VERSION 5.8 ;
BUSBITCHARS "[]" ;
DIVIDERCHAR "/" ;
UNITS
    DATABASE MICRONS 1000 ;
END UNITS

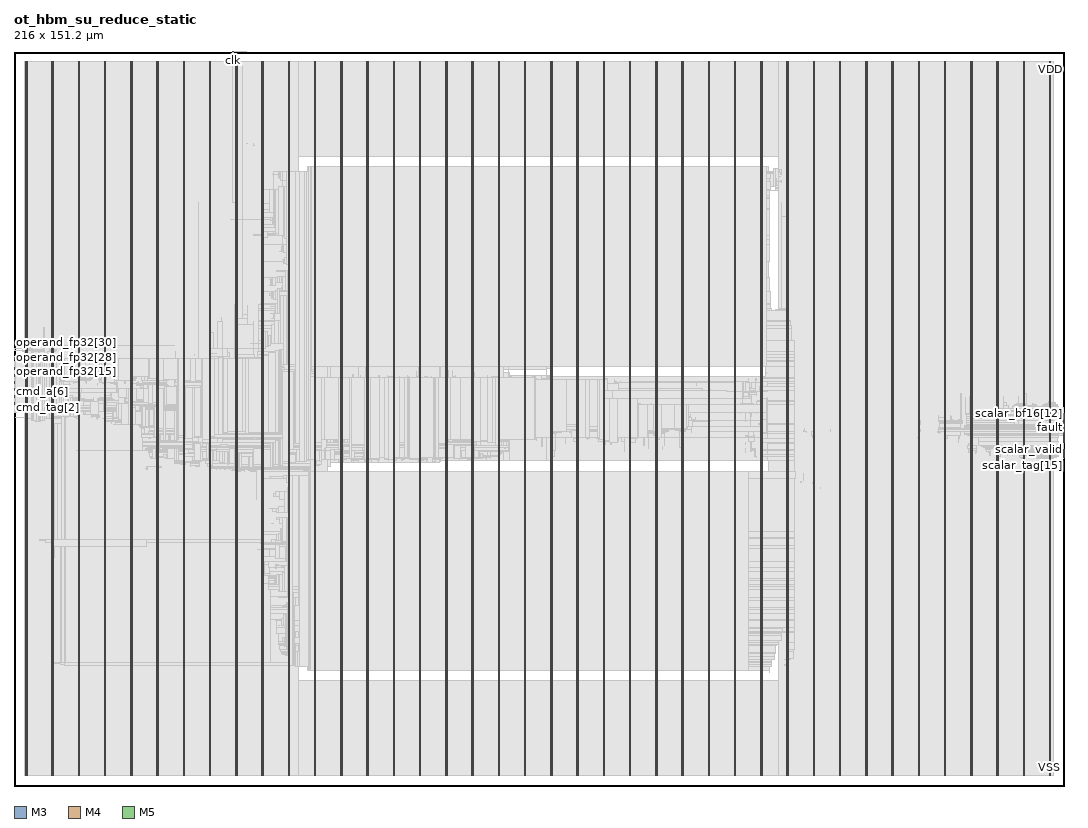
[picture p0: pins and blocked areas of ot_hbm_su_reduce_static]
MACRO ot_hbm_su_reduce_static
  FOREIGN ot_hbm_su_reduce_static 0 0 ;
  CLASS BLOCK ;
  SIZE 216 BY 151.2 ;
  PIN clk
    DIRECTION INPUT ;
    USE SIGNAL ;
    PORT
      LAYER M3 ;
        RECT  44.964 151.163 44.982 151.2 ;
    END
  END clk
  PIN cmd_a[0]
    DIRECTION INPUT ;
    USE SIGNAL ;
    PORT
      LAYER M4 ;
        RECT  0 80.592 0.084 80.616 ;
    END
  END cmd_a[0]
  PIN cmd_a[1]
    DIRECTION INPUT ;
    USE SIGNAL ;
    PORT
      LAYER M4 ;
        RECT  0 80.688 0.084 80.712 ;
    END
  END cmd_a[1]
  PIN cmd_a[2]
    DIRECTION INPUT ;
    USE SIGNAL ;
    PORT
      LAYER M4 ;
        RECT  0 80.784 0.084 80.808 ;
    END
  END cmd_a[2]
  PIN cmd_a[3]
    DIRECTION INPUT ;
    USE SIGNAL ;
    PORT
      LAYER M4 ;
        RECT  0 80.88 0.084 80.904 ;
    END
  END cmd_a[3]
  PIN cmd_a[4]
    DIRECTION INPUT ;
    USE SIGNAL ;
    PORT
      LAYER M4 ;
        RECT  0 80.976 0.084 81 ;
    END
  END cmd_a[4]
  PIN cmd_a[5]
    DIRECTION INPUT ;
    USE SIGNAL ;
    PORT
      LAYER M4 ;
        RECT  0 81.072 0.084 81.096 ;
    END
  END cmd_a[5]
  PIN cmd_a[6]
    DIRECTION INPUT ;
    USE SIGNAL ;
    PORT
      LAYER M4 ;
        RECT  0 81.168 0.084 81.192 ;
    END
  END cmd_a[6]
  PIN cmd_a[7]
    DIRECTION INPUT ;
    USE SIGNAL ;
    PORT
      LAYER M4 ;
        RECT  0 81.264 0.084 81.288 ;
    END
  END cmd_a[7]
  PIN cmd_a[8]
    DIRECTION INPUT ;
    USE SIGNAL ;
    PORT
      LAYER M4 ;
        RECT  0 81.36 0.084 81.384 ;
    END
  END cmd_a[8]
  PIN cmd_a[9]
    DIRECTION INPUT ;
    USE SIGNAL ;
    PORT
      LAYER M4 ;
        RECT  0 81.456 0.084 81.48 ;
    END
  END cmd_a[9]
  PIN cmd_b[0]
    DIRECTION INPUT ;
    USE SIGNAL ;
    PORT
      LAYER M4 ;
        RECT  0 81.552 0.084 81.576 ;
    END
  END cmd_b[0]
  PIN cmd_b[1]
    DIRECTION INPUT ;
    USE SIGNAL ;
    PORT
      LAYER M4 ;
        RECT  0 81.648 0.084 81.672 ;
    END
  END cmd_b[1]
  PIN cmd_b[2]
    DIRECTION INPUT ;
    USE SIGNAL ;
    PORT
      LAYER M4 ;
        RECT  0 81.744 0.084 81.768 ;
    END
  END cmd_b[2]
  PIN cmd_b[3]
    DIRECTION INPUT ;
    USE SIGNAL ;
    PORT
      LAYER M4 ;
        RECT  0 81.84 0.084 81.864 ;
    END
  END cmd_b[3]
  PIN cmd_b[4]
    DIRECTION INPUT ;
    USE SIGNAL ;
    PORT
      LAYER M4 ;
        RECT  0 81.936 0.084 81.96 ;
    END
  END cmd_b[4]
  PIN cmd_b[5]
    DIRECTION INPUT ;
    USE SIGNAL ;
    PORT
      LAYER M4 ;
        RECT  0 82.032 0.084 82.056 ;
    END
  END cmd_b[5]
  PIN cmd_b[6]
    DIRECTION INPUT ;
    USE SIGNAL ;
    PORT
      LAYER M4 ;
        RECT  0 82.128 0.084 82.152 ;
    END
  END cmd_b[6]
  PIN cmd_b[7]
    DIRECTION INPUT ;
    USE SIGNAL ;
    PORT
      LAYER M4 ;
        RECT  0 82.224 0.084 82.248 ;
    END
  END cmd_b[7]
  PIN cmd_b[8]
    DIRECTION INPUT ;
    USE SIGNAL ;
    PORT
      LAYER M4 ;
        RECT  0 82.32 0.084 82.344 ;
    END
  END cmd_b[8]
  PIN cmd_b[9]
    DIRECTION INPUT ;
    USE SIGNAL ;
    PORT
      LAYER M4 ;
        RECT  0 82.416 0.084 82.44 ;
    END
  END cmd_b[9]
  PIN cmd_dst[0]
    DIRECTION INPUT ;
    USE SIGNAL ;
    PORT
      LAYER M4 ;
        RECT  0 82.512 0.084 82.536 ;
    END
  END cmd_dst[0]
  PIN cmd_dst[1]
    DIRECTION INPUT ;
    USE SIGNAL ;
    PORT
      LAYER M4 ;
        RECT  0 82.608 0.084 82.632 ;
    END
  END cmd_dst[1]
  PIN cmd_dst[2]
    DIRECTION INPUT ;
    USE SIGNAL ;
    PORT
      LAYER M4 ;
        RECT  0 82.704 0.084 82.728 ;
    END
  END cmd_dst[2]
  PIN cmd_dst[3]
    DIRECTION INPUT ;
    USE SIGNAL ;
    PORT
      LAYER M4 ;
        RECT  0 82.8 0.084 82.824 ;
    END
  END cmd_dst[3]
  PIN cmd_dst[4]
    DIRECTION INPUT ;
    USE SIGNAL ;
    PORT
      LAYER M4 ;
        RECT  0 82.896 0.084 82.92 ;
    END
  END cmd_dst[4]
  PIN cmd_dst[5]
    DIRECTION INPUT ;
    USE SIGNAL ;
    PORT
      LAYER M4 ;
        RECT  0 82.992 0.084 83.016 ;
    END
  END cmd_dst[5]
  PIN cmd_dst[6]
    DIRECTION INPUT ;
    USE SIGNAL ;
    PORT
      LAYER M4 ;
        RECT  0 83.088 0.084 83.112 ;
    END
  END cmd_dst[6]
  PIN cmd_dst[7]
    DIRECTION INPUT ;
    USE SIGNAL ;
    PORT
      LAYER M4 ;
        RECT  0 83.184 0.084 83.208 ;
    END
  END cmd_dst[7]
  PIN cmd_dst[8]
    DIRECTION INPUT ;
    USE SIGNAL ;
    PORT
      LAYER M4 ;
        RECT  0 83.28 0.084 83.304 ;
    END
  END cmd_dst[8]
  PIN cmd_dst[9]
    DIRECTION INPUT ;
    USE SIGNAL ;
    PORT
      LAYER M4 ;
        RECT  0 83.376 0.084 83.4 ;
    END
  END cmd_dst[9]
  PIN cmd_op[0]
    DIRECTION INPUT ;
    USE SIGNAL ;
    PORT
      LAYER M4 ;
        RECT  0 83.472 0.084 83.496 ;
    END
  END cmd_op[0]
  PIN cmd_op[1]
    DIRECTION INPUT ;
    USE SIGNAL ;
    PORT
      LAYER M4 ;
        RECT  0 83.568 0.084 83.592 ;
    END
  END cmd_op[1]
  PIN cmd_op[2]
    DIRECTION INPUT ;
    USE SIGNAL ;
    PORT
      LAYER M4 ;
        RECT  0 77.52 0.084 77.544 ;
    END
  END cmd_op[2]
  PIN cmd_tag[0]
    DIRECTION INPUT ;
    USE SIGNAL ;
    PORT
      LAYER M4 ;
        RECT  0 77.616 0.084 77.64 ;
    END
  END cmd_tag[0]
  PIN cmd_tag[10]
    DIRECTION INPUT ;
    USE SIGNAL ;
    PORT
      LAYER M4 ;
        RECT  0 78.576 0.084 78.6 ;
    END
  END cmd_tag[10]
  PIN cmd_tag[11]
    DIRECTION INPUT ;
    USE SIGNAL ;
    PORT
      LAYER M4 ;
        RECT  0 78.672 0.084 78.696 ;
    END
  END cmd_tag[11]
  PIN cmd_tag[12]
    DIRECTION INPUT ;
    USE SIGNAL ;
    PORT
      LAYER M4 ;
        RECT  0 78.768 0.084 78.792 ;
    END
  END cmd_tag[12]
  PIN cmd_tag[13]
    DIRECTION INPUT ;
    USE SIGNAL ;
    PORT
      LAYER M4 ;
        RECT  0 78.864 0.084 78.888 ;
    END
  END cmd_tag[13]
  PIN cmd_tag[14]
    DIRECTION INPUT ;
    USE SIGNAL ;
    PORT
      LAYER M4 ;
        RECT  0 78.96 0.084 78.984 ;
    END
  END cmd_tag[14]
  PIN cmd_tag[15]
    DIRECTION INPUT ;
    USE SIGNAL ;
    PORT
      LAYER M4 ;
        RECT  0 79.056 0.084 79.08 ;
    END
  END cmd_tag[15]
  PIN cmd_tag[16]
    DIRECTION INPUT ;
    USE SIGNAL ;
    PORT
      LAYER M4 ;
        RECT  0 79.152 0.084 79.176 ;
    END
  END cmd_tag[16]
  PIN cmd_tag[17]
    DIRECTION INPUT ;
    USE SIGNAL ;
    PORT
      LAYER M4 ;
        RECT  0 79.248 0.084 79.272 ;
    END
  END cmd_tag[17]
  PIN cmd_tag[18]
    DIRECTION INPUT ;
    USE SIGNAL ;
    PORT
      LAYER M4 ;
        RECT  0 79.344 0.084 79.368 ;
    END
  END cmd_tag[18]
  PIN cmd_tag[19]
    DIRECTION INPUT ;
    USE SIGNAL ;
    PORT
      LAYER M4 ;
        RECT  0 79.44 0.084 79.464 ;
    END
  END cmd_tag[19]
  PIN cmd_tag[1]
    DIRECTION INPUT ;
    USE SIGNAL ;
    PORT
      LAYER M4 ;
        RECT  0 77.712 0.084 77.736 ;
    END
  END cmd_tag[1]
  PIN cmd_tag[20]
    DIRECTION INPUT ;
    USE SIGNAL ;
    PORT
      LAYER M4 ;
        RECT  0 79.536 0.084 79.56 ;
    END
  END cmd_tag[20]
  PIN cmd_tag[21]
    DIRECTION INPUT ;
    USE SIGNAL ;
    PORT
      LAYER M4 ;
        RECT  0 79.632 0.084 79.656 ;
    END
  END cmd_tag[21]
  PIN cmd_tag[22]
    DIRECTION INPUT ;
    USE SIGNAL ;
    PORT
      LAYER M4 ;
        RECT  0 79.728 0.084 79.752 ;
    END
  END cmd_tag[22]
  PIN cmd_tag[23]
    DIRECTION INPUT ;
    USE SIGNAL ;
    PORT
      LAYER M4 ;
        RECT  0 79.824 0.084 79.848 ;
    END
  END cmd_tag[23]
  PIN cmd_tag[24]
    DIRECTION INPUT ;
    USE SIGNAL ;
    PORT
      LAYER M4 ;
        RECT  0 79.92 0.084 79.944 ;
    END
  END cmd_tag[24]
  PIN cmd_tag[25]
    DIRECTION INPUT ;
    USE SIGNAL ;
    PORT
      LAYER M4 ;
        RECT  0 80.016 0.084 80.04 ;
    END
  END cmd_tag[25]
  PIN cmd_tag[26]
    DIRECTION INPUT ;
    USE SIGNAL ;
    PORT
      LAYER M4 ;
        RECT  0 80.112 0.084 80.136 ;
    END
  END cmd_tag[26]
  PIN cmd_tag[27]
    DIRECTION INPUT ;
    USE SIGNAL ;
    PORT
      LAYER M4 ;
        RECT  0 80.208 0.084 80.232 ;
    END
  END cmd_tag[27]
  PIN cmd_tag[28]
    DIRECTION INPUT ;
    USE SIGNAL ;
    PORT
      LAYER M4 ;
        RECT  0 80.304 0.084 80.328 ;
    END
  END cmd_tag[28]
  PIN cmd_tag[29]
    DIRECTION INPUT ;
    USE SIGNAL ;
    PORT
      LAYER M4 ;
        RECT  0 80.4 0.084 80.424 ;
    END
  END cmd_tag[29]
  PIN cmd_tag[2]
    DIRECTION INPUT ;
    USE SIGNAL ;
    PORT
      LAYER M4 ;
        RECT  0 77.808 0.084 77.832 ;
    END
  END cmd_tag[2]
  PIN cmd_tag[30]
    DIRECTION INPUT ;
    USE SIGNAL ;
    PORT
      LAYER M4 ;
        RECT  0 80.496 0.084 80.52 ;
    END
  END cmd_tag[30]
  PIN cmd_tag[31]
    DIRECTION INPUT ;
    USE SIGNAL ;
    PORT
      LAYER M4 ;
        RECT  0 83.664 0.084 83.688 ;
    END
  END cmd_tag[31]
  PIN cmd_tag[3]
    DIRECTION INPUT ;
    USE SIGNAL ;
    PORT
      LAYER M4 ;
        RECT  0 77.904 0.084 77.928 ;
    END
  END cmd_tag[3]
  PIN cmd_tag[4]
    DIRECTION INPUT ;
    USE SIGNAL ;
    PORT
      LAYER M4 ;
        RECT  0 78 0.084 78.024 ;
    END
  END cmd_tag[4]
  PIN cmd_tag[5]
    DIRECTION INPUT ;
    USE SIGNAL ;
    PORT
      LAYER M4 ;
        RECT  0 78.096 0.084 78.12 ;
    END
  END cmd_tag[5]
  PIN cmd_tag[6]
    DIRECTION INPUT ;
    USE SIGNAL ;
    PORT
      LAYER M4 ;
        RECT  0 78.192 0.084 78.216 ;
    END
  END cmd_tag[6]
  PIN cmd_tag[7]
    DIRECTION INPUT ;
    USE SIGNAL ;
    PORT
      LAYER M4 ;
        RECT  0 78.288 0.084 78.312 ;
    END
  END cmd_tag[7]
  PIN cmd_tag[8]
    DIRECTION INPUT ;
    USE SIGNAL ;
    PORT
      LAYER M4 ;
        RECT  0 78.384 0.084 78.408 ;
    END
  END cmd_tag[8]
  PIN cmd_tag[9]
    DIRECTION INPUT ;
    USE SIGNAL ;
    PORT
      LAYER M4 ;
        RECT  0 78.48 0.084 78.504 ;
    END
  END cmd_tag[9]
  PIN cmd_valid
    DIRECTION INPUT ;
    USE SIGNAL ;
    PORT
      LAYER M4 ;
        RECT  0 83.76 0.084 83.784 ;
    END
  END cmd_valid
  PIN fault
    DIRECTION OUTPUT ;
    USE SIGNAL ;
    PORT
      LAYER M4 ;
        RECT  215.916 73.68 216 73.704 ;
    END
  END fault
  PIN operand_fp32[0]
    DIRECTION INPUT ;
    USE SIGNAL ;
    PORT
      LAYER M4 ;
        RECT  0 83.856 0.084 83.88 ;
    END
  END operand_fp32[0]
  PIN operand_fp32[10]
    DIRECTION INPUT ;
    USE SIGNAL ;
    PORT
      LAYER M4 ;
        RECT  0 84.816 0.084 84.84 ;
    END
  END operand_fp32[10]
  PIN operand_fp32[11]
    DIRECTION INPUT ;
    USE SIGNAL ;
    PORT
      LAYER M4 ;
        RECT  0 84.912 0.084 84.936 ;
    END
  END operand_fp32[11]
  PIN operand_fp32[12]
    DIRECTION INPUT ;
    USE SIGNAL ;
    PORT
      LAYER M4 ;
        RECT  0 85.008 0.084 85.032 ;
    END
  END operand_fp32[12]
  PIN operand_fp32[13]
    DIRECTION INPUT ;
    USE SIGNAL ;
    PORT
      LAYER M4 ;
        RECT  0 85.104 0.084 85.128 ;
    END
  END operand_fp32[13]
  PIN operand_fp32[14]
    DIRECTION INPUT ;
    USE SIGNAL ;
    PORT
      LAYER M4 ;
        RECT  0 85.2 0.084 85.224 ;
    END
  END operand_fp32[14]
  PIN operand_fp32[15]
    DIRECTION INPUT ;
    USE SIGNAL ;
    PORT
      LAYER M4 ;
        RECT  0 85.296 0.084 85.32 ;
    END
  END operand_fp32[15]
  PIN operand_fp32[16]
    DIRECTION INPUT ;
    USE SIGNAL ;
    PORT
      LAYER M4 ;
        RECT  0 85.392 0.084 85.416 ;
    END
  END operand_fp32[16]
  PIN operand_fp32[17]
    DIRECTION INPUT ;
    USE SIGNAL ;
    PORT
      LAYER M4 ;
        RECT  0 85.488 0.084 85.512 ;
    END
  END operand_fp32[17]
  PIN operand_fp32[18]
    DIRECTION INPUT ;
    USE SIGNAL ;
    PORT
      LAYER M4 ;
        RECT  0 85.584 0.084 85.608 ;
    END
  END operand_fp32[18]
  PIN operand_fp32[19]
    DIRECTION INPUT ;
    USE SIGNAL ;
    PORT
      LAYER M4 ;
        RECT  0 85.68 0.084 85.704 ;
    END
  END operand_fp32[19]
  PIN operand_fp32[1]
    DIRECTION INPUT ;
    USE SIGNAL ;
    PORT
      LAYER M4 ;
        RECT  0 83.952 0.084 83.976 ;
    END
  END operand_fp32[1]
  PIN operand_fp32[20]
    DIRECTION INPUT ;
    USE SIGNAL ;
    PORT
      LAYER M4 ;
        RECT  0 85.776 0.084 85.8 ;
    END
  END operand_fp32[20]
  PIN operand_fp32[21]
    DIRECTION INPUT ;
    USE SIGNAL ;
    PORT
      LAYER M4 ;
        RECT  0 85.872 0.084 85.896 ;
    END
  END operand_fp32[21]
  PIN operand_fp32[22]
    DIRECTION INPUT ;
    USE SIGNAL ;
    PORT
      LAYER M4 ;
        RECT  0 85.968 0.084 85.992 ;
    END
  END operand_fp32[22]
  PIN operand_fp32[23]
    DIRECTION INPUT ;
    USE SIGNAL ;
    PORT
      LAYER M4 ;
        RECT  0 86.064 0.084 86.088 ;
    END
  END operand_fp32[23]
  PIN operand_fp32[24]
    DIRECTION INPUT ;
    USE SIGNAL ;
    PORT
      LAYER M4 ;
        RECT  0 86.16 0.084 86.184 ;
    END
  END operand_fp32[24]
  PIN operand_fp32[25]
    DIRECTION INPUT ;
    USE SIGNAL ;
    PORT
      LAYER M4 ;
        RECT  0 86.256 0.084 86.28 ;
    END
  END operand_fp32[25]
  PIN operand_fp32[26]
    DIRECTION INPUT ;
    USE SIGNAL ;
    PORT
      LAYER M4 ;
        RECT  0 86.352 0.084 86.376 ;
    END
  END operand_fp32[26]
  PIN operand_fp32[27]
    DIRECTION INPUT ;
    USE SIGNAL ;
    PORT
      LAYER M4 ;
        RECT  0 86.448 0.084 86.472 ;
    END
  END operand_fp32[27]
  PIN operand_fp32[28]
    DIRECTION INPUT ;
    USE SIGNAL ;
    PORT
      LAYER M4 ;
        RECT  0 86.544 0.084 86.568 ;
    END
  END operand_fp32[28]
  PIN operand_fp32[29]
    DIRECTION INPUT ;
    USE SIGNAL ;
    PORT
      LAYER M4 ;
        RECT  0 86.64 0.084 86.664 ;
    END
  END operand_fp32[29]
  PIN operand_fp32[2]
    DIRECTION INPUT ;
    USE SIGNAL ;
    PORT
      LAYER M4 ;
        RECT  0 84.048 0.084 84.072 ;
    END
  END operand_fp32[2]
  PIN operand_fp32[30]
    DIRECTION INPUT ;
    USE SIGNAL ;
    PORT
      LAYER M4 ;
        RECT  0 89.616 0.084 89.64 ;
    END
  END operand_fp32[30]
  PIN operand_fp32[31]
    DIRECTION INPUT ;
    USE SIGNAL ;
    PORT
      LAYER M4 ;
        RECT  0 89.712 0.084 89.736 ;
    END
  END operand_fp32[31]
  PIN operand_fp32[3]
    DIRECTION INPUT ;
    USE SIGNAL ;
    PORT
      LAYER M4 ;
        RECT  0 84.144 0.084 84.168 ;
    END
  END operand_fp32[3]
  PIN operand_fp32[4]
    DIRECTION INPUT ;
    USE SIGNAL ;
    PORT
      LAYER M4 ;
        RECT  0 84.24 0.084 84.264 ;
    END
  END operand_fp32[4]
  PIN operand_fp32[5]
    DIRECTION INPUT ;
    USE SIGNAL ;
    PORT
      LAYER M4 ;
        RECT  0 84.336 0.084 84.36 ;
    END
  END operand_fp32[5]
  PIN operand_fp32[6]
    DIRECTION INPUT ;
    USE SIGNAL ;
    PORT
      LAYER M4 ;
        RECT  0 84.432 0.084 84.456 ;
    END
  END operand_fp32[6]
  PIN operand_fp32[7]
    DIRECTION INPUT ;
    USE SIGNAL ;
    PORT
      LAYER M4 ;
        RECT  0 84.528 0.084 84.552 ;
    END
  END operand_fp32[7]
  PIN operand_fp32[8]
    DIRECTION INPUT ;
    USE SIGNAL ;
    PORT
      LAYER M4 ;
        RECT  0 84.624 0.084 84.648 ;
    END
  END operand_fp32[8]
  PIN operand_fp32[9]
    DIRECTION INPUT ;
    USE SIGNAL ;
    PORT
      LAYER M4 ;
        RECT  0 84.72 0.084 84.744 ;
    END
  END operand_fp32[9]
  PIN rst_n
    DIRECTION INPUT ;
    USE SIGNAL ;
    PORT
      LAYER M3 ;
        RECT  45.036 151.163 45.054 151.2 ;
    END
  END rst_n
  PIN scalar_bf16[0]
    DIRECTION OUTPUT ;
    USE SIGNAL ;
    PORT
      LAYER M4 ;
        RECT  215.916 73.776 216 73.8 ;
    END
  END scalar_bf16[0]
  PIN scalar_bf16[10]
    DIRECTION OUTPUT ;
    USE SIGNAL ;
    PORT
      LAYER M4 ;
        RECT  215.916 74.736 216 74.76 ;
    END
  END scalar_bf16[10]
  PIN scalar_bf16[11]
    DIRECTION OUTPUT ;
    USE SIGNAL ;
    PORT
      LAYER M4 ;
        RECT  215.916 74.832 216 74.856 ;
    END
  END scalar_bf16[11]
  PIN scalar_bf16[12]
    DIRECTION OUTPUT ;
    USE SIGNAL ;
    PORT
      LAYER M4 ;
        RECT  215.916 74.928 216 74.952 ;
    END
  END scalar_bf16[12]
  PIN scalar_bf16[13]
    DIRECTION OUTPUT ;
    USE SIGNAL ;
    PORT
      LAYER M4 ;
        RECT  215.916 75.024 216 75.048 ;
    END
  END scalar_bf16[13]
  PIN scalar_bf16[14]
    DIRECTION OUTPUT ;
    USE SIGNAL ;
    PORT
      LAYER M4 ;
        RECT  215.916 75.12 216 75.144 ;
    END
  END scalar_bf16[14]
  PIN scalar_bf16[15]
    DIRECTION OUTPUT ;
    USE SIGNAL ;
    PORT
      LAYER M4 ;
        RECT  215.916 75.216 216 75.24 ;
    END
  END scalar_bf16[15]
  PIN scalar_bf16[1]
    DIRECTION OUTPUT ;
    USE SIGNAL ;
    PORT
      LAYER M4 ;
        RECT  215.916 73.872 216 73.896 ;
    END
  END scalar_bf16[1]
  PIN scalar_bf16[2]
    DIRECTION OUTPUT ;
    USE SIGNAL ;
    PORT
      LAYER M4 ;
        RECT  215.916 73.968 216 73.992 ;
    END
  END scalar_bf16[2]
  PIN scalar_bf16[3]
    DIRECTION OUTPUT ;
    USE SIGNAL ;
    PORT
      LAYER M4 ;
        RECT  215.916 74.064 216 74.088 ;
    END
  END scalar_bf16[3]
  PIN scalar_bf16[4]
    DIRECTION OUTPUT ;
    USE SIGNAL ;
    PORT
      LAYER M4 ;
        RECT  215.916 74.16 216 74.184 ;
    END
  END scalar_bf16[4]
  PIN scalar_bf16[5]
    DIRECTION OUTPUT ;
    USE SIGNAL ;
    PORT
      LAYER M4 ;
        RECT  215.916 74.256 216 74.28 ;
    END
  END scalar_bf16[5]
  PIN scalar_bf16[6]
    DIRECTION OUTPUT ;
    USE SIGNAL ;
    PORT
      LAYER M4 ;
        RECT  215.916 74.352 216 74.376 ;
    END
  END scalar_bf16[6]
  PIN scalar_bf16[7]
    DIRECTION OUTPUT ;
    USE SIGNAL ;
    PORT
      LAYER M4 ;
        RECT  215.916 74.448 216 74.472 ;
    END
  END scalar_bf16[7]
  PIN scalar_bf16[8]
    DIRECTION OUTPUT ;
    USE SIGNAL ;
    PORT
      LAYER M4 ;
        RECT  215.916 74.544 216 74.568 ;
    END
  END scalar_bf16[8]
  PIN scalar_bf16[9]
    DIRECTION OUTPUT ;
    USE SIGNAL ;
    PORT
      LAYER M4 ;
        RECT  215.916 74.64 216 74.664 ;
    END
  END scalar_bf16[9]
  PIN scalar_fp32[0]
    DIRECTION OUTPUT ;
    USE SIGNAL ;
    PORT
      LAYER M4 ;
        RECT  215.916 75.312 216 75.336 ;
    END
  END scalar_fp32[0]
  PIN scalar_fp32[10]
    DIRECTION OUTPUT ;
    USE SIGNAL ;
    PORT
      LAYER M4 ;
        RECT  215.916 76.272 216 76.296 ;
    END
  END scalar_fp32[10]
  PIN scalar_fp32[11]
    DIRECTION OUTPUT ;
    USE SIGNAL ;
    PORT
      LAYER M4 ;
        RECT  215.916 76.368 216 76.392 ;
    END
  END scalar_fp32[11]
  PIN scalar_fp32[12]
    DIRECTION OUTPUT ;
    USE SIGNAL ;
    PORT
      LAYER M4 ;
        RECT  215.916 76.464 216 76.488 ;
    END
  END scalar_fp32[12]
  PIN scalar_fp32[13]
    DIRECTION OUTPUT ;
    USE SIGNAL ;
    PORT
      LAYER M4 ;
        RECT  215.916 76.56 216 76.584 ;
    END
  END scalar_fp32[13]
  PIN scalar_fp32[14]
    DIRECTION OUTPUT ;
    USE SIGNAL ;
    PORT
      LAYER M4 ;
        RECT  215.916 76.656 216 76.68 ;
    END
  END scalar_fp32[14]
  PIN scalar_fp32[15]
    DIRECTION OUTPUT ;
    USE SIGNAL ;
    PORT
      LAYER M4 ;
        RECT  215.916 70.608 216 70.632 ;
    END
  END scalar_fp32[15]
  PIN scalar_fp32[16]
    DIRECTION OUTPUT ;
    USE SIGNAL ;
    PORT
      LAYER M4 ;
        RECT  215.916 70.704 216 70.728 ;
    END
  END scalar_fp32[16]
  PIN scalar_fp32[17]
    DIRECTION OUTPUT ;
    USE SIGNAL ;
    PORT
      LAYER M4 ;
        RECT  215.916 70.8 216 70.824 ;
    END
  END scalar_fp32[17]
  PIN scalar_fp32[18]
    DIRECTION OUTPUT ;
    USE SIGNAL ;
    PORT
      LAYER M4 ;
        RECT  215.916 70.896 216 70.92 ;
    END
  END scalar_fp32[18]
  PIN scalar_fp32[19]
    DIRECTION OUTPUT ;
    USE SIGNAL ;
    PORT
      LAYER M4 ;
        RECT  215.916 70.992 216 71.016 ;
    END
  END scalar_fp32[19]
  PIN scalar_fp32[1]
    DIRECTION OUTPUT ;
    USE SIGNAL ;
    PORT
      LAYER M4 ;
        RECT  215.916 75.408 216 75.432 ;
    END
  END scalar_fp32[1]
  PIN scalar_fp32[20]
    DIRECTION OUTPUT ;
    USE SIGNAL ;
    PORT
      LAYER M4 ;
        RECT  215.916 71.088 216 71.112 ;
    END
  END scalar_fp32[20]
  PIN scalar_fp32[21]
    DIRECTION OUTPUT ;
    USE SIGNAL ;
    PORT
      LAYER M4 ;
        RECT  215.916 71.184 216 71.208 ;
    END
  END scalar_fp32[21]
  PIN scalar_fp32[22]
    DIRECTION OUTPUT ;
    USE SIGNAL ;
    PORT
      LAYER M4 ;
        RECT  215.916 71.28 216 71.304 ;
    END
  END scalar_fp32[22]
  PIN scalar_fp32[23]
    DIRECTION OUTPUT ;
    USE SIGNAL ;
    PORT
      LAYER M4 ;
        RECT  215.916 71.376 216 71.4 ;
    END
  END scalar_fp32[23]
  PIN scalar_fp32[24]
    DIRECTION OUTPUT ;
    USE SIGNAL ;
    PORT
      LAYER M4 ;
        RECT  215.916 71.472 216 71.496 ;
    END
  END scalar_fp32[24]
  PIN scalar_fp32[25]
    DIRECTION OUTPUT ;
    USE SIGNAL ;
    PORT
      LAYER M4 ;
        RECT  215.916 71.568 216 71.592 ;
    END
  END scalar_fp32[25]
  PIN scalar_fp32[26]
    DIRECTION OUTPUT ;
    USE SIGNAL ;
    PORT
      LAYER M4 ;
        RECT  215.916 71.664 216 71.688 ;
    END
  END scalar_fp32[26]
  PIN scalar_fp32[27]
    DIRECTION OUTPUT ;
    USE SIGNAL ;
    PORT
      LAYER M4 ;
        RECT  215.916 71.76 216 71.784 ;
    END
  END scalar_fp32[27]
  PIN scalar_fp32[28]
    DIRECTION OUTPUT ;
    USE SIGNAL ;
    PORT
      LAYER M4 ;
        RECT  215.916 71.856 216 71.88 ;
    END
  END scalar_fp32[28]
  PIN scalar_fp32[29]
    DIRECTION OUTPUT ;
    USE SIGNAL ;
    PORT
      LAYER M4 ;
        RECT  215.916 71.952 216 71.976 ;
    END
  END scalar_fp32[29]
  PIN scalar_fp32[2]
    DIRECTION OUTPUT ;
    USE SIGNAL ;
    PORT
      LAYER M4 ;
        RECT  215.916 75.504 216 75.528 ;
    END
  END scalar_fp32[2]
  PIN scalar_fp32[30]
    DIRECTION OUTPUT ;
    USE SIGNAL ;
    PORT
      LAYER M4 ;
        RECT  215.916 72.048 216 72.072 ;
    END
  END scalar_fp32[30]
  PIN scalar_fp32[31]
    DIRECTION OUTPUT ;
    USE SIGNAL ;
    PORT
      LAYER M4 ;
        RECT  215.916 72.144 216 72.168 ;
    END
  END scalar_fp32[31]
  PIN scalar_fp32[3]
    DIRECTION OUTPUT ;
    USE SIGNAL ;
    PORT
      LAYER M4 ;
        RECT  215.916 75.6 216 75.624 ;
    END
  END scalar_fp32[3]
  PIN scalar_fp32[4]
    DIRECTION OUTPUT ;
    USE SIGNAL ;
    PORT
      LAYER M4 ;
        RECT  215.916 75.696 216 75.72 ;
    END
  END scalar_fp32[4]
  PIN scalar_fp32[5]
    DIRECTION OUTPUT ;
    USE SIGNAL ;
    PORT
      LAYER M4 ;
        RECT  215.916 75.792 216 75.816 ;
    END
  END scalar_fp32[5]
  PIN scalar_fp32[6]
    DIRECTION OUTPUT ;
    USE SIGNAL ;
    PORT
      LAYER M4 ;
        RECT  215.916 75.888 216 75.912 ;
    END
  END scalar_fp32[6]
  PIN scalar_fp32[7]
    DIRECTION OUTPUT ;
    USE SIGNAL ;
    PORT
      LAYER M4 ;
        RECT  215.916 75.984 216 76.008 ;
    END
  END scalar_fp32[7]
  PIN scalar_fp32[8]
    DIRECTION OUTPUT ;
    USE SIGNAL ;
    PORT
      LAYER M4 ;
        RECT  215.916 76.08 216 76.104 ;
    END
  END scalar_fp32[8]
  PIN scalar_fp32[9]
    DIRECTION OUTPUT ;
    USE SIGNAL ;
    PORT
      LAYER M4 ;
        RECT  215.916 76.176 216 76.2 ;
    END
  END scalar_fp32[9]
  PIN scalar_tag[0]
    DIRECTION OUTPUT ;
    USE SIGNAL ;
    PORT
      LAYER M4 ;
        RECT  215.916 72.24 216 72.264 ;
    END
  END scalar_tag[0]
  PIN scalar_tag[10]
    DIRECTION OUTPUT ;
    USE SIGNAL ;
    PORT
      LAYER M4 ;
        RECT  215.916 73.2 216 73.224 ;
    END
  END scalar_tag[10]
  PIN scalar_tag[11]
    DIRECTION OUTPUT ;
    USE SIGNAL ;
    PORT
      LAYER M4 ;
        RECT  215.916 73.296 216 73.32 ;
    END
  END scalar_tag[11]
  PIN scalar_tag[12]
    DIRECTION OUTPUT ;
    USE SIGNAL ;
    PORT
      LAYER M4 ;
        RECT  215.916 73.392 216 73.416 ;
    END
  END scalar_tag[12]
  PIN scalar_tag[13]
    DIRECTION OUTPUT ;
    USE SIGNAL ;
    PORT
      LAYER M4 ;
        RECT  215.916 73.488 216 73.512 ;
    END
  END scalar_tag[13]
  PIN scalar_tag[14]
    DIRECTION OUTPUT ;
    USE SIGNAL ;
    PORT
      LAYER M4 ;
        RECT  215.916 73.584 216 73.608 ;
    END
  END scalar_tag[14]
  PIN scalar_tag[15]
    DIRECTION OUTPUT ;
    USE SIGNAL ;
    PORT
      LAYER M4 ;
        RECT  215.916 67.536 216 67.56 ;
    END
  END scalar_tag[15]
  PIN scalar_tag[16]
    DIRECTION OUTPUT ;
    USE SIGNAL ;
    PORT
      LAYER M4 ;
        RECT  215.916 67.632 216 67.656 ;
    END
  END scalar_tag[16]
  PIN scalar_tag[17]
    DIRECTION OUTPUT ;
    USE SIGNAL ;
    PORT
      LAYER M4 ;
        RECT  215.916 67.728 216 67.752 ;
    END
  END scalar_tag[17]
  PIN scalar_tag[18]
    DIRECTION OUTPUT ;
    USE SIGNAL ;
    PORT
      LAYER M4 ;
        RECT  215.916 67.824 216 67.848 ;
    END
  END scalar_tag[18]
  PIN scalar_tag[19]
    DIRECTION OUTPUT ;
    USE SIGNAL ;
    PORT
      LAYER M4 ;
        RECT  215.916 67.92 216 67.944 ;
    END
  END scalar_tag[19]
  PIN scalar_tag[1]
    DIRECTION OUTPUT ;
    USE SIGNAL ;
    PORT
      LAYER M4 ;
        RECT  215.916 72.336 216 72.36 ;
    END
  END scalar_tag[1]
  PIN scalar_tag[20]
    DIRECTION OUTPUT ;
    USE SIGNAL ;
    PORT
      LAYER M4 ;
        RECT  215.916 68.016 216 68.04 ;
    END
  END scalar_tag[20]
  PIN scalar_tag[21]
    DIRECTION OUTPUT ;
    USE SIGNAL ;
    PORT
      LAYER M4 ;
        RECT  215.916 68.112 216 68.136 ;
    END
  END scalar_tag[21]
  PIN scalar_tag[22]
    DIRECTION OUTPUT ;
    USE SIGNAL ;
    PORT
      LAYER M4 ;
        RECT  215.916 68.208 216 68.232 ;
    END
  END scalar_tag[22]
  PIN scalar_tag[23]
    DIRECTION OUTPUT ;
    USE SIGNAL ;
    PORT
      LAYER M4 ;
        RECT  215.916 68.304 216 68.328 ;
    END
  END scalar_tag[23]
  PIN scalar_tag[24]
    DIRECTION OUTPUT ;
    USE SIGNAL ;
    PORT
      LAYER M4 ;
        RECT  215.916 68.4 216 68.424 ;
    END
  END scalar_tag[24]
  PIN scalar_tag[25]
    DIRECTION OUTPUT ;
    USE SIGNAL ;
    PORT
      LAYER M4 ;
        RECT  215.916 68.496 216 68.52 ;
    END
  END scalar_tag[25]
  PIN scalar_tag[26]
    DIRECTION OUTPUT ;
    USE SIGNAL ;
    PORT
      LAYER M4 ;
        RECT  215.916 68.592 216 68.616 ;
    END
  END scalar_tag[26]
  PIN scalar_tag[27]
    DIRECTION OUTPUT ;
    USE SIGNAL ;
    PORT
      LAYER M4 ;
        RECT  215.916 68.688 216 68.712 ;
    END
  END scalar_tag[27]
  PIN scalar_tag[28]
    DIRECTION OUTPUT ;
    USE SIGNAL ;
    PORT
      LAYER M4 ;
        RECT  215.916 68.784 216 68.808 ;
    END
  END scalar_tag[28]
  PIN scalar_tag[29]
    DIRECTION OUTPUT ;
    USE SIGNAL ;
    PORT
      LAYER M4 ;
        RECT  215.916 68.88 216 68.904 ;
    END
  END scalar_tag[29]
  PIN scalar_tag[2]
    DIRECTION OUTPUT ;
    USE SIGNAL ;
    PORT
      LAYER M4 ;
        RECT  215.916 72.432 216 72.456 ;
    END
  END scalar_tag[2]
  PIN scalar_tag[30]
    DIRECTION OUTPUT ;
    USE SIGNAL ;
    PORT
      LAYER M4 ;
        RECT  215.916 68.976 216 69 ;
    END
  END scalar_tag[30]
  PIN scalar_tag[31]
    DIRECTION OUTPUT ;
    USE SIGNAL ;
    PORT
      LAYER M4 ;
        RECT  215.916 69.072 216 69.096 ;
    END
  END scalar_tag[31]
  PIN scalar_tag[3]
    DIRECTION OUTPUT ;
    USE SIGNAL ;
    PORT
      LAYER M4 ;
        RECT  215.916 72.528 216 72.552 ;
    END
  END scalar_tag[3]
  PIN scalar_tag[4]
    DIRECTION OUTPUT ;
    USE SIGNAL ;
    PORT
      LAYER M4 ;
        RECT  215.916 72.624 216 72.648 ;
    END
  END scalar_tag[4]
  PIN scalar_tag[5]
    DIRECTION OUTPUT ;
    USE SIGNAL ;
    PORT
      LAYER M4 ;
        RECT  215.916 72.72 216 72.744 ;
    END
  END scalar_tag[5]
  PIN scalar_tag[6]
    DIRECTION OUTPUT ;
    USE SIGNAL ;
    PORT
      LAYER M4 ;
        RECT  215.916 72.816 216 72.84 ;
    END
  END scalar_tag[6]
  PIN scalar_tag[7]
    DIRECTION OUTPUT ;
    USE SIGNAL ;
    PORT
      LAYER M4 ;
        RECT  215.916 72.912 216 72.936 ;
    END
  END scalar_tag[7]
  PIN scalar_tag[8]
    DIRECTION OUTPUT ;
    USE SIGNAL ;
    PORT
      LAYER M4 ;
        RECT  215.916 73.008 216 73.032 ;
    END
  END scalar_tag[8]
  PIN scalar_tag[9]
    DIRECTION OUTPUT ;
    USE SIGNAL ;
    PORT
      LAYER M4 ;
        RECT  215.916 73.104 216 73.128 ;
    END
  END scalar_tag[9]
  PIN scalar_valid
    DIRECTION OUTPUT ;
    USE SIGNAL ;
    PORT
      LAYER M4 ;
        RECT  215.916 69.168 216 69.192 ;
    END
  END scalar_valid
  PIN VDD
    DIRECTION INOUT ;
    USE POWER ;
    PORT
      LAYER M5 ;
        RECT  213.192 2.151 213.312 149.049 ;
        RECT  207.792 2.151 207.912 149.049 ;
        RECT  202.392 2.151 202.512 149.049 ;
        RECT  196.992 2.151 197.112 149.049 ;
        RECT  191.592 2.151 191.712 149.049 ;
        RECT  186.192 2.151 186.312 149.049 ;
        RECT  180.792 2.151 180.912 149.049 ;
        RECT  175.392 2.151 175.512 149.049 ;
        RECT  169.992 2.151 170.112 149.049 ;
        RECT  164.592 2.151 164.712 149.049 ;
        RECT  159.192 2.151 159.312 149.049 ;
        RECT  153.792 2.151 153.912 149.049 ;
        RECT  148.392 2.151 148.512 149.049 ;
        RECT  142.992 2.151 143.112 149.049 ;
        RECT  137.592 2.151 137.712 149.049 ;
        RECT  132.192 2.151 132.312 149.049 ;
        RECT  126.792 2.151 126.912 149.049 ;
        RECT  121.392 2.151 121.512 149.049 ;
        RECT  115.992 2.151 116.112 149.049 ;
        RECT  110.592 2.151 110.712 149.049 ;
        RECT  105.192 2.151 105.312 149.049 ;
        RECT  99.792 2.151 99.912 149.049 ;
        RECT  94.392 2.151 94.512 149.049 ;
        RECT  88.992 2.151 89.112 149.049 ;
        RECT  83.592 2.151 83.712 149.049 ;
        RECT  78.192 2.151 78.312 149.049 ;
        RECT  72.792 2.151 72.912 149.049 ;
        RECT  67.392 2.151 67.512 149.049 ;
        RECT  61.992 2.151 62.112 149.049 ;
        RECT  56.592 2.151 56.712 149.049 ;
        RECT  51.192 2.151 51.312 149.049 ;
        RECT  45.792 2.151 45.912 149.049 ;
        RECT  40.392 2.151 40.512 149.049 ;
        RECT  34.992 2.151 35.112 149.049 ;
        RECT  29.592 2.151 29.712 149.049 ;
        RECT  24.192 2.151 24.312 149.049 ;
        RECT  18.792 2.151 18.912 149.049 ;
        RECT  13.392 2.151 13.512 149.049 ;
        RECT  7.992 2.151 8.112 149.049 ;
        RECT  2.592 2.151 2.712 149.049 ;
    END
  END VDD
  PIN VSS
    DIRECTION INOUT ;
    USE GROUND ;
    PORT
      LAYER M5 ;
        RECT  213 2.137 213.12 149.063 ;
        RECT  207.6 2.137 207.72 149.063 ;
        RECT  202.2 2.137 202.32 149.063 ;
        RECT  196.8 2.137 196.92 149.063 ;
        RECT  191.4 2.137 191.52 149.063 ;
        RECT  186 2.137 186.12 149.063 ;
        RECT  180.6 2.137 180.72 149.063 ;
        RECT  175.2 2.137 175.32 149.063 ;
        RECT  169.8 2.137 169.92 149.063 ;
        RECT  164.4 2.137 164.52 149.063 ;
        RECT  159 2.137 159.12 149.063 ;
        RECT  153.6 2.137 153.72 149.063 ;
        RECT  148.2 2.137 148.32 149.063 ;
        RECT  142.8 2.137 142.92 149.063 ;
        RECT  137.4 2.137 137.52 149.063 ;
        RECT  132 2.137 132.12 149.063 ;
        RECT  126.6 2.137 126.72 149.063 ;
        RECT  121.2 2.137 121.32 149.063 ;
        RECT  115.8 2.137 115.92 149.063 ;
        RECT  110.4 2.137 110.52 149.063 ;
        RECT  105 2.137 105.12 149.063 ;
        RECT  99.6 2.137 99.72 149.063 ;
        RECT  94.2 2.137 94.32 149.063 ;
        RECT  88.8 2.137 88.92 149.063 ;
        RECT  83.4 2.137 83.52 149.063 ;
        RECT  78 2.137 78.12 149.063 ;
        RECT  72.6 2.137 72.72 149.063 ;
        RECT  67.2 2.137 67.32 149.063 ;
        RECT  61.8 2.137 61.92 149.063 ;
        RECT  56.4 2.137 56.52 149.063 ;
        RECT  51 2.137 51.12 149.063 ;
        RECT  45.6 2.137 45.72 149.063 ;
        RECT  40.2 2.137 40.32 149.063 ;
        RECT  34.8 2.137 34.92 149.063 ;
        RECT  29.4 2.137 29.52 149.063 ;
        RECT  24 2.137 24.12 149.063 ;
        RECT  18.6 2.137 18.72 149.063 ;
        RECT  13.2 2.137 13.32 149.063 ;
        RECT  7.8 2.137 7.92 149.063 ;
        RECT  2.4 2.137 2.52 149.063 ;
    END
  END VSS
  # OT_OBS_CLOSED layer=M5 d_um=1.536 added=227
  OBS
    LAYER RVTN ;
     RECT  2.16 2.16 213.84 2.295 ;
     RECT  2.16 2.565 213.84 2.835 ;
     RECT  2.16 3.105 213.84 3.375 ;
     RECT  2.16 3.645 213.84 3.915 ;
     RECT  2.16 4.185 213.84 4.455 ;
     RECT  2.16 4.725 213.84 4.995 ;
     RECT  2.16 5.265 213.84 5.535 ;
     RECT  2.16 5.805 213.84 6.075 ;
     RECT  2.16 6.345 213.84 6.615 ;
     RECT  2.16 6.885 213.84 7.155 ;
     RECT  2.16 7.425 213.84 7.695 ;
     RECT  2.16 7.965 213.84 8.235 ;
     RECT  2.16 8.505 213.84 8.775 ;
     RECT  2.16 9.045 213.84 9.315 ;
     RECT  2.16 9.585 213.84 9.855 ;
     RECT  2.16 10.125 213.84 10.395 ;
     RECT  2.16 10.665 213.84 10.935 ;
     RECT  2.16 11.205 213.84 11.475 ;
     RECT  2.16 11.745 213.84 12.015 ;
     RECT  2.16 12.285 213.84 12.555 ;
     RECT  2.16 12.825 213.84 13.095 ;
     RECT  2.16 13.365 213.84 13.635 ;
     RECT  2.16 13.905 213.84 14.175 ;
     RECT  2.16 14.445 213.84 14.715 ;
     RECT  2.16 14.985 213.84 15.255 ;
     RECT  2.16 15.525 213.84 15.795 ;
     RECT  2.16 16.065 213.84 16.335 ;
     RECT  2.16 16.605 213.84 16.875 ;
     RECT  2.16 17.145 213.84 17.415 ;
     RECT  2.16 17.685 213.84 17.955 ;
     RECT  2.16 18.225 213.84 18.495 ;
     RECT  2.16 18.765 213.84 19.035 ;
     RECT  2.16 19.305 213.84 19.575 ;
     RECT  2.16 19.845 213.84 20.115 ;
     RECT  2.16 20.385 213.84 20.655 ;
     RECT  2.16 20.925 213.84 21.195 ;
     RECT  2.16 21.465 213.84 21.6 ;
     RECT  2.16 21.6 58.428 21.735 ;
     RECT  157.356 21.6 213.84 21.735 ;
     RECT  2.16 22.005 58.428 22.275 ;
     RECT  157.356 22.005 213.84 22.275 ;
     RECT  2.16 22.545 58.428 22.815 ;
     RECT  157.356 22.545 213.84 22.815 ;
     RECT  2.16 23.085 58.428 23.355 ;
     RECT  157.356 23.085 213.84 23.355 ;
     RECT  2.16 23.625 58.428 23.895 ;
     RECT  157.356 23.625 213.84 23.895 ;
     RECT  2.16 24.165 58.428 24.435 ;
     RECT  157.356 24.165 213.84 24.435 ;
     RECT  2.16 24.705 58.428 24.975 ;
     RECT  157.356 24.705 213.84 24.975 ;
     RECT  2.16 25.245 58.428 25.515 ;
     RECT  157.356 25.245 213.84 25.515 ;
     RECT  2.16 25.785 58.428 26.055 ;
     RECT  157.356 25.785 213.84 26.055 ;
     RECT  2.16 26.325 58.428 26.595 ;
     RECT  157.356 26.325 213.84 26.595 ;
     RECT  2.16 26.865 58.428 27.135 ;
     RECT  157.356 26.865 213.84 27.135 ;
     RECT  2.16 27.405 58.428 27.675 ;
     RECT  157.356 27.405 213.84 27.675 ;
     RECT  2.16 27.945 58.428 28.215 ;
     RECT  157.356 27.945 213.84 28.215 ;
     RECT  2.16 28.485 58.428 28.755 ;
     RECT  157.356 28.485 213.84 28.755 ;
     RECT  2.16 29.025 58.428 29.295 ;
     RECT  157.356 29.025 213.84 29.295 ;
     RECT  2.16 29.565 58.428 29.835 ;
     RECT  157.356 29.565 213.84 29.835 ;
     RECT  2.16 30.105 58.428 30.375 ;
     RECT  157.356 30.105 213.84 30.375 ;
     RECT  2.16 30.645 58.428 30.915 ;
     RECT  157.356 30.645 213.84 30.915 ;
     RECT  2.16 31.185 58.428 31.455 ;
     RECT  157.356 31.185 213.84 31.455 ;
     RECT  2.16 31.725 58.428 31.995 ;
     RECT  157.356 31.725 213.84 31.995 ;
     RECT  2.16 32.265 58.428 32.535 ;
     RECT  157.356 32.265 213.84 32.535 ;
     RECT  2.16 32.805 58.428 33.075 ;
     RECT  157.356 32.805 213.84 33.075 ;
     RECT  2.16 33.345 58.428 33.615 ;
     RECT  157.356 33.345 213.84 33.615 ;
     RECT  2.16 33.885 58.428 34.155 ;
     RECT  157.356 33.885 213.84 34.155 ;
     RECT  2.16 34.425 58.428 34.695 ;
     RECT  157.356 34.425 213.84 34.695 ;
     RECT  2.16 34.965 58.428 35.235 ;
     RECT  157.356 34.965 213.84 35.235 ;
     RECT  2.16 35.505 58.428 35.775 ;
     RECT  157.356 35.505 213.84 35.775 ;
     RECT  2.16 36.045 58.428 36.315 ;
     RECT  157.356 36.045 213.84 36.315 ;
     RECT  2.16 36.585 58.428 36.855 ;
     RECT  157.356 36.585 213.84 36.855 ;
     RECT  2.16 37.125 58.428 37.395 ;
     RECT  157.356 37.125 213.84 37.395 ;
     RECT  2.16 37.665 58.428 37.935 ;
     RECT  157.356 37.665 213.84 37.935 ;
     RECT  2.16 38.205 58.428 38.475 ;
     RECT  157.356 38.205 213.84 38.475 ;
     RECT  2.16 38.745 58.428 39.015 ;
     RECT  157.356 38.745 213.84 39.015 ;
     RECT  2.16 39.285 58.428 39.555 ;
     RECT  157.356 39.285 213.84 39.555 ;
     RECT  2.16 39.825 58.428 40.095 ;
     RECT  157.356 39.825 213.84 40.095 ;
     RECT  2.16 40.365 58.428 40.635 ;
     RECT  157.356 40.365 213.84 40.635 ;
     RECT  2.16 40.905 58.428 41.175 ;
     RECT  157.356 40.905 213.84 41.175 ;
     RECT  2.16 41.445 58.428 41.715 ;
     RECT  157.356 41.445 213.84 41.715 ;
     RECT  2.16 41.985 58.428 42.255 ;
     RECT  157.356 41.985 213.84 42.255 ;
     RECT  2.16 42.525 58.428 42.795 ;
     RECT  157.356 42.525 213.84 42.795 ;
     RECT  2.16 43.065 58.428 43.335 ;
     RECT  157.356 43.065 213.84 43.335 ;
     RECT  2.16 43.605 58.428 43.875 ;
     RECT  157.356 43.605 213.84 43.875 ;
     RECT  2.16 44.145 58.428 44.415 ;
     RECT  157.356 44.145 213.84 44.415 ;
     RECT  2.16 44.685 58.428 44.955 ;
     RECT  157.356 44.685 213.84 44.955 ;
     RECT  2.16 45.225 58.428 45.495 ;
     RECT  157.356 45.225 213.84 45.495 ;
     RECT  2.16 45.765 58.428 46.035 ;
     RECT  157.356 45.765 213.84 46.035 ;
     RECT  2.16 46.305 58.428 46.575 ;
     RECT  157.356 46.305 213.84 46.575 ;
     RECT  2.16 46.845 58.428 47.115 ;
     RECT  157.356 46.845 213.84 47.115 ;
     RECT  2.16 47.385 58.428 47.655 ;
     RECT  157.356 47.385 213.84 47.655 ;
     RECT  2.16 47.925 58.428 48.195 ;
     RECT  157.356 47.925 213.84 48.195 ;
     RECT  2.16 48.465 58.428 48.735 ;
     RECT  157.356 48.465 213.84 48.735 ;
     RECT  2.16 49.005 58.428 49.275 ;
     RECT  157.356 49.005 213.84 49.275 ;
     RECT  2.16 49.545 58.428 49.815 ;
     RECT  157.356 49.545 213.84 49.815 ;
     RECT  2.16 50.085 58.428 50.355 ;
     RECT  157.356 50.085 213.84 50.355 ;
     RECT  2.16 50.625 58.428 50.895 ;
     RECT  157.356 50.625 213.84 50.895 ;
     RECT  2.16 51.165 58.428 51.435 ;
     RECT  157.356 51.165 213.84 51.435 ;
     RECT  2.16 51.705 58.428 51.975 ;
     RECT  157.356 51.705 213.84 51.975 ;
     RECT  2.16 52.245 58.428 52.515 ;
     RECT  157.356 52.245 213.84 52.515 ;
     RECT  2.16 52.785 58.428 53.055 ;
     RECT  157.356 52.785 213.84 53.055 ;
     RECT  2.16 53.325 58.428 53.595 ;
     RECT  157.356 53.325 213.84 53.595 ;
     RECT  2.16 53.865 58.428 54.135 ;
     RECT  157.356 53.865 213.84 54.135 ;
     RECT  2.16 54.405 58.428 54.675 ;
     RECT  157.356 54.405 213.84 54.675 ;
     RECT  2.16 54.945 58.428 55.215 ;
     RECT  157.356 54.945 213.84 55.215 ;
     RECT  2.16 55.485 58.428 55.755 ;
     RECT  157.356 55.485 213.84 55.755 ;
     RECT  2.16 56.025 58.428 56.295 ;
     RECT  157.356 56.025 213.84 56.295 ;
     RECT  2.16 56.565 58.428 56.835 ;
     RECT  157.356 56.565 213.84 56.835 ;
     RECT  2.16 57.105 58.428 57.375 ;
     RECT  157.356 57.105 213.84 57.375 ;
     RECT  2.16 57.645 58.428 57.915 ;
     RECT  157.356 57.645 213.84 57.915 ;
     RECT  2.16 58.185 58.428 58.455 ;
     RECT  157.356 58.185 213.84 58.455 ;
     RECT  2.16 58.725 58.428 58.995 ;
     RECT  157.356 58.725 213.84 58.995 ;
     RECT  2.16 59.265 58.428 59.535 ;
     RECT  157.356 59.265 213.84 59.535 ;
     RECT  2.16 59.805 58.428 60.075 ;
     RECT  157.356 59.805 213.84 60.075 ;
     RECT  2.16 60.345 58.428 60.615 ;
     RECT  157.356 60.345 213.84 60.615 ;
     RECT  2.16 60.885 58.428 61.155 ;
     RECT  157.356 60.885 213.84 61.155 ;
     RECT  2.16 61.425 58.428 61.695 ;
     RECT  157.356 61.425 213.84 61.695 ;
     RECT  2.16 61.965 58.428 62.235 ;
     RECT  157.356 61.965 213.84 62.235 ;
     RECT  2.16 62.505 58.428 62.775 ;
     RECT  157.356 62.505 213.84 62.775 ;
     RECT  2.16 63.045 58.428 63.315 ;
     RECT  157.356 63.045 213.84 63.315 ;
     RECT  2.16 63.585 58.428 63.855 ;
     RECT  157.356 63.585 213.84 63.855 ;
     RECT  2.16 64.125 58.428 64.395 ;
     RECT  157.356 64.125 213.84 64.395 ;
     RECT  2.16 64.665 58.428 64.935 ;
     RECT  157.356 64.665 213.84 64.935 ;
     RECT  2.16 65.205 58.428 65.475 ;
     RECT  157.356 65.205 213.84 65.475 ;
     RECT  2.16 65.745 58.428 66.015 ;
     RECT  157.356 65.745 213.84 66.015 ;
     RECT  2.16 66.285 58.428 66.555 ;
     RECT  157.356 66.285 213.84 66.555 ;
     RECT  2.16 66.825 58.428 66.96 ;
     RECT  157.356 66.825 213.84 66.96 ;
     RECT  2.16 66.96 213.84 67.095 ;
     RECT  2.16 67.365 213.84 67.635 ;
     RECT  2.16 67.905 213.84 68.175 ;
     RECT  2.16 68.445 213.84 68.715 ;
     RECT  2.16 68.985 213.84 69.255 ;
     RECT  2.16 69.525 213.84 69.795 ;
     RECT  2.16 70.065 213.84 70.335 ;
     RECT  2.16 70.605 213.84 70.875 ;
     RECT  2.16 71.145 213.84 71.415 ;
     RECT  2.16 71.685 213.84 71.955 ;
     RECT  2.16 72.225 213.84 72.495 ;
     RECT  2.16 72.765 213.84 73.035 ;
     RECT  2.16 73.305 213.84 73.575 ;
     RECT  2.16 73.845 213.84 74.115 ;
     RECT  2.16 74.385 213.84 74.655 ;
     RECT  2.16 74.925 213.84 75.195 ;
     RECT  2.16 75.465 213.84 75.735 ;
     RECT  2.16 76.005 213.84 76.275 ;
     RECT  2.16 76.545 213.84 76.815 ;
     RECT  2.16 77.085 213.84 77.355 ;
     RECT  2.16 77.625 213.84 77.895 ;
     RECT  2.16 78.165 213.84 78.435 ;
     RECT  2.16 78.705 213.84 78.975 ;
     RECT  2.16 79.245 213.84 79.515 ;
     RECT  2.16 79.785 213.84 80.055 ;
     RECT  2.16 80.325 213.84 80.595 ;
     RECT  2.16 80.865 213.84 81.135 ;
     RECT  2.16 81.405 213.84 81.675 ;
     RECT  2.16 81.945 213.84 82.215 ;
     RECT  2.16 82.485 213.84 82.755 ;
     RECT  2.16 83.025 213.84 83.295 ;
     RECT  2.16 83.565 213.84 83.835 ;
     RECT  2.16 84.105 213.84 84.24 ;
     RECT  2.16 84.24 58.428 84.375 ;
     RECT  157.356 84.24 213.84 84.375 ;
     RECT  2.16 84.645 58.428 84.915 ;
     RECT  157.356 84.645 213.84 84.915 ;
     RECT  2.16 85.185 58.428 85.455 ;
     RECT  157.356 85.185 213.84 85.455 ;
     RECT  2.16 85.725 58.428 85.995 ;
     RECT  157.356 85.725 213.84 85.995 ;
     RECT  2.16 86.265 58.428 86.535 ;
     RECT  157.356 86.265 213.84 86.535 ;
     RECT  2.16 86.805 58.428 87.075 ;
     RECT  157.356 86.805 213.84 87.075 ;
     RECT  2.16 87.345 58.428 87.615 ;
     RECT  157.356 87.345 213.84 87.615 ;
     RECT  2.16 87.885 58.428 88.155 ;
     RECT  157.356 87.885 213.84 88.155 ;
     RECT  2.16 88.425 58.428 88.695 ;
     RECT  157.356 88.425 213.84 88.695 ;
     RECT  2.16 88.965 58.428 89.235 ;
     RECT  157.356 88.965 213.84 89.235 ;
     RECT  2.16 89.505 58.428 89.775 ;
     RECT  157.356 89.505 213.84 89.775 ;
     RECT  2.16 90.045 58.428 90.315 ;
     RECT  157.356 90.045 213.84 90.315 ;
     RECT  2.16 90.585 58.428 90.855 ;
     RECT  157.356 90.585 213.84 90.855 ;
     RECT  2.16 91.125 58.428 91.395 ;
     RECT  157.356 91.125 213.84 91.395 ;
     RECT  2.16 91.665 58.428 91.935 ;
     RECT  157.356 91.665 213.84 91.935 ;
     RECT  2.16 92.205 58.428 92.475 ;
     RECT  157.356 92.205 213.84 92.475 ;
     RECT  2.16 92.745 58.428 93.015 ;
     RECT  157.356 92.745 213.84 93.015 ;
     RECT  2.16 93.285 58.428 93.555 ;
     RECT  157.356 93.285 213.84 93.555 ;
     RECT  2.16 93.825 58.428 94.095 ;
     RECT  157.356 93.825 213.84 94.095 ;
     RECT  2.16 94.365 58.428 94.635 ;
     RECT  157.356 94.365 213.84 94.635 ;
     RECT  2.16 94.905 58.428 95.175 ;
     RECT  157.356 94.905 213.84 95.175 ;
     RECT  2.16 95.445 58.428 95.715 ;
     RECT  157.356 95.445 213.84 95.715 ;
     RECT  2.16 95.985 58.428 96.255 ;
     RECT  157.356 95.985 213.84 96.255 ;
     RECT  2.16 96.525 58.428 96.795 ;
     RECT  157.356 96.525 213.84 96.795 ;
     RECT  2.16 97.065 58.428 97.335 ;
     RECT  157.356 97.065 213.84 97.335 ;
     RECT  2.16 97.605 58.428 97.875 ;
     RECT  157.356 97.605 213.84 97.875 ;
     RECT  2.16 98.145 58.428 98.415 ;
     RECT  157.356 98.145 213.84 98.415 ;
     RECT  2.16 98.685 58.428 98.955 ;
     RECT  157.356 98.685 213.84 98.955 ;
     RECT  2.16 99.225 58.428 99.495 ;
     RECT  157.356 99.225 213.84 99.495 ;
     RECT  2.16 99.765 58.428 100.035 ;
     RECT  157.356 99.765 213.84 100.035 ;
     RECT  2.16 100.305 58.428 100.575 ;
     RECT  157.356 100.305 213.84 100.575 ;
     RECT  2.16 100.845 58.428 101.115 ;
     RECT  157.356 100.845 213.84 101.115 ;
     RECT  2.16 101.385 58.428 101.655 ;
     RECT  157.356 101.385 213.84 101.655 ;
     RECT  2.16 101.925 58.428 102.195 ;
     RECT  157.356 101.925 213.84 102.195 ;
     RECT  2.16 102.465 58.428 102.735 ;
     RECT  157.356 102.465 213.84 102.735 ;
     RECT  2.16 103.005 58.428 103.275 ;
     RECT  157.356 103.005 213.84 103.275 ;
     RECT  2.16 103.545 58.428 103.815 ;
     RECT  157.356 103.545 213.84 103.815 ;
     RECT  2.16 104.085 58.428 104.355 ;
     RECT  157.356 104.085 213.84 104.355 ;
     RECT  2.16 104.625 58.428 104.895 ;
     RECT  157.356 104.625 213.84 104.895 ;
     RECT  2.16 105.165 58.428 105.435 ;
     RECT  157.356 105.165 213.84 105.435 ;
     RECT  2.16 105.705 58.428 105.975 ;
     RECT  157.356 105.705 213.84 105.975 ;
     RECT  2.16 106.245 58.428 106.515 ;
     RECT  157.356 106.245 213.84 106.515 ;
     RECT  2.16 106.785 58.428 107.055 ;
     RECT  157.356 106.785 213.84 107.055 ;
     RECT  2.16 107.325 58.428 107.595 ;
     RECT  157.356 107.325 213.84 107.595 ;
     RECT  2.16 107.865 58.428 108.135 ;
     RECT  157.356 107.865 213.84 108.135 ;
     RECT  2.16 108.405 58.428 108.675 ;
     RECT  157.356 108.405 213.84 108.675 ;
     RECT  2.16 108.945 58.428 109.215 ;
     RECT  157.356 108.945 213.84 109.215 ;
     RECT  2.16 109.485 58.428 109.755 ;
     RECT  157.356 109.485 213.84 109.755 ;
     RECT  2.16 110.025 58.428 110.295 ;
     RECT  157.356 110.025 213.84 110.295 ;
     RECT  2.16 110.565 58.428 110.835 ;
     RECT  157.356 110.565 213.84 110.835 ;
     RECT  2.16 111.105 58.428 111.375 ;
     RECT  157.356 111.105 213.84 111.375 ;
     RECT  2.16 111.645 58.428 111.915 ;
     RECT  157.356 111.645 213.84 111.915 ;
     RECT  2.16 112.185 58.428 112.455 ;
     RECT  157.356 112.185 213.84 112.455 ;
     RECT  2.16 112.725 58.428 112.995 ;
     RECT  157.356 112.725 213.84 112.995 ;
     RECT  2.16 113.265 58.428 113.535 ;
     RECT  157.356 113.265 213.84 113.535 ;
     RECT  2.16 113.805 58.428 114.075 ;
     RECT  157.356 113.805 213.84 114.075 ;
     RECT  2.16 114.345 58.428 114.615 ;
     RECT  157.356 114.345 213.84 114.615 ;
     RECT  2.16 114.885 58.428 115.155 ;
     RECT  157.356 114.885 213.84 115.155 ;
     RECT  2.16 115.425 58.428 115.695 ;
     RECT  157.356 115.425 213.84 115.695 ;
     RECT  2.16 115.965 58.428 116.235 ;
     RECT  157.356 115.965 213.84 116.235 ;
     RECT  2.16 116.505 58.428 116.775 ;
     RECT  157.356 116.505 213.84 116.775 ;
     RECT  2.16 117.045 58.428 117.315 ;
     RECT  157.356 117.045 213.84 117.315 ;
     RECT  2.16 117.585 58.428 117.855 ;
     RECT  157.356 117.585 213.84 117.855 ;
     RECT  2.16 118.125 58.428 118.395 ;
     RECT  157.356 118.125 213.84 118.395 ;
     RECT  2.16 118.665 58.428 118.935 ;
     RECT  157.356 118.665 213.84 118.935 ;
     RECT  2.16 119.205 58.428 119.475 ;
     RECT  157.356 119.205 213.84 119.475 ;
     RECT  2.16 119.745 58.428 120.015 ;
     RECT  157.356 119.745 213.84 120.015 ;
     RECT  2.16 120.285 58.428 120.555 ;
     RECT  157.356 120.285 213.84 120.555 ;
     RECT  2.16 120.825 58.428 121.095 ;
     RECT  157.356 120.825 213.84 121.095 ;
     RECT  2.16 121.365 58.428 121.635 ;
     RECT  157.356 121.365 213.84 121.635 ;
     RECT  2.16 121.905 58.428 122.175 ;
     RECT  157.356 121.905 213.84 122.175 ;
     RECT  2.16 122.445 58.428 122.715 ;
     RECT  157.356 122.445 213.84 122.715 ;
     RECT  2.16 122.985 58.428 123.255 ;
     RECT  157.356 122.985 213.84 123.255 ;
     RECT  2.16 123.525 58.428 123.795 ;
     RECT  157.356 123.525 213.84 123.795 ;
     RECT  2.16 124.065 58.428 124.335 ;
     RECT  157.356 124.065 213.84 124.335 ;
     RECT  2.16 124.605 58.428 124.875 ;
     RECT  157.356 124.605 213.84 124.875 ;
     RECT  2.16 125.145 58.428 125.415 ;
     RECT  157.356 125.145 213.84 125.415 ;
     RECT  2.16 125.685 58.428 125.955 ;
     RECT  157.356 125.685 213.84 125.955 ;
     RECT  2.16 126.225 58.428 126.495 ;
     RECT  157.356 126.225 213.84 126.495 ;
     RECT  2.16 126.765 58.428 127.035 ;
     RECT  157.356 126.765 213.84 127.035 ;
     RECT  2.16 127.305 58.428 127.575 ;
     RECT  157.356 127.305 213.84 127.575 ;
     RECT  2.16 127.845 58.428 128.115 ;
     RECT  157.356 127.845 213.84 128.115 ;
     RECT  2.16 128.385 58.428 128.655 ;
     RECT  157.356 128.385 213.84 128.655 ;
     RECT  2.16 128.925 58.428 129.195 ;
     RECT  157.356 128.925 213.84 129.195 ;
     RECT  2.16 129.465 58.428 129.6 ;
     RECT  157.356 129.465 213.84 129.6 ;
     RECT  2.16 129.6 213.84 129.735 ;
     RECT  2.16 130.005 213.84 130.275 ;
     RECT  2.16 130.545 213.84 130.815 ;
     RECT  2.16 131.085 213.84 131.355 ;
     RECT  2.16 131.625 213.84 131.895 ;
     RECT  2.16 132.165 213.84 132.435 ;
     RECT  2.16 132.705 213.84 132.975 ;
     RECT  2.16 133.245 213.84 133.515 ;
     RECT  2.16 133.785 213.84 134.055 ;
     RECT  2.16 134.325 213.84 134.595 ;
     RECT  2.16 134.865 213.84 135.135 ;
     RECT  2.16 135.405 213.84 135.675 ;
     RECT  2.16 135.945 213.84 136.215 ;
     RECT  2.16 136.485 213.84 136.755 ;
     RECT  2.16 137.025 213.84 137.295 ;
     RECT  2.16 137.565 213.84 137.835 ;
     RECT  2.16 138.105 213.84 138.375 ;
     RECT  2.16 138.645 213.84 138.915 ;
     RECT  2.16 139.185 213.84 139.455 ;
     RECT  2.16 139.725 213.84 139.995 ;
     RECT  2.16 140.265 213.84 140.535 ;
     RECT  2.16 140.805 213.84 141.075 ;
     RECT  2.16 141.345 213.84 141.615 ;
     RECT  2.16 141.885 213.84 142.155 ;
     RECT  2.16 142.425 213.84 142.695 ;
     RECT  2.16 142.965 213.84 143.235 ;
     RECT  2.16 143.505 213.84 143.775 ;
     RECT  2.16 144.045 213.84 144.315 ;
     RECT  2.16 144.585 213.84 144.855 ;
     RECT  2.16 145.125 213.84 145.395 ;
     RECT  2.16 145.665 213.84 145.935 ;
     RECT  2.16 146.205 213.84 146.475 ;
     RECT  2.16 146.745 213.84 147.015 ;
     RECT  2.16 147.285 213.84 147.555 ;
     RECT  2.16 147.825 213.84 148.095 ;
     RECT  2.16 148.365 213.84 148.635 ;
     RECT  2.16 148.905 213.84 149.04 ;
    LAYER RVTP ;
     RECT  2.16 2.295 213.84 2.565 ;
     RECT  2.16 2.835 213.84 3.105 ;
     RECT  2.16 3.375 213.84 3.645 ;
     RECT  2.16 3.915 213.84 4.185 ;
     RECT  2.16 4.455 213.84 4.725 ;
     RECT  2.16 4.995 213.84 5.265 ;
     RECT  2.16 5.535 213.84 5.805 ;
     RECT  2.16 6.075 213.84 6.345 ;
     RECT  2.16 6.615 213.84 6.885 ;
     RECT  2.16 7.155 213.84 7.425 ;
     RECT  2.16 7.695 213.84 7.965 ;
     RECT  2.16 8.235 213.84 8.505 ;
     RECT  2.16 8.775 213.84 9.045 ;
     RECT  2.16 9.315 213.84 9.585 ;
     RECT  2.16 9.855 213.84 10.125 ;
     RECT  2.16 10.395 213.84 10.665 ;
     RECT  2.16 10.935 213.84 11.205 ;
     RECT  2.16 11.475 213.84 11.745 ;
     RECT  2.16 12.015 213.84 12.285 ;
     RECT  2.16 12.555 213.84 12.825 ;
     RECT  2.16 13.095 213.84 13.365 ;
     RECT  2.16 13.635 213.84 13.905 ;
     RECT  2.16 14.175 213.84 14.445 ;
     RECT  2.16 14.715 213.84 14.985 ;
     RECT  2.16 15.255 213.84 15.525 ;
     RECT  2.16 15.795 213.84 16.065 ;
     RECT  2.16 16.335 213.84 16.605 ;
     RECT  2.16 16.875 213.84 17.145 ;
     RECT  2.16 17.415 213.84 17.685 ;
     RECT  2.16 17.955 213.84 18.225 ;
     RECT  2.16 18.495 213.84 18.765 ;
     RECT  2.16 19.035 213.84 19.305 ;
     RECT  2.16 19.575 213.84 19.845 ;
     RECT  2.16 20.115 213.84 20.385 ;
     RECT  2.16 20.655 213.84 20.925 ;
     RECT  2.16 21.195 213.84 21.465 ;
     RECT  2.16 21.735 58.428 22.005 ;
     RECT  157.356 21.735 213.84 22.005 ;
     RECT  2.16 22.275 58.428 22.545 ;
     RECT  157.356 22.275 213.84 22.545 ;
     RECT  2.16 22.815 58.428 23.085 ;
     RECT  157.356 22.815 213.84 23.085 ;
     RECT  2.16 23.355 58.428 23.625 ;
     RECT  157.356 23.355 213.84 23.625 ;
     RECT  2.16 23.895 58.428 24.165 ;
     RECT  157.356 23.895 213.84 24.165 ;
     RECT  2.16 24.435 58.428 24.705 ;
     RECT  157.356 24.435 213.84 24.705 ;
     RECT  2.16 24.975 58.428 25.245 ;
     RECT  157.356 24.975 213.84 25.245 ;
     RECT  2.16 25.515 58.428 25.785 ;
     RECT  157.356 25.515 213.84 25.785 ;
     RECT  2.16 26.055 58.428 26.325 ;
     RECT  157.356 26.055 213.84 26.325 ;
     RECT  2.16 26.595 58.428 26.865 ;
     RECT  157.356 26.595 213.84 26.865 ;
     RECT  2.16 27.135 58.428 27.405 ;
     RECT  157.356 27.135 213.84 27.405 ;
     RECT  2.16 27.675 58.428 27.945 ;
     RECT  157.356 27.675 213.84 27.945 ;
     RECT  2.16 28.215 58.428 28.485 ;
     RECT  157.356 28.215 213.84 28.485 ;
     RECT  2.16 28.755 58.428 29.025 ;
     RECT  157.356 28.755 213.84 29.025 ;
     RECT  2.16 29.295 58.428 29.565 ;
     RECT  157.356 29.295 213.84 29.565 ;
     RECT  2.16 29.835 58.428 30.105 ;
     RECT  157.356 29.835 213.84 30.105 ;
     RECT  2.16 30.375 58.428 30.645 ;
     RECT  157.356 30.375 213.84 30.645 ;
     RECT  2.16 30.915 58.428 31.185 ;
     RECT  157.356 30.915 213.84 31.185 ;
     RECT  2.16 31.455 58.428 31.725 ;
     RECT  157.356 31.455 213.84 31.725 ;
     RECT  2.16 31.995 58.428 32.265 ;
     RECT  157.356 31.995 213.84 32.265 ;
     RECT  2.16 32.535 58.428 32.805 ;
     RECT  157.356 32.535 213.84 32.805 ;
     RECT  2.16 33.075 58.428 33.345 ;
     RECT  157.356 33.075 213.84 33.345 ;
     RECT  2.16 33.615 58.428 33.885 ;
     RECT  157.356 33.615 213.84 33.885 ;
     RECT  2.16 34.155 58.428 34.425 ;
     RECT  157.356 34.155 213.84 34.425 ;
     RECT  2.16 34.695 58.428 34.965 ;
     RECT  157.356 34.695 213.84 34.965 ;
     RECT  2.16 35.235 58.428 35.505 ;
     RECT  157.356 35.235 213.84 35.505 ;
     RECT  2.16 35.775 58.428 36.045 ;
     RECT  157.356 35.775 213.84 36.045 ;
     RECT  2.16 36.315 58.428 36.585 ;
     RECT  157.356 36.315 213.84 36.585 ;
     RECT  2.16 36.855 58.428 37.125 ;
     RECT  157.356 36.855 213.84 37.125 ;
     RECT  2.16 37.395 58.428 37.665 ;
     RECT  157.356 37.395 213.84 37.665 ;
     RECT  2.16 37.935 58.428 38.205 ;
     RECT  157.356 37.935 213.84 38.205 ;
     RECT  2.16 38.475 58.428 38.745 ;
     RECT  157.356 38.475 213.84 38.745 ;
     RECT  2.16 39.015 58.428 39.285 ;
     RECT  157.356 39.015 213.84 39.285 ;
     RECT  2.16 39.555 58.428 39.825 ;
     RECT  157.356 39.555 213.84 39.825 ;
     RECT  2.16 40.095 58.428 40.365 ;
     RECT  157.356 40.095 213.84 40.365 ;
     RECT  2.16 40.635 58.428 40.905 ;
     RECT  157.356 40.635 213.84 40.905 ;
     RECT  2.16 41.175 58.428 41.445 ;
     RECT  157.356 41.175 213.84 41.445 ;
     RECT  2.16 41.715 58.428 41.985 ;
     RECT  157.356 41.715 213.84 41.985 ;
     RECT  2.16 42.255 58.428 42.525 ;
     RECT  157.356 42.255 213.84 42.525 ;
     RECT  2.16 42.795 58.428 43.065 ;
     RECT  157.356 42.795 213.84 43.065 ;
     RECT  2.16 43.335 58.428 43.605 ;
     RECT  157.356 43.335 213.84 43.605 ;
     RECT  2.16 43.875 58.428 44.145 ;
     RECT  157.356 43.875 213.84 44.145 ;
     RECT  2.16 44.415 58.428 44.685 ;
     RECT  157.356 44.415 213.84 44.685 ;
     RECT  2.16 44.955 58.428 45.225 ;
     RECT  157.356 44.955 213.84 45.225 ;
     RECT  2.16 45.495 58.428 45.765 ;
     RECT  157.356 45.495 213.84 45.765 ;
     RECT  2.16 46.035 58.428 46.305 ;
     RECT  157.356 46.035 213.84 46.305 ;
     RECT  2.16 46.575 58.428 46.845 ;
     RECT  157.356 46.575 213.84 46.845 ;
     RECT  2.16 47.115 58.428 47.385 ;
     RECT  157.356 47.115 213.84 47.385 ;
     RECT  2.16 47.655 58.428 47.925 ;
     RECT  157.356 47.655 213.84 47.925 ;
     RECT  2.16 48.195 58.428 48.465 ;
     RECT  157.356 48.195 213.84 48.465 ;
     RECT  2.16 48.735 58.428 49.005 ;
     RECT  157.356 48.735 213.84 49.005 ;
     RECT  2.16 49.275 58.428 49.545 ;
     RECT  157.356 49.275 213.84 49.545 ;
     RECT  2.16 49.815 58.428 50.085 ;
     RECT  157.356 49.815 213.84 50.085 ;
     RECT  2.16 50.355 58.428 50.625 ;
     RECT  157.356 50.355 213.84 50.625 ;
     RECT  2.16 50.895 58.428 51.165 ;
     RECT  157.356 50.895 213.84 51.165 ;
     RECT  2.16 51.435 58.428 51.705 ;
     RECT  157.356 51.435 213.84 51.705 ;
     RECT  2.16 51.975 58.428 52.245 ;
     RECT  157.356 51.975 213.84 52.245 ;
     RECT  2.16 52.515 58.428 52.785 ;
     RECT  157.356 52.515 213.84 52.785 ;
     RECT  2.16 53.055 58.428 53.325 ;
     RECT  157.356 53.055 213.84 53.325 ;
     RECT  2.16 53.595 58.428 53.865 ;
     RECT  157.356 53.595 213.84 53.865 ;
     RECT  2.16 54.135 58.428 54.405 ;
     RECT  157.356 54.135 213.84 54.405 ;
     RECT  2.16 54.675 58.428 54.945 ;
     RECT  157.356 54.675 213.84 54.945 ;
     RECT  2.16 55.215 58.428 55.485 ;
     RECT  157.356 55.215 213.84 55.485 ;
     RECT  2.16 55.755 58.428 56.025 ;
     RECT  157.356 55.755 213.84 56.025 ;
     RECT  2.16 56.295 58.428 56.565 ;
     RECT  157.356 56.295 213.84 56.565 ;
     RECT  2.16 56.835 58.428 57.105 ;
     RECT  157.356 56.835 213.84 57.105 ;
     RECT  2.16 57.375 58.428 57.645 ;
     RECT  157.356 57.375 213.84 57.645 ;
     RECT  2.16 57.915 58.428 58.185 ;
     RECT  157.356 57.915 213.84 58.185 ;
     RECT  2.16 58.455 58.428 58.725 ;
     RECT  157.356 58.455 213.84 58.725 ;
     RECT  2.16 58.995 58.428 59.265 ;
     RECT  157.356 58.995 213.84 59.265 ;
     RECT  2.16 59.535 58.428 59.805 ;
     RECT  157.356 59.535 213.84 59.805 ;
     RECT  2.16 60.075 58.428 60.345 ;
     RECT  157.356 60.075 213.84 60.345 ;
     RECT  2.16 60.615 58.428 60.885 ;
     RECT  157.356 60.615 213.84 60.885 ;
     RECT  2.16 61.155 58.428 61.425 ;
     RECT  157.356 61.155 213.84 61.425 ;
     RECT  2.16 61.695 58.428 61.965 ;
     RECT  157.356 61.695 213.84 61.965 ;
     RECT  2.16 62.235 58.428 62.505 ;
     RECT  157.356 62.235 213.84 62.505 ;
     RECT  2.16 62.775 58.428 63.045 ;
     RECT  157.356 62.775 213.84 63.045 ;
     RECT  2.16 63.315 58.428 63.585 ;
     RECT  157.356 63.315 213.84 63.585 ;
     RECT  2.16 63.855 58.428 64.125 ;
     RECT  157.356 63.855 213.84 64.125 ;
     RECT  2.16 64.395 58.428 64.665 ;
     RECT  157.356 64.395 213.84 64.665 ;
     RECT  2.16 64.935 58.428 65.205 ;
     RECT  157.356 64.935 213.84 65.205 ;
     RECT  2.16 65.475 58.428 65.745 ;
     RECT  157.356 65.475 213.84 65.745 ;
     RECT  2.16 66.015 58.428 66.285 ;
     RECT  157.356 66.015 213.84 66.285 ;
     RECT  2.16 66.555 58.428 66.825 ;
     RECT  157.356 66.555 213.84 66.825 ;
     RECT  2.16 67.095 213.84 67.365 ;
     RECT  2.16 67.635 213.84 67.905 ;
     RECT  2.16 68.175 213.84 68.445 ;
     RECT  2.16 68.715 213.84 68.985 ;
     RECT  2.16 69.255 213.84 69.525 ;
     RECT  2.16 69.795 213.84 70.065 ;
     RECT  2.16 70.335 213.84 70.605 ;
     RECT  2.16 70.875 213.84 71.145 ;
     RECT  2.16 71.415 213.84 71.685 ;
     RECT  2.16 71.955 213.84 72.225 ;
     RECT  2.16 72.495 213.84 72.765 ;
     RECT  2.16 73.035 213.84 73.305 ;
     RECT  2.16 73.575 213.84 73.845 ;
     RECT  2.16 74.115 213.84 74.385 ;
     RECT  2.16 74.655 213.84 74.925 ;
     RECT  2.16 75.195 213.84 75.465 ;
     RECT  2.16 75.735 213.84 76.005 ;
     RECT  2.16 76.275 213.84 76.545 ;
     RECT  2.16 76.815 213.84 77.085 ;
     RECT  2.16 77.355 213.84 77.625 ;
     RECT  2.16 77.895 213.84 78.165 ;
     RECT  2.16 78.435 213.84 78.705 ;
     RECT  2.16 78.975 213.84 79.245 ;
     RECT  2.16 79.515 213.84 79.785 ;
     RECT  2.16 80.055 213.84 80.325 ;
     RECT  2.16 80.595 213.84 80.865 ;
     RECT  2.16 81.135 213.84 81.405 ;
     RECT  2.16 81.675 213.84 81.945 ;
     RECT  2.16 82.215 213.84 82.485 ;
     RECT  2.16 82.755 213.84 83.025 ;
     RECT  2.16 83.295 213.84 83.565 ;
     RECT  2.16 83.835 213.84 84.105 ;
     RECT  2.16 84.375 58.428 84.645 ;
     RECT  157.356 84.375 213.84 84.645 ;
     RECT  2.16 84.915 58.428 85.185 ;
     RECT  157.356 84.915 213.84 85.185 ;
     RECT  2.16 85.455 58.428 85.725 ;
     RECT  157.356 85.455 213.84 85.725 ;
     RECT  2.16 85.995 58.428 86.265 ;
     RECT  157.356 85.995 213.84 86.265 ;
     RECT  2.16 86.535 58.428 86.805 ;
     RECT  157.356 86.535 213.84 86.805 ;
     RECT  2.16 87.075 58.428 87.345 ;
     RECT  157.356 87.075 213.84 87.345 ;
     RECT  2.16 87.615 58.428 87.885 ;
     RECT  157.356 87.615 213.84 87.885 ;
     RECT  2.16 88.155 58.428 88.425 ;
     RECT  157.356 88.155 213.84 88.425 ;
     RECT  2.16 88.695 58.428 88.965 ;
     RECT  157.356 88.695 213.84 88.965 ;
     RECT  2.16 89.235 58.428 89.505 ;
     RECT  157.356 89.235 213.84 89.505 ;
     RECT  2.16 89.775 58.428 90.045 ;
     RECT  157.356 89.775 213.84 90.045 ;
     RECT  2.16 90.315 58.428 90.585 ;
     RECT  157.356 90.315 213.84 90.585 ;
     RECT  2.16 90.855 58.428 91.125 ;
     RECT  157.356 90.855 213.84 91.125 ;
     RECT  2.16 91.395 58.428 91.665 ;
     RECT  157.356 91.395 213.84 91.665 ;
     RECT  2.16 91.935 58.428 92.205 ;
     RECT  157.356 91.935 213.84 92.205 ;
     RECT  2.16 92.475 58.428 92.745 ;
     RECT  157.356 92.475 213.84 92.745 ;
     RECT  2.16 93.015 58.428 93.285 ;
     RECT  157.356 93.015 213.84 93.285 ;
     RECT  2.16 93.555 58.428 93.825 ;
     RECT  157.356 93.555 213.84 93.825 ;
     RECT  2.16 94.095 58.428 94.365 ;
     RECT  157.356 94.095 213.84 94.365 ;
     RECT  2.16 94.635 58.428 94.905 ;
     RECT  157.356 94.635 213.84 94.905 ;
     RECT  2.16 95.175 58.428 95.445 ;
     RECT  157.356 95.175 213.84 95.445 ;
     RECT  2.16 95.715 58.428 95.985 ;
     RECT  157.356 95.715 213.84 95.985 ;
     RECT  2.16 96.255 58.428 96.525 ;
     RECT  157.356 96.255 213.84 96.525 ;
     RECT  2.16 96.795 58.428 97.065 ;
     RECT  157.356 96.795 213.84 97.065 ;
     RECT  2.16 97.335 58.428 97.605 ;
     RECT  157.356 97.335 213.84 97.605 ;
     RECT  2.16 97.875 58.428 98.145 ;
     RECT  157.356 97.875 213.84 98.145 ;
     RECT  2.16 98.415 58.428 98.685 ;
     RECT  157.356 98.415 213.84 98.685 ;
     RECT  2.16 98.955 58.428 99.225 ;
     RECT  157.356 98.955 213.84 99.225 ;
     RECT  2.16 99.495 58.428 99.765 ;
     RECT  157.356 99.495 213.84 99.765 ;
     RECT  2.16 100.035 58.428 100.305 ;
     RECT  157.356 100.035 213.84 100.305 ;
     RECT  2.16 100.575 58.428 100.845 ;
     RECT  157.356 100.575 213.84 100.845 ;
     RECT  2.16 101.115 58.428 101.385 ;
     RECT  157.356 101.115 213.84 101.385 ;
     RECT  2.16 101.655 58.428 101.925 ;
     RECT  157.356 101.655 213.84 101.925 ;
     RECT  2.16 102.195 58.428 102.465 ;
     RECT  157.356 102.195 213.84 102.465 ;
     RECT  2.16 102.735 58.428 103.005 ;
     RECT  157.356 102.735 213.84 103.005 ;
     RECT  2.16 103.275 58.428 103.545 ;
     RECT  157.356 103.275 213.84 103.545 ;
     RECT  2.16 103.815 58.428 104.085 ;
     RECT  157.356 103.815 213.84 104.085 ;
     RECT  2.16 104.355 58.428 104.625 ;
     RECT  157.356 104.355 213.84 104.625 ;
     RECT  2.16 104.895 58.428 105.165 ;
     RECT  157.356 104.895 213.84 105.165 ;
     RECT  2.16 105.435 58.428 105.705 ;
     RECT  157.356 105.435 213.84 105.705 ;
     RECT  2.16 105.975 58.428 106.245 ;
     RECT  157.356 105.975 213.84 106.245 ;
     RECT  2.16 106.515 58.428 106.785 ;
     RECT  157.356 106.515 213.84 106.785 ;
     RECT  2.16 107.055 58.428 107.325 ;
     RECT  157.356 107.055 213.84 107.325 ;
     RECT  2.16 107.595 58.428 107.865 ;
     RECT  157.356 107.595 213.84 107.865 ;
     RECT  2.16 108.135 58.428 108.405 ;
     RECT  157.356 108.135 213.84 108.405 ;
     RECT  2.16 108.675 58.428 108.945 ;
     RECT  157.356 108.675 213.84 108.945 ;
     RECT  2.16 109.215 58.428 109.485 ;
     RECT  157.356 109.215 213.84 109.485 ;
     RECT  2.16 109.755 58.428 110.025 ;
     RECT  157.356 109.755 213.84 110.025 ;
     RECT  2.16 110.295 58.428 110.565 ;
     RECT  157.356 110.295 213.84 110.565 ;
     RECT  2.16 110.835 58.428 111.105 ;
     RECT  157.356 110.835 213.84 111.105 ;
     RECT  2.16 111.375 58.428 111.645 ;
     RECT  157.356 111.375 213.84 111.645 ;
     RECT  2.16 111.915 58.428 112.185 ;
     RECT  157.356 111.915 213.84 112.185 ;
     RECT  2.16 112.455 58.428 112.725 ;
     RECT  157.356 112.455 213.84 112.725 ;
     RECT  2.16 112.995 58.428 113.265 ;
     RECT  157.356 112.995 213.84 113.265 ;
     RECT  2.16 113.535 58.428 113.805 ;
     RECT  157.356 113.535 213.84 113.805 ;
     RECT  2.16 114.075 58.428 114.345 ;
     RECT  157.356 114.075 213.84 114.345 ;
     RECT  2.16 114.615 58.428 114.885 ;
     RECT  157.356 114.615 213.84 114.885 ;
     RECT  2.16 115.155 58.428 115.425 ;
     RECT  157.356 115.155 213.84 115.425 ;
     RECT  2.16 115.695 58.428 115.965 ;
     RECT  157.356 115.695 213.84 115.965 ;
     RECT  2.16 116.235 58.428 116.505 ;
     RECT  157.356 116.235 213.84 116.505 ;
     RECT  2.16 116.775 58.428 117.045 ;
     RECT  157.356 116.775 213.84 117.045 ;
     RECT  2.16 117.315 58.428 117.585 ;
     RECT  157.356 117.315 213.84 117.585 ;
     RECT  2.16 117.855 58.428 118.125 ;
     RECT  157.356 117.855 213.84 118.125 ;
     RECT  2.16 118.395 58.428 118.665 ;
     RECT  157.356 118.395 213.84 118.665 ;
     RECT  2.16 118.935 58.428 119.205 ;
     RECT  157.356 118.935 213.84 119.205 ;
     RECT  2.16 119.475 58.428 119.745 ;
     RECT  157.356 119.475 213.84 119.745 ;
     RECT  2.16 120.015 58.428 120.285 ;
     RECT  157.356 120.015 213.84 120.285 ;
     RECT  2.16 120.555 58.428 120.825 ;
     RECT  157.356 120.555 213.84 120.825 ;
     RECT  2.16 121.095 58.428 121.365 ;
     RECT  157.356 121.095 213.84 121.365 ;
     RECT  2.16 121.635 58.428 121.905 ;
     RECT  157.356 121.635 213.84 121.905 ;
     RECT  2.16 122.175 58.428 122.445 ;
     RECT  157.356 122.175 213.84 122.445 ;
     RECT  2.16 122.715 58.428 122.985 ;
     RECT  157.356 122.715 213.84 122.985 ;
     RECT  2.16 123.255 58.428 123.525 ;
     RECT  157.356 123.255 213.84 123.525 ;
     RECT  2.16 123.795 58.428 124.065 ;
     RECT  157.356 123.795 213.84 124.065 ;
     RECT  2.16 124.335 58.428 124.605 ;
     RECT  157.356 124.335 213.84 124.605 ;
     RECT  2.16 124.875 58.428 125.145 ;
     RECT  157.356 124.875 213.84 125.145 ;
     RECT  2.16 125.415 58.428 125.685 ;
     RECT  157.356 125.415 213.84 125.685 ;
     RECT  2.16 125.955 58.428 126.225 ;
     RECT  157.356 125.955 213.84 126.225 ;
     RECT  2.16 126.495 58.428 126.765 ;
     RECT  157.356 126.495 213.84 126.765 ;
     RECT  2.16 127.035 58.428 127.305 ;
     RECT  157.356 127.035 213.84 127.305 ;
     RECT  2.16 127.575 58.428 127.845 ;
     RECT  157.356 127.575 213.84 127.845 ;
     RECT  2.16 128.115 58.428 128.385 ;
     RECT  157.356 128.115 213.84 128.385 ;
     RECT  2.16 128.655 58.428 128.925 ;
     RECT  157.356 128.655 213.84 128.925 ;
     RECT  2.16 129.195 58.428 129.465 ;
     RECT  157.356 129.195 213.84 129.465 ;
     RECT  2.16 129.735 213.84 130.005 ;
     RECT  2.16 130.275 213.84 130.545 ;
     RECT  2.16 130.815 213.84 131.085 ;
     RECT  2.16 131.355 213.84 131.625 ;
     RECT  2.16 131.895 213.84 132.165 ;
     RECT  2.16 132.435 213.84 132.705 ;
     RECT  2.16 132.975 213.84 133.245 ;
     RECT  2.16 133.515 213.84 133.785 ;
     RECT  2.16 134.055 213.84 134.325 ;
     RECT  2.16 134.595 213.84 134.865 ;
     RECT  2.16 135.135 213.84 135.405 ;
     RECT  2.16 135.675 213.84 135.945 ;
     RECT  2.16 136.215 213.84 136.485 ;
     RECT  2.16 136.755 213.84 137.025 ;
     RECT  2.16 137.295 213.84 137.565 ;
     RECT  2.16 137.835 213.84 138.105 ;
     RECT  2.16 138.375 213.84 138.645 ;
     RECT  2.16 138.915 213.84 139.185 ;
     RECT  2.16 139.455 213.84 139.725 ;
     RECT  2.16 139.995 213.84 140.265 ;
     RECT  2.16 140.535 213.84 140.805 ;
     RECT  2.16 141.075 213.84 141.345 ;
     RECT  2.16 141.615 213.84 141.885 ;
     RECT  2.16 142.155 213.84 142.425 ;
     RECT  2.16 142.695 213.84 142.965 ;
     RECT  2.16 143.235 213.84 143.505 ;
     RECT  2.16 143.775 213.84 144.045 ;
     RECT  2.16 144.315 213.84 144.585 ;
     RECT  2.16 144.855 213.84 145.125 ;
     RECT  2.16 145.395 213.84 145.665 ;
     RECT  2.16 145.935 213.84 146.205 ;
     RECT  2.16 146.475 213.84 146.745 ;
     RECT  2.16 147.015 213.84 147.285 ;
     RECT  2.16 147.555 213.84 147.825 ;
     RECT  2.16 148.095 213.84 148.365 ;
     RECT  2.16 148.635 213.84 148.905 ;
    LAYER M1 ;
     RECT  2.16 2.151 213.84 21.609 ;
     RECT  60.48 23.76 155.304 64.8 ;
     RECT  2.16 21.609 58.428 66.951 ;
     RECT  157.356 21.609 213.84 66.951 ;
     RECT  2.16 66.951 213.84 84.249 ;
     RECT  60.48 86.4 155.304 127.44 ;
     RECT  2.16 84.249 58.428 129.591 ;
     RECT  157.356 84.249 213.84 129.591 ;
     RECT  2.16 129.591 213.84 149.049 ;
    LAYER M2 ;
     RECT  0.103 77.67 0.139 77.688 ;
     RECT  0.103 78.48 0.211 80.046 ;
     RECT  0.211 78.48 0.535 80.352 ;
     RECT  0.103 81.18 0.535 81.198 ;
     RECT  0.103 82.422 0.535 83.088 ;
     RECT  0.103 84.078 0.535 86.76 ;
     RECT  0.535 78.48 1.147 86.76 ;
     RECT  1.147 78.48 1.291 87.3 ;
     RECT  1.291 78.48 1.363 87.372 ;
     RECT  0.103 89.982 1.723 90 ;
     RECT  0.139 77.058 2.16 77.688 ;
     RECT  1.363 78.48 2.16 87.678 ;
     RECT  1.723 89.478 2.16 90 ;
     RECT  2.16 2.151 58.428 149.049 ;
     RECT  58.428 64.836 58.631 87.408 ;
     RECT  58.428 62.856 58.667 62.874 ;
     RECT  58.428 26.028 58.703 49.806 ;
     RECT  58.428 88.938 58.703 91.152 ;
     RECT  58.703 26.028 58.739 49.464 ;
     RECT  58.428 115.938 59.099 116.496 ;
     RECT  58.428 54.612 59.135 54.63 ;
     RECT  59.099 115.938 59.171 115.956 ;
     RECT  58.739 26.028 59.315 47.61 ;
     RECT  58.428 98.46 59.315 99.18 ;
     RECT  58.428 100.278 59.315 105.354 ;
     RECT  58.428 106.146 59.315 109.71 ;
     RECT  59.315 26.028 59.351 43.398 ;
     RECT  59.315 104.634 59.351 105.354 ;
     RECT  59.315 106.218 59.351 109.71 ;
     RECT  58.428 91.98 59.359 96.21 ;
     RECT  58.428 97.236 59.359 97.326 ;
     RECT  59.315 44.154 59.387 47.484 ;
     RECT  59.323 112.806 59.423 112.824 ;
     RECT  58.428 61.011 59.431 61.029 ;
     RECT  59.359 91.98 59.431 97.326 ;
     RECT  58.703 88.974 59.503 91.08 ;
     RECT  59.315 98.46 59.531 98.478 ;
     RECT  58.739 48.708 59.603 49.464 ;
     RECT  59.431 91.98 59.603 97.524 ;
     RECT  59.351 104.796 59.603 105.354 ;
     RECT  59.503 88.668 59.639 91.08 ;
     RECT  59.431 61.011 59.647 61.11 ;
     RECT  59.575 63.936 59.863 63.954 ;
     RECT  58.631 64.836 59.863 86.526 ;
     RECT  58.631 87.39 59.863 87.408 ;
     RECT  59.647 61.011 60.043 61.146 ;
     RECT  59.639 88.74 60.115 91.08 ;
     RECT  60.151 58.356 60.223 58.374 ;
     RECT  60.115 113.04 60.223 113.058 ;
     RECT  60.223 112.968 60.259 113.058 ;
     RECT  60.259 112.968 60.295 113.76 ;
     RECT  60.223 120.834 60.295 120.852 ;
     RECT  59.863 52.956 60.331 52.974 ;
     RECT  60.043 25.101 60.48 25.119 ;
     RECT  59.351 26.028 60.48 42.624 ;
     RECT  59.351 43.38 60.48 43.398 ;
     RECT  59.387 44.154 60.48 47.304 ;
     RECT  59.603 48.708 60.48 48.726 ;
     RECT  59.863 51.066 60.48 51.084 ;
     RECT  60.331 52.956 60.48 53.046 ;
     RECT  59.863 54.036 60.48 54.054 ;
     RECT  60.187 55.458 60.48 55.476 ;
     RECT  60.331 56.421 60.48 56.439 ;
     RECT  60.223 58.356 60.48 58.752 ;
     RECT  60.043 61.011 60.48 61.65 ;
     RECT  60.223 62.712 60.48 62.73 ;
     RECT  59.863 63.666 60.48 63.954 ;
     RECT  59.863 64.836 60.48 87.408 ;
     RECT  60.115 88.74 60.48 91.152 ;
     RECT  59.603 91.98 60.48 97.434 ;
     RECT  59.315 100.701 60.48 103.734 ;
     RECT  59.603 105.102 60.48 105.354 ;
     RECT  59.351 106.452 60.48 109.71 ;
     RECT  60.295 112.896 60.48 113.76 ;
     RECT  60.259 114.624 60.48 114.642 ;
     RECT  60.295 120.834 60.48 120.924 ;
     RECT  59.863 124.686 60.48 124.974 ;
     RECT  60.48 23.76 64.535 127.44 ;
     RECT  64.535 65.826 65.075 127.44 ;
     RECT  65.075 66.456 70.835 127.44 ;
     RECT  70.835 66.564 72.355 127.44 ;
     RECT  72.355 66.492 83.255 127.44 ;
     RECT  83.255 66.528 87.611 127.44 ;
     RECT  87.611 66.681 87.827 127.44 ;
     RECT  87.827 66.951 100.751 127.44 ;
     RECT  100.751 66.951 101.831 84.978 ;
     RECT  100.751 85.77 109.571 127.44 ;
     RECT  101.831 66.951 109.643 84.402 ;
     RECT  109.571 85.806 110.363 127.44 ;
     RECT  110.363 86.4 154.579 127.44 ;
     RECT  154.579 86.076 155.155 127.44 ;
     RECT  155.155 85.806 155.191 127.44 ;
     RECT  155.191 85.734 155.227 127.44 ;
     RECT  64.535 23.76 155.304 64.8 ;
     RECT  155.227 85.662 155.304 127.44 ;
     RECT  155.304 64.746 155.335 64.8 ;
     RECT  155.304 87.624 155.435 88.92 ;
     RECT  155.335 64.746 155.443 64.854 ;
     RECT  155.304 85.662 155.443 86.094 ;
     RECT  155.304 58.77 155.471 58.869 ;
     RECT  155.304 90.441 155.471 90.54 ;
     RECT  155.304 94.176 155.471 94.626 ;
     RECT  109.643 66.951 155.479 84.249 ;
     RECT  155.443 85.581 155.479 86.094 ;
     RECT  155.471 90.522 155.507 90.54 ;
     RECT  155.443 64.746 155.515 64.89 ;
     RECT  155.304 30.186 155.579 30.204 ;
     RECT  155.304 50.751 155.615 50.769 ;
     RECT  155.304 54.486 155.615 54.594 ;
     RECT  155.471 58.851 155.615 58.869 ;
     RECT  155.304 61.281 155.615 61.299 ;
     RECT  155.435 87.93 155.795 88.92 ;
     RECT  155.795 88.506 155.903 88.92 ;
     RECT  155.903 88.668 156.011 88.92 ;
     RECT  155.515 64.746 156.047 64.962 ;
     RECT  156.011 88.668 156.047 88.839 ;
     RECT  156.047 88.821 156.083 88.839 ;
     RECT  155.471 94.176 156.119 94.194 ;
     RECT  155.304 123.3 156.199 126.414 ;
     RECT  155.479 85.5 156.227 86.094 ;
     RECT  156.227 85.581 156.371 86.094 ;
     RECT  155.304 122.526 156.739 122.544 ;
     RECT  156.199 123.3 156.739 126.954 ;
     RECT  157.171 58.734 157.279 58.752 ;
     RECT  155.304 59.742 157.279 59.76 ;
     RECT  58.428 2.151 157.356 21.609 ;
     RECT  155.615 54.486 157.356 54.504 ;
     RECT  155.304 55.656 157.356 55.674 ;
     RECT  157.279 58.734 157.356 59.76 ;
     RECT  157.171 60.786 157.356 60.804 ;
     RECT  156.739 62.712 157.356 62.73 ;
     RECT  156.047 64.746 157.356 64.926 ;
     RECT  155.479 66.222 157.356 84.249 ;
     RECT  156.371 85.581 157.356 85.752 ;
     RECT  157.135 86.616 157.356 86.634 ;
     RECT  156.739 122.526 157.356 126.954 ;
     RECT  58.428 129.591 157.356 149.049 ;
     RECT  157.356 2.151 213.84 149.049 ;
     RECT  213.84 69.156 214.295 78.894 ;
     RECT  214.295 69.156 214.331 71.406 ;
     RECT  214.295 72.198 214.331 78.894 ;
     RECT  213.84 67.608 214.367 68.274 ;
     RECT  214.331 69.156 214.403 71.136 ;
     RECT  214.331 75.276 214.763 78.534 ;
     RECT  214.403 69.156 214.799 70.794 ;
     RECT  214.763 75.906 214.799 78.084 ;
     RECT  214.799 69.156 214.871 70.02 ;
     RECT  214.331 72.198 214.871 74.376 ;
     RECT  214.799 75.906 214.871 77.886 ;
     RECT  214.367 67.806 214.907 68.274 ;
     RECT  214.799 70.776 214.907 70.794 ;
     RECT  214.871 72.198 214.907 72.864 ;
     RECT  214.907 68.256 214.943 68.274 ;
     RECT  214.871 75.906 215.735 76.734 ;
     RECT  215.735 75.906 215.807 75.924 ;
     RECT  214.871 69.498 215.843 70.02 ;
     RECT  214.871 77.526 215.843 77.886 ;
     RECT  214.871 73.62 215.851 73.872 ;
     RECT  215.843 69.498 215.879 69.516 ;
     RECT  215.779 75.051 215.879 75.069 ;
     RECT  215.735 76.716 215.879 76.734 ;
     RECT  214.907 72.198 215.915 72.558 ;
     RECT  215.851 73.62 215.915 73.908 ;
     RECT  215.843 77.526 215.915 77.814 ;
     RECT  215.915 73.89 215.987 73.908 ;
     RECT  215.915 77.796 215.987 77.814 ;
    LAYER M3 ;
     RECT  2.415 2.143 2.505 2.413 ;
     RECT  7.815 2.143 7.905 2.413 ;
     RECT  13.215 2.143 13.305 2.413 ;
     RECT  18.615 2.143 18.705 2.413 ;
     RECT  24.015 2.143 24.105 2.413 ;
     RECT  29.415 2.143 29.505 2.413 ;
     RECT  34.815 2.143 34.905 2.413 ;
     RECT  40.215 2.143 40.305 2.413 ;
     RECT  45.615 2.143 45.705 2.413 ;
     RECT  51.015 2.143 51.105 2.413 ;
     RECT  56.415 2.143 56.505 2.413 ;
     RECT  61.815 2.143 61.905 2.413 ;
     RECT  67.215 2.143 67.305 2.413 ;
     RECT  72.615 2.143 72.705 2.413 ;
     RECT  78.015 2.143 78.105 2.413 ;
     RECT  83.415 2.143 83.505 2.413 ;
     RECT  88.815 2.143 88.905 2.413 ;
     RECT  94.215 2.143 94.305 2.413 ;
     RECT  99.615 2.143 99.705 2.413 ;
     RECT  105.015 2.143 105.105 2.413 ;
     RECT  110.415 2.143 110.505 2.413 ;
     RECT  115.815 2.143 115.905 2.413 ;
     RECT  121.215 2.143 121.305 2.413 ;
     RECT  126.615 2.143 126.705 2.413 ;
     RECT  132.015 2.143 132.105 2.413 ;
     RECT  137.415 2.143 137.505 2.413 ;
     RECT  142.815 2.143 142.905 2.413 ;
     RECT  148.215 2.143 148.305 2.413 ;
     RECT  153.615 2.143 153.705 2.413 ;
     RECT  159.015 2.143 159.105 2.413 ;
     RECT  164.415 2.143 164.505 2.413 ;
     RECT  169.815 2.143 169.905 2.413 ;
     RECT  175.215 2.143 175.305 2.413 ;
     RECT  180.615 2.143 180.705 2.413 ;
     RECT  186.015 2.143 186.105 2.413 ;
     RECT  191.415 2.143 191.505 2.413 ;
     RECT  196.815 2.143 196.905 2.413 ;
     RECT  202.215 2.143 202.305 2.413 ;
     RECT  207.615 2.143 207.705 2.413 ;
     RECT  213.015 2.143 213.105 2.413 ;
     RECT  61.815 2.413 62.097 21.347 ;
     RECT  67.215 2.413 67.497 21.347 ;
     RECT  72.615 2.413 72.897 21.347 ;
     RECT  78.015 2.413 78.297 21.347 ;
     RECT  83.415 2.413 83.697 21.347 ;
     RECT  88.815 2.413 89.097 21.347 ;
     RECT  94.215 2.413 94.497 21.347 ;
     RECT  99.615 2.413 99.897 21.347 ;
     RECT  105.015 2.413 105.297 21.347 ;
     RECT  110.415 2.413 110.697 21.347 ;
     RECT  115.815 2.413 116.097 21.347 ;
     RECT  121.215 2.413 121.497 21.347 ;
     RECT  126.615 2.413 126.897 21.347 ;
     RECT  132.015 2.413 132.297 21.347 ;
     RECT  137.415 2.413 137.697 21.347 ;
     RECT  142.815 2.413 143.097 21.347 ;
     RECT  148.215 2.413 148.497 21.347 ;
     RECT  153.615 2.413 153.897 21.347 ;
     RECT  61.815 21.347 61.905 21.617 ;
     RECT  67.215 21.347 67.305 21.617 ;
     RECT  72.615 21.347 72.705 21.617 ;
     RECT  78.015 21.347 78.105 21.617 ;
     RECT  83.415 21.347 83.505 21.617 ;
     RECT  88.815 21.347 88.905 21.617 ;
     RECT  94.215 21.347 94.305 21.617 ;
     RECT  99.615 21.347 99.705 21.617 ;
     RECT  105.015 21.347 105.105 21.617 ;
     RECT  110.415 21.347 110.505 21.617 ;
     RECT  115.815 21.347 115.905 21.617 ;
     RECT  121.215 21.347 121.305 21.617 ;
     RECT  126.615 21.347 126.705 21.617 ;
     RECT  132.015 21.347 132.105 21.617 ;
     RECT  137.415 21.347 137.505 21.617 ;
     RECT  142.815 21.347 142.905 21.617 ;
     RECT  148.215 21.347 148.305 21.617 ;
     RECT  153.615 21.347 153.705 21.617 ;
     RECT  155.376 23.323 155.394 23.76 ;
     RECT  60.48 23.76 155.394 24.619 ;
     RECT  159.015 2.413 159.297 24.811 ;
     RECT  158.472 24.811 159.297 24.941 ;
     RECT  158.94 24.941 159.297 25.003 ;
     RECT  60.48 24.619 155.898 25.096 ;
     RECT  9.504 25.003 9.522 25.147 ;
     RECT  60.048 25.096 155.898 25.483 ;
     RECT  56.415 2.413 56.697 25.579 ;
     RECT  59.832 25.483 155.898 25.675 ;
     RECT  56.415 25.579 57.006 25.867 ;
     RECT  57.924 24.619 57.942 25.867 ;
     RECT  59.724 25.675 155.898 25.963 ;
     RECT  158.94 25.003 159.39 25.963 ;
     RECT  59.328 25.963 155.898 26.059 ;
     RECT  158.472 25.963 159.39 26.059 ;
     RECT  158.472 26.059 159.714 26.093 ;
     RECT  158.94 26.093 159.714 26.251 ;
     RECT  56.415 25.867 57.942 26.365 ;
     RECT  56.376 26.365 57.942 26.539 ;
     RECT  59.328 26.059 156.402 26.627 ;
     RECT  59.328 26.627 59.346 26.731 ;
     RECT  56.376 26.539 58.05 26.761 ;
     RECT  56.016 26.761 58.05 26.905 ;
     RECT  55.764 26.905 58.05 26.923 ;
     RECT  59.292 26.731 59.346 26.923 ;
     RECT  55.764 26.923 59.346 27.031 ;
     RECT  55.152 27.031 59.346 27.211 ;
     RECT  60.12 26.627 156.402 27.211 ;
     RECT  54.972 27.211 59.346 27.533 ;
     RECT  58.716 27.533 59.346 27.547 ;
     RECT  60.12 27.211 156.69 27.547 ;
     RECT  158.94 26.251 160.326 27.595 ;
     RECT  54.972 27.533 57.942 27.751 ;
     RECT  158.94 27.595 160.362 27.979 ;
     RECT  54.828 27.751 57.942 28.147 ;
     RECT  54.576 28.147 57.942 28.831 ;
     RECT  58.716 27.547 156.69 28.831 ;
     RECT  54.576 28.831 156.69 28.843 ;
     RECT  54.576 28.843 156.942 28.949 ;
     RECT  54.576 28.949 57.978 29.101 ;
     RECT  58.716 28.949 156.942 29.131 ;
     RECT  54.36 29.101 57.978 29.219 ;
     RECT  58.716 29.131 157.266 29.453 ;
     RECT  158.94 27.979 160.542 29.611 ;
     RECT  54.432 29.219 57.978 29.633 ;
     RECT  59.256 29.453 157.266 29.899 ;
     RECT  59.256 29.899 157.806 30.955 ;
     RECT  59.256 30.955 157.842 31.051 ;
     RECT  59.256 31.051 157.878 31.339 ;
     RECT  54.432 29.633 57.942 31.351 ;
     RECT  58.68 31.339 157.878 31.627 ;
     RECT  158.94 29.611 160.578 31.627 ;
     RECT  58.68 31.627 160.578 31.757 ;
     RECT  58.68 31.757 158.058 32.491 ;
     RECT  54.072 31.351 57.942 32.575 ;
     RECT  58.68 32.491 158.13 32.575 ;
     RECT  54.072 32.575 158.13 32.683 ;
     RECT  158.94 31.757 160.578 32.683 ;
     RECT  54.072 32.683 160.578 33.961 ;
     RECT  52.848 24.907 52.866 34.321 ;
     RECT  53.892 33.961 160.578 34.321 ;
     RECT  52.848 34.321 160.578 35.501 ;
     RECT  52.848 35.501 58.23 36.319 ;
     RECT  58.968 35.501 160.578 36.319 ;
     RECT  52.848 36.319 160.578 36.749 ;
     RECT  52.848 36.749 58.122 37.049 ;
     RECT  58.968 36.749 160.578 38.059 ;
     RECT  58.68 38.059 160.578 38.849 ;
     RECT  52.848 37.049 57.942 38.923 ;
     RECT  58.68 38.849 59.382 38.923 ;
     RECT  52.848 38.923 59.382 40.441 ;
     RECT  52.38 40.441 59.382 40.459 ;
     RECT  60.12 38.849 160.578 40.459 ;
     RECT  52.38 40.459 160.578 41.069 ;
     RECT  52.38 41.069 58.734 41.099 ;
     RECT  59.724 41.069 160.578 41.369 ;
     RECT  59.76 41.369 160.578 41.477 ;
     RECT  52.38 41.099 57.942 41.485 ;
     RECT  52.344 41.485 57.942 41.549 ;
     RECT  51.015 2.413 51.297 41.605 ;
     RECT  52.38 41.549 57.942 41.639 ;
     RECT  51.015 41.605 51.534 41.645 ;
     RECT  58.716 41.099 58.734 42.151 ;
     RECT  52.452 41.639 57.942 42.187 ;
     RECT  58.68 42.151 58.734 42.187 ;
     RECT  52.452 42.187 58.734 42.295 ;
     RECT  59.796 41.477 160.578 42.295 ;
     RECT  52.452 42.295 160.578 42.629 ;
     RECT  52.452 42.629 59.382 42.961 ;
     RECT  52.416 42.961 59.382 42.989 ;
     RECT  52.416 42.989 59.346 43.141 ;
     RECT  51.015 41.645 51.297 43.303 ;
     RECT  52.308 43.141 59.346 43.303 ;
     RECT  51.015 43.303 59.346 43.331 ;
     RECT  52.56 43.331 59.346 44.149 ;
     RECT  60.12 42.629 160.578 44.149 ;
     RECT  52.56 44.149 160.578 44.995 ;
     RECT  51.015 43.331 51.606 46.111 ;
     RECT  52.416 44.995 160.578 46.111 ;
     RECT  7.815 2.413 8.097 47.047 ;
     RECT  51.015 46.111 160.578 48.845 ;
     RECT  51.015 48.845 58.194 48.941 ;
     RECT  7.815 47.047 8.262 49.207 ;
     RECT  7.815 49.207 8.586 49.351 ;
     RECT  59.292 48.845 160.578 49.469 ;
     RECT  59.292 49.469 59.31 49.517 ;
     RECT  51.015 48.941 58.158 49.675 ;
     RECT  51.015 49.675 58.698 49.805 ;
     RECT  58.68 49.805 58.698 49.811 ;
     RECT  51.015 49.805 57.942 49.891 ;
     RECT  50.616 49.891 57.942 50.008 ;
     RECT  50.508 50.008 57.942 50.045 ;
     RECT  7.815 49.351 8.73 50.279 ;
     RECT  9.504 25.147 9.738 50.431 ;
     RECT  50.004 50.155 50.166 50.549 ;
     RECT  50.148 50.549 50.166 50.621 ;
     RECT  60.12 49.469 160.578 50.827 ;
     RECT  59.652 50.827 160.578 51.211 ;
     RECT  51.015 50.045 57.942 51.643 ;
     RECT  51.015 51.643 57.978 51.691 ;
     RECT  59.472 51.211 160.578 52.267 ;
     RECT  51.015 51.691 58.05 52.363 ;
     RECT  59.4 52.267 160.578 52.363 ;
     RECT  164.415 2.413 164.697 61.195 ;
     RECT  165.96 61.195 165.978 61.421 ;
     RECT  161.856 61.723 161.874 61.763 ;
     RECT  163.044 61.96 163.062 61.997 ;
     RECT  168.012 62.155 168.03 62.195 ;
     RECT  164.376 61.195 164.697 62.299 ;
     RECT  166.14 62.251 166.158 62.303 ;
     RECT  164.232 62.299 164.697 62.465 ;
     RECT  161.892 62.443 161.91 62.699 ;
     RECT  51.015 52.363 160.578 63.307 ;
     RECT  162.468 62.827 162.486 64.319 ;
     RECT  51.015 63.307 160.794 64.625 ;
     RECT  49.86 58.963 49.878 64.633 ;
     RECT  45.615 2.413 45.897 64.705 ;
     RECT  45.615 64.705 46.206 64.741 ;
     RECT  48.6 64.633 48.618 64.741 ;
     RECT  49.392 64.633 49.878 64.741 ;
     RECT  51.015 64.625 160.578 64.8 ;
     RECT  45.615 64.741 46.602 64.831 ;
     RECT  48.6 64.741 49.878 64.867 ;
     RECT  45.144 64.831 46.602 64.939 ;
     RECT  47.412 64.669 47.43 64.939 ;
     RECT  27.396 65.083 27.414 65.129 ;
     RECT  48.204 64.867 49.878 65.137 ;
     RECT  51.015 64.8 61.074 65.137 ;
     RECT  43.416 65.137 43.434 65.173 ;
     RECT  45.144 64.939 47.43 65.173 ;
     RECT  45 65.173 47.43 65.209 ;
     RECT  48.204 65.137 61.074 65.209 ;
     RECT  42.408 65.137 42.426 65.245 ;
     RECT  41.616 65.173 41.634 65.281 ;
     RECT  42.408 65.245 42.534 65.281 ;
     RECT  43.344 65.173 43.434 65.281 ;
     RECT  44.244 65.173 44.262 65.281 ;
     RECT  45 65.209 61.074 65.281 ;
     RECT  27.072 65.281 27.234 65.357 ;
     RECT  41.292 65.281 41.634 65.365 ;
     RECT  42.408 65.281 61.074 65.365 ;
     RECT  40.215 2.413 40.497 65.407 ;
     RECT  41.292 65.365 61.074 65.407 ;
     RECT  40.215 65.407 61.074 65.443 ;
     RECT  29.415 2.413 29.697 65.551 ;
     RECT  29.415 65.551 30.33 65.669 ;
     RECT  29.415 65.669 29.697 65.677 ;
     RECT  29.34 65.677 29.697 65.741 ;
     RECT  27.216 65.357 27.234 65.777 ;
     RECT  40.176 65.443 61.074 65.785 ;
     RECT  37.26 65.749 37.278 65.821 ;
     RECT  39.96 65.785 61.074 65.821 ;
     RECT  64.512 64.8 64.53 65.821 ;
     RECT  36.36 65.821 36.378 65.911 ;
     RECT  37.26 65.821 38.106 65.911 ;
     RECT  62.856 65.866 62.874 65.911 ;
     RECT  62.82 65.911 62.874 65.947 ;
     RECT  62.712 65.947 62.874 65.983 ;
     RECT  62.136 65.983 62.874 66.091 ;
     RECT  34.815 2.413 35.097 66.181 ;
     RECT  62.136 66.091 63.054 66.217 ;
     RECT  213.015 2.413 213.297 66.253 ;
     RECT  34.164 66.181 35.298 66.289 ;
     RECT  36.36 65.911 38.106 66.289 ;
     RECT  39.888 65.821 61.074 66.289 ;
     RECT  36.36 66.289 38.25 66.325 ;
     RECT  33.084 66.325 33.102 66.361 ;
     RECT  34.164 66.289 35.37 66.361 ;
     RECT  39.744 66.289 61.074 66.361 ;
     RECT  70.812 66.451 70.83 66.595 ;
     RECT  33.084 66.361 35.37 66.631 ;
     RECT  36.216 66.325 38.25 66.631 ;
     RECT  69.768 66.559 69.786 66.631 ;
     RECT  86.652 66.559 86.67 66.631 ;
     RECT  212.832 66.253 213.297 66.631 ;
     RECT  87.588 66.523 87.606 66.676 ;
     RECT  212.832 66.631 213.606 66.721 ;
     RECT  72.36 66.487 72.378 66.757 ;
     RECT  33.084 66.631 38.25 66.829 ;
     RECT  66.78 66.721 66.798 66.829 ;
     RECT  67.716 66.721 67.734 66.829 ;
     RECT  86.652 66.631 86.742 66.829 ;
     RECT  84.924 66.595 84.942 66.865 ;
     RECT  33.084 66.829 38.502 66.901 ;
     RECT  39.348 66.361 61.074 66.901 ;
     RECT  69.516 66.631 69.786 66.901 ;
     RECT  70.812 66.595 70.938 66.901 ;
     RECT  75.06 66.829 75.078 66.901 ;
     RECT  212.76 66.721 213.606 66.901 ;
     RECT  62.136 66.217 63.27 66.943 ;
     RECT  72.036 66.757 72.378 66.943 ;
     RECT  83.232 66.487 83.25 66.943 ;
     RECT  84.168 66.901 84.186 66.943 ;
     RECT  78.015 66.943 78.105 66.991 ;
     RECT  88.815 66.943 88.905 66.991 ;
     RECT  211.716 66.901 211.95 66.991 ;
     RECT  212.76 66.901 213.714 66.991 ;
     RECT  155.196 64.8 160.578 67.027 ;
     RECT  76.968 66.865 77.058 67.063 ;
     RECT  69.516 66.901 70.938 67.099 ;
     RECT  33.084 66.901 61.074 67.135 ;
     RECT  61.815 66.943 63.27 67.135 ;
     RECT  64.512 65.821 65.07 67.135 ;
     RECT  65.844 66.991 65.862 67.135 ;
     RECT  66.78 66.829 67.734 67.135 ;
     RECT  74.844 66.901 75.078 67.135 ;
     RECT  76.248 67.063 77.058 67.135 ;
     RECT  94.215 66.943 94.305 67.135 ;
     RECT  33.084 67.135 63.27 67.171 ;
     RECT  64.512 67.135 65.862 67.171 ;
     RECT  66.78 67.135 67.95 67.171 ;
     RECT  79.812 67.027 79.83 67.171 ;
     RECT  82.008 67.135 82.026 67.171 ;
     RECT  211.716 66.991 213.714 67.171 ;
     RECT  76.248 67.135 77.13 67.195 ;
     RECT  72.036 66.943 72.705 67.213 ;
     RECT  73.548 66.523 73.566 67.213 ;
     RECT  93.348 67.135 94.305 67.213 ;
     RECT  99.615 66.943 99.705 67.213 ;
     RECT  105.015 66.943 105.105 67.213 ;
     RECT  110.415 66.943 110.505 67.213 ;
     RECT  115.815 66.943 115.905 67.213 ;
     RECT  121.215 66.943 121.305 67.213 ;
     RECT  126.615 66.943 126.705 67.213 ;
     RECT  132.015 66.943 132.105 67.213 ;
     RECT  137.415 66.943 137.505 67.213 ;
     RECT  142.815 66.943 142.905 67.213 ;
     RECT  148.215 66.943 148.305 67.213 ;
     RECT  153.615 66.943 153.705 67.213 ;
     RECT  69.156 67.099 71.082 67.243 ;
     RECT  72.036 67.213 73.566 67.243 ;
     RECT  33.084 67.171 63.738 67.261 ;
     RECT  69.156 67.243 73.566 67.261 ;
     RECT  74.772 67.135 75.078 67.261 ;
     RECT  82.008 67.171 82.17 67.261 ;
     RECT  83.232 66.943 84.186 67.261 ;
     RECT  84.924 66.865 85.014 67.261 ;
     RECT  86.112 66.829 86.742 67.261 ;
     RECT  87.588 66.676 87.822 67.261 ;
     RECT  91.728 67.261 91.746 67.291 ;
     RECT  33.012 67.261 63.738 67.297 ;
     RECT  64.512 67.171 68.382 67.297 ;
     RECT  69.156 67.261 75.186 67.297 ;
     RECT  81.324 67.261 85.014 67.297 ;
     RECT  88.815 66.991 89.154 67.297 ;
     RECT  93.348 67.213 94.497 67.297 ;
     RECT  211.716 67.171 213.75 67.297 ;
     RECT  90.684 67.288 90.702 67.333 ;
     RECT  91.728 67.291 91.998 67.333 ;
     RECT  97.164 67.171 97.182 67.333 ;
     RECT  31.464 67.291 31.482 67.369 ;
     RECT  92.916 67.297 94.497 67.369 ;
     RECT  76.248 67.195 77.166 67.387 ;
     RECT  78.015 66.991 78.714 67.387 ;
     RECT  31.32 67.369 31.482 67.405 ;
     RECT  78.012 67.387 78.714 67.405 ;
     RECT  79.812 67.171 80.406 67.405 ;
     RECT  90.36 67.333 91.998 67.405 ;
     RECT  92.916 67.369 95.202 67.405 ;
     RECT  211.176 67.297 213.75 67.405 ;
     RECT  81.288 67.297 85.014 67.435 ;
     RECT  28.44 67.291 28.458 67.441 ;
     RECT  29.415 65.741 29.697 67.441 ;
     RECT  77.94 67.405 80.406 67.441 ;
     RECT  81.216 67.435 85.014 67.441 ;
     RECT  86.112 67.261 87.822 67.441 ;
     RECT  90.324 67.405 91.998 67.441 ;
     RECT  92.916 67.405 95.454 67.441 ;
     RECT  96.3 67.333 96.318 67.441 ;
     RECT  207.615 2.413 207.897 67.441 ;
     RECT  210.348 67.369 210.366 67.441 ;
     RECT  211.104 67.405 213.75 67.441 ;
     RECT  86.112 67.441 88.074 67.531 ;
     RECT  88.815 67.297 89.37 67.531 ;
     RECT  215.892 67.387 215.91 67.565 ;
     RECT  31.104 67.405 31.482 67.567 ;
     RECT  33.012 67.297 75.186 67.567 ;
     RECT  76.176 67.387 77.166 67.567 ;
     RECT  77.94 67.441 85.014 67.567 ;
     RECT  86.112 67.531 89.514 67.567 ;
     RECT  90.324 67.441 96.318 67.567 ;
     RECT  97.092 67.333 97.182 67.567 ;
     RECT  28.08 67.441 29.697 67.603 ;
     RECT  31.104 67.567 31.914 67.603 ;
     RECT  90.324 67.567 97.182 67.603 ;
     RECT  207.288 67.441 207.897 67.603 ;
     RECT  210.348 67.441 213.75 67.603 ;
     RECT  33.012 67.567 75.258 67.639 ;
     RECT  32.652 67.639 75.258 67.669 ;
     RECT  209.304 67.603 209.322 67.669 ;
     RECT  30.996 67.603 31.914 67.675 ;
     RECT  76.176 67.567 89.514 67.675 ;
     RECT  90.288 67.603 97.182 67.675 ;
     RECT  98.1 67.441 98.118 67.675 ;
     RECT  210.348 67.603 214.362 67.675 ;
     RECT  28.08 67.603 29.754 67.711 ;
     RECT  32.652 67.669 75.33 67.711 ;
     RECT  76.176 67.675 98.118 67.711 ;
     RECT  153.615 67.213 153.897 67.711 ;
     RECT  155.052 67.027 160.578 67.711 ;
     RECT  27.864 67.711 29.754 67.723 ;
     RECT  30.492 67.675 31.914 67.723 ;
     RECT  32.652 67.711 98.73 67.739 ;
     RECT  32.76 67.739 98.73 67.801 ;
     RECT  99.615 67.213 99.897 67.801 ;
     RECT  152.676 67.639 152.694 67.801 ;
     RECT  202.215 2.413 202.497 67.801 ;
     RECT  209.304 67.669 209.358 67.801 ;
     RECT  210.132 67.675 214.362 67.801 ;
     RECT  32.76 67.801 99.897 67.829 ;
     RECT  152.424 67.801 152.694 67.829 ;
     RECT  110.415 67.213 110.697 67.837 ;
     RECT  209.268 67.801 214.902 67.873 ;
     RECT  209.232 67.873 214.902 67.909 ;
     RECT  152.424 67.829 152.55 67.937 ;
     RECT  80.64 67.829 99.897 67.949 ;
     RECT  206.928 67.603 207.897 67.981 ;
     RECT  208.836 67.909 214.902 67.981 ;
     RECT  202.215 67.801 202.95 68.107 ;
     RECT  153.615 67.711 160.578 68.171 ;
     RECT  98.424 67.949 99.897 68.251 ;
     RECT  204.372 68.071 204.462 68.251 ;
     RECT  205.38 67.909 205.398 68.251 ;
     RECT  206.928 67.981 214.902 68.251 ;
     RECT  98.424 68.251 99.99 68.377 ;
     RECT  32.76 67.829 79.83 68.405 ;
     RECT  206.928 68.251 214.938 68.449 ;
     RECT  27.864 67.723 31.914 68.521 ;
     RECT  197.82 68.377 197.838 68.521 ;
     RECT  200.772 68.071 200.79 68.521 ;
     RECT  202.176 68.107 202.95 68.521 ;
     RECT  204.372 68.251 205.398 68.521 ;
     RECT  206.316 68.449 214.938 68.525 ;
     RECT  98.424 68.377 100.314 68.611 ;
     RECT  197.82 68.521 197.91 68.611 ;
     RECT  150.876 68.521 150.894 68.639 ;
     RECT  196.815 2.413 197.097 68.647 ;
     RECT  35.928 68.405 79.83 68.675 ;
     RECT  200.628 68.521 200.79 68.683 ;
     RECT  206.316 68.525 214.866 68.717 ;
     RECT  64.08 68.675 79.83 68.783 ;
     RECT  27.684 68.521 31.914 68.791 ;
     RECT  32.76 68.405 35.154 68.791 ;
     RECT  98.424 68.611 100.638 68.791 ;
     RECT  80.64 67.949 97.47 68.875 ;
     RECT  98.424 68.791 101.322 68.875 ;
     RECT  80.64 68.875 101.322 68.881 ;
     RECT  200.484 68.683 200.79 68.881 ;
     RECT  202.176 68.521 205.434 68.881 ;
     RECT  214.344 68.717 214.866 68.909 ;
     RECT  27.684 68.791 35.154 68.917 ;
     RECT  72.432 68.783 79.83 68.917 ;
     RECT  80.64 68.881 101.646 68.917 ;
     RECT  202.176 68.881 205.47 68.917 ;
     RECT  27.18 68.917 35.154 68.957 ;
     RECT  215.82 68.779 215.838 68.957 ;
     RECT  110.415 67.837 111.258 68.989 ;
     RECT  151.596 68.755 151.614 68.989 ;
     RECT  152.424 67.937 152.442 68.989 ;
     RECT  206.316 68.717 213.498 68.989 ;
     RECT  153.615 68.171 153.897 69.061 ;
     RECT  155.052 68.171 160.578 69.061 ;
     RECT  196.38 68.647 197.097 69.061 ;
     RECT  197.82 68.611 197.982 69.061 ;
     RECT  202.032 68.917 205.47 69.061 ;
     RECT  200.124 68.881 200.79 69.151 ;
     RECT  201.816 69.061 205.47 69.151 ;
     RECT  206.28 68.989 213.498 69.151 ;
     RECT  214.416 68.909 214.866 69.179 ;
     RECT  151.596 68.989 152.442 69.223 ;
     RECT  153.615 69.061 160.578 69.251 ;
     RECT  27.396 68.957 35.154 69.295 ;
     RECT  35.928 68.675 63.306 69.295 ;
     RECT  150.552 68.683 150.57 69.331 ;
     RECT  199.872 69.151 200.79 69.331 ;
     RECT  199.872 69.331 201.042 69.421 ;
     RECT  201.816 69.151 213.498 69.421 ;
     RECT  151.596 69.223 152.478 69.449 ;
     RECT  153.615 69.251 154.026 69.449 ;
     RECT  196.38 69.061 197.982 69.493 ;
     RECT  150.48 69.331 150.57 69.521 ;
     RECT  64.08 68.783 71.694 69.533 ;
     RECT  64.368 69.533 71.694 69.565 ;
     RECT  72.432 68.917 101.646 69.565 ;
     RECT  137.415 67.213 137.697 69.601 ;
     RECT  199.872 69.421 213.498 69.691 ;
     RECT  27.396 69.295 63.306 69.719 ;
     RECT  214.416 69.179 214.83 69.719 ;
     RECT  199.404 69.691 213.498 69.763 ;
     RECT  214.416 69.719 214.794 69.763 ;
     RECT  26.496 69.025 26.514 69.799 ;
     RECT  27.396 69.719 63.162 69.799 ;
     RECT  199.404 69.763 214.794 69.799 ;
     RECT  133.38 69.223 133.398 69.827 ;
     RECT  199.188 69.799 214.794 69.835 ;
     RECT  196.092 69.493 197.982 69.989 ;
     RECT  215.856 69.493 215.874 69.997 ;
     RECT  64.368 69.565 101.646 70.061 ;
     RECT  64.368 70.061 100.314 70.097 ;
     RECT  26.496 69.799 63.162 70.141 ;
     RECT  199.008 69.835 214.794 70.141 ;
     RECT  64.368 70.097 95.238 70.295 ;
     RECT  121.215 67.213 121.497 70.303 ;
     RECT  153.615 69.449 153.897 70.375 ;
     RECT  155.052 69.251 160.578 70.501 ;
     RECT  153.504 70.375 153.897 70.529 ;
     RECT  196.308 69.989 197.097 70.529 ;
     RECT  196.704 70.529 197.097 70.565 ;
     RECT  126.615 67.213 126.897 70.573 ;
     RECT  64.368 70.295 95.166 70.601 ;
     RECT  126.615 70.573 127.314 70.609 ;
     RECT  26.424 70.141 63.162 70.637 ;
     RECT  64.368 70.601 64.782 70.637 ;
     RECT  26.424 70.637 42.03 70.673 ;
     RECT  150.48 70.267 150.498 70.673 ;
     RECT  153.576 70.529 153.897 70.681 ;
     RECT  154.98 70.501 160.578 70.681 ;
     RECT  122.796 70.267 122.814 70.699 ;
     RECT  123.876 70.681 123.894 70.699 ;
     RECT  121.215 70.303 121.734 70.771 ;
     RECT  125.604 68.791 125.622 70.771 ;
     RECT  198.36 70.141 214.794 70.771 ;
     RECT  122.508 70.699 122.814 70.795 ;
     RECT  122.508 70.795 122.958 70.798 ;
     RECT  26.496 70.673 37.998 70.799 ;
     RECT  71.316 70.601 95.166 70.799 ;
     RECT  101.376 70.061 101.646 70.807 ;
     RECT  95.976 70.097 100.314 70.843 ;
     RECT  115.815 67.213 116.097 70.843 ;
     RECT  151.596 69.449 151.614 70.843 ;
     RECT  151.596 70.843 151.722 70.879 ;
     RECT  95.904 70.843 100.314 70.915 ;
     RECT  101.124 70.807 101.79 70.915 ;
     RECT  120.636 70.771 121.734 70.915 ;
     RECT  122.472 70.798 122.958 70.915 ;
     RECT  198.36 70.771 214.902 70.925 ;
     RECT  65.628 70.601 67.95 70.943 ;
     RECT  120.636 70.915 122.958 70.951 ;
     RECT  123.876 70.699 124.146 70.951 ;
     RECT  151.596 70.879 152.298 70.951 ;
     RECT  65.808 70.943 67.95 71.069 ;
     RECT  71.316 70.799 89.442 71.069 ;
     RECT  90.252 70.799 95.166 71.113 ;
     RECT  95.904 70.915 101.79 71.113 ;
     RECT  64.368 70.637 64.386 71.177 ;
     RECT  132.015 67.213 132.297 71.185 ;
     RECT  71.316 71.069 89.154 71.213 ;
     RECT  90.252 71.113 101.79 71.221 ;
     RECT  196.815 70.565 197.097 71.221 ;
     RECT  42.804 70.637 63.162 71.275 ;
     RECT  215.82 69.997 215.874 71.309 ;
     RECT  88.776 71.213 89.154 71.339 ;
     RECT  90.252 71.221 101.862 71.339 ;
     RECT  107.424 71.149 107.442 71.371 ;
     RECT  215.82 71.309 215.838 71.405 ;
     RECT  153.576 70.681 160.578 71.411 ;
     RECT  68.688 70.601 70.326 71.419 ;
     RECT  105.015 67.213 105.297 71.419 ;
     RECT  126.615 70.609 127.926 71.419 ;
     RECT  65.88 71.069 67.95 71.455 ;
     RECT  68.688 71.419 70.398 71.455 ;
     RECT  117.936 71.347 117.954 71.455 ;
     RECT  38.736 70.673 41.85 71.491 ;
     RECT  42.804 71.275 63.522 71.491 ;
     RECT  91.26 71.339 101.862 71.491 ;
     RECT  107.352 71.371 107.442 71.491 ;
     RECT  117.936 71.455 118.386 71.491 ;
     RECT  120.276 70.951 124.29 71.491 ;
     RECT  194.364 70.681 194.382 71.491 ;
     RECT  115.164 70.843 116.097 71.519 ;
     RECT  65.88 71.455 70.398 71.581 ;
     RECT  71.316 71.213 87.93 71.581 ;
     RECT  191.415 2.413 191.697 71.581 ;
     RECT  65.88 71.581 87.93 71.609 ;
     RECT  107.136 71.491 107.442 71.609 ;
     RECT  117.828 71.491 118.386 71.609 ;
     RECT  198.36 70.925 214.65 71.611 ;
     RECT  26.496 70.799 37.926 71.617 ;
     RECT  105.015 71.419 105.606 71.617 ;
     RECT  113.4 70.411 113.418 71.645 ;
     RECT  104.04 71.491 104.058 71.653 ;
     RECT  104.796 71.617 105.606 71.653 ;
     RECT  65.88 71.609 87.462 71.654 ;
     RECT  198.108 71.611 214.65 71.659 ;
     RECT  65.88 71.654 87.426 71.681 ;
     RECT  196.815 71.221 197.226 71.689 ;
     RECT  198.108 71.659 214.866 71.689 ;
     RECT  107.136 71.609 107.37 71.707 ;
     RECT  119.772 71.491 124.29 71.707 ;
     RECT  125.064 70.771 125.622 71.707 ;
     RECT  90.252 71.339 90.486 71.725 ;
     RECT  117.828 71.609 117.99 71.725 ;
     RECT  133.884 70.069 133.902 71.725 ;
     RECT  65.88 71.681 87.246 71.741 ;
     RECT  132.015 71.185 132.75 71.752 ;
     RECT  142.815 67.213 143.097 71.752 ;
     RECT  153.576 71.411 153.897 71.752 ;
     RECT  164.415 62.465 164.697 71.752 ;
     RECT  175.215 2.413 175.497 71.752 ;
     RECT  186.015 2.413 186.297 71.752 ;
     RECT  26.424 71.617 37.926 71.761 ;
     RECT  38.736 71.491 63.522 71.761 ;
     RECT  126.615 71.419 128.178 71.761 ;
     RECT  142.704 71.752 143.097 71.789 ;
     RECT  153.504 71.752 153.897 71.789 ;
     RECT  175.104 71.752 175.497 71.789 ;
     RECT  185.904 71.752 186.297 71.789 ;
     RECT  126.504 71.761 128.178 71.803 ;
     RECT  104.04 71.653 105.606 71.851 ;
     RECT  119.772 71.707 125.622 71.851 ;
     RECT  126.504 71.803 128.682 71.851 ;
     RECT  129.6 70.033 129.618 71.851 ;
     RECT  119.772 71.851 128.682 71.887 ;
     RECT  129.456 71.851 129.69 71.887 ;
     RECT  151.056 70.951 152.298 71.887 ;
     RECT  64.512 71.761 64.89 71.915 ;
     RECT  150.444 71.887 152.298 71.915 ;
     RECT  118.836 71.761 118.962 71.923 ;
     RECT  119.772 71.887 129.69 71.923 ;
     RECT  131.904 71.752 132.75 71.923 ;
     RECT  64.512 71.915 64.602 71.959 ;
     RECT  103.428 71.851 105.93 71.959 ;
     RECT  106.704 71.707 107.37 71.959 ;
     RECT  108.612 69.799 108.63 71.959 ;
     RECT  91.26 71.491 102.654 71.995 ;
     RECT  103.428 71.959 107.37 71.995 ;
     RECT  117.432 71.725 117.99 72.031 ;
     RECT  131.868 71.923 132.75 72.031 ;
     RECT  196.815 71.689 214.866 72.031 ;
     RECT  150.444 71.915 151.074 72.059 ;
     RECT  194.364 71.491 194.454 72.091 ;
     RECT  118.836 71.923 129.69 72.121 ;
     RECT  130.428 69.493 130.446 72.121 ;
     RECT  191.415 71.581 192.114 72.121 ;
     RECT  193.248 72.031 193.266 72.121 ;
     RECT  194.256 72.091 194.454 72.121 ;
     RECT  164.304 71.752 164.697 72.139 ;
     RECT  65.88 71.741 87.138 72.149 ;
     RECT  88.776 71.339 89.097 72.157 ;
     RECT  90.144 71.725 90.486 72.157 ;
     RECT  65.88 72.149 66.222 72.185 ;
     RECT  152.172 71.915 152.298 72.185 ;
     RECT  153.576 71.789 153.897 72.185 ;
     RECT  115.815 71.519 116.097 72.193 ;
     RECT  191.415 72.121 194.454 72.193 ;
     RECT  65.88 72.185 66.186 72.257 ;
     RECT  88.776 72.157 90.486 72.265 ;
     RECT  91.26 71.995 107.37 72.265 ;
     RECT  115.815 72.193 116.334 72.265 ;
     RECT  117.072 72.031 117.99 72.265 ;
     RECT  131.508 72.031 132.75 72.265 ;
     RECT  26.316 71.761 63.666 72.301 ;
     RECT  114.588 71.659 114.678 72.301 ;
     RECT  115.488 72.265 117.99 72.301 ;
     RECT  114.588 72.301 117.99 72.391 ;
     RECT  118.836 72.121 130.446 72.391 ;
     RECT  196.092 72.031 214.866 72.391 ;
     RECT  26.28 72.301 63.666 72.427 ;
     RECT  131.472 72.265 132.75 72.427 ;
     RECT  67.215 72.149 87.138 72.463 ;
     RECT  109.404 72.427 109.422 72.499 ;
     RECT  110.415 68.989 111.33 72.499 ;
     RECT  153.615 72.185 153.897 72.499 ;
     RECT  155.052 71.411 160.578 72.499 ;
     RECT  108.216 71.959 108.63 72.535 ;
     RECT  109.404 72.499 109.53 72.535 ;
     RECT  110.34 72.499 111.33 72.535 ;
     RECT  195.588 72.391 214.866 72.535 ;
     RECT  195.48 72.535 214.866 72.557 ;
     RECT  26.244 72.427 63.666 72.563 ;
     RECT  215.892 72.139 215.91 72.563 ;
     RECT  88.776 72.265 107.37 72.565 ;
     RECT  108.216 72.535 109.53 72.565 ;
     RECT  131.472 72.427 133.002 72.565 ;
     RECT  133.812 71.725 133.902 72.565 ;
     RECT  67.215 72.463 87.426 72.571 ;
     RECT  88.776 72.565 109.53 72.571 ;
     RECT  110.34 72.535 111.69 72.571 ;
     RECT  114.588 72.391 130.446 72.571 ;
     RECT  131.472 72.565 133.902 72.571 ;
     RECT  67.215 72.571 87.75 72.661 ;
     RECT  88.776 72.571 111.69 72.661 ;
     RECT  114.588 72.571 133.902 72.661 ;
     RECT  67.215 72.661 112.122 72.689 ;
     RECT  68.508 72.689 112.122 72.697 ;
     RECT  190.404 72.571 190.422 72.697 ;
     RECT  151.056 72.059 151.074 72.769 ;
     RECT  190.008 72.697 190.422 72.805 ;
     RECT  114.372 72.661 133.938 72.841 ;
     RECT  151.056 72.769 151.182 72.841 ;
     RECT  190.008 72.805 190.638 72.841 ;
     RECT  191.415 72.193 194.742 72.841 ;
     RECT  195.48 72.557 213.57 72.841 ;
     RECT  214.308 72.557 214.866 72.841 ;
     RECT  148.215 67.213 148.497 72.907 ;
     RECT  153.615 72.499 160.578 72.907 ;
     RECT  163.008 72.811 163.026 72.907 ;
     RECT  68.508 72.697 112.698 72.931 ;
     RECT  136.8 69.601 137.697 72.931 ;
     RECT  162.504 72.907 163.026 72.941 ;
     RECT  190.008 72.841 213.57 72.941 ;
     RECT  113.796 72.841 133.938 72.955 ;
     RECT  27.648 72.563 63.666 72.959 ;
     RECT  148.104 72.907 148.497 72.959 ;
     RECT  151.056 72.841 151.326 72.959 ;
     RECT  153.504 72.907 160.578 72.959 ;
     RECT  164.052 72.139 164.697 72.959 ;
     RECT  168.66 72.907 168.678 72.959 ;
     RECT  67.215 72.689 67.662 72.967 ;
     RECT  68.508 72.931 112.878 72.967 ;
     RECT  113.76 72.955 133.938 73.003 ;
     RECT  136.8 72.931 137.97 73.003 ;
     RECT  186.015 71.789 186.297 73.003 ;
     RECT  68.508 72.967 112.95 73.037 ;
     RECT  151.164 72.959 151.326 73.039 ;
     RECT  152.172 72.185 152.226 73.039 ;
     RECT  162.504 72.941 162.594 73.039 ;
     RECT  151.164 73.039 152.226 73.067 ;
     RECT  186.015 73.003 186.462 73.103 ;
     RECT  65.88 72.257 65.97 73.111 ;
     RECT  66.708 72.967 67.662 73.111 ;
     RECT  87.732 73.037 112.95 73.111 ;
     RECT  113.76 73.003 134.586 73.111 ;
     RECT  27.864 72.959 63.666 73.139 ;
     RECT  162.468 73.039 162.594 73.139 ;
     RECT  136.8 73.003 138.042 73.201 ;
     RECT  65.88 73.111 67.662 73.237 ;
     RECT  87.732 73.111 134.586 73.265 ;
     RECT  64.404 71.959 64.602 73.273 ;
     RECT  136.116 73.201 138.042 73.273 ;
     RECT  139.284 72.805 139.302 73.273 ;
     RECT  65.736 73.237 67.662 73.277 ;
     RECT  190.224 72.941 213.57 73.291 ;
     RECT  214.308 72.841 214.902 73.291 ;
     RECT  136.116 73.273 139.302 73.309 ;
     RECT  87.804 73.265 134.586 73.345 ;
     RECT  135.828 73.309 139.302 73.373 ;
     RECT  186.015 73.103 186.426 73.373 ;
     RECT  167.904 72.907 167.922 73.379 ;
     RECT  87.804 73.345 134.982 73.381 ;
     RECT  135.828 73.373 138.51 73.381 ;
     RECT  215.82 72.763 215.838 73.483 ;
     RECT  162.576 73.139 162.594 73.517 ;
     RECT  64.404 73.273 64.89 73.535 ;
     RECT  66.06 73.277 67.662 73.535 ;
     RECT  151.56 73.067 152.226 73.535 ;
     RECT  26.244 72.563 26.91 73.543 ;
     RECT  66.204 73.535 67.662 73.543 ;
     RECT  68.508 73.037 86.994 73.543 ;
     RECT  190.224 73.291 214.902 73.571 ;
     RECT  215.784 73.483 215.838 73.579 ;
     RECT  195.48 73.571 214.902 73.709 ;
     RECT  26.136 73.543 26.91 73.741 ;
     RECT  190.224 73.571 194.742 73.769 ;
     RECT  139.284 73.373 139.302 73.777 ;
     RECT  25.956 73.741 26.91 73.813 ;
     RECT  27.864 73.139 63.306 73.813 ;
     RECT  195.48 73.709 214.866 73.841 ;
     RECT  195.516 73.841 214.866 73.853 ;
     RECT  215.784 73.579 215.91 73.877 ;
     RECT  215.856 73.877 215.91 73.885 ;
     RECT  25.956 73.813 63.306 73.921 ;
     RECT  87.804 73.381 138.51 74.039 ;
     RECT  151.56 73.535 151.722 74.039 ;
     RECT  25.776 73.921 63.306 74.083 ;
     RECT  151.56 74.039 151.578 74.083 ;
     RECT  195.552 73.853 214.866 74.111 ;
     RECT  66.204 73.543 86.994 74.191 ;
     RECT  117.828 74.039 138.51 74.281 ;
     RECT  139.284 73.777 139.446 74.281 ;
     RECT  25.704 74.083 63.306 74.309 ;
     RECT  151.452 74.083 151.578 74.309 ;
     RECT  117.828 74.281 139.446 74.347 ;
     RECT  64.404 73.535 64.422 74.353 ;
     RECT  153.615 72.959 160.578 74.353 ;
     RECT  186.015 73.373 186.297 74.353 ;
     RECT  195.948 74.111 214.866 74.381 ;
     RECT  66.204 74.191 87.03 74.389 ;
     RECT  87.804 74.039 117.018 74.389 ;
     RECT  117.828 74.347 139.518 74.453 ;
     RECT  186.015 74.353 186.426 74.461 ;
     RECT  139.392 74.453 139.518 74.462 ;
     RECT  153.072 74.353 160.578 74.489 ;
     RECT  190.404 73.769 194.742 74.539 ;
     RECT  66.204 74.389 117.018 74.579 ;
     RECT  117.828 74.453 138.618 74.579 ;
     RECT  139.392 74.462 139.482 74.615 ;
     RECT  190.296 74.539 194.742 74.623 ;
     RECT  72.576 74.579 117.018 74.651 ;
     RECT  7.815 50.279 8.262 74.659 ;
     RECT  9 50.431 9.738 74.659 ;
     RECT  22.068 74.551 22.086 74.659 ;
     RECT  66.204 74.579 71.766 74.723 ;
     RECT  20.952 74.395 20.97 74.821 ;
     RECT  22.068 74.659 22.23 74.821 ;
     RECT  24.015 2.413 24.297 74.821 ;
     RECT  25.704 74.309 63.054 74.821 ;
     RECT  74.916 74.651 117.018 74.821 ;
     RECT  117.828 74.579 138.582 74.821 ;
     RECT  23.292 74.821 24.297 74.827 ;
     RECT  190.296 74.623 195.21 74.849 ;
     RECT  195.948 74.381 205.794 74.849 ;
     RECT  25.344 74.821 63.054 74.893 ;
     RECT  74.916 74.821 138.582 74.921 ;
     RECT  19.98 74.587 19.998 74.929 ;
     RECT  20.952 74.821 22.23 74.929 ;
     RECT  25.236 74.893 63.054 74.929 ;
     RECT  190.296 74.849 195.174 74.963 ;
     RECT  23.184 74.827 24.297 74.965 ;
     RECT  186.015 74.461 186.498 74.965 ;
     RECT  64.404 74.353 64.494 74.971 ;
     RECT  190.296 74.963 195.102 74.971 ;
     RECT  18.615 2.413 18.897 75.001 ;
     RECT  19.98 74.929 22.23 75.001 ;
     RECT  23.184 74.965 24.39 75.001 ;
     RECT  18.615 75.001 24.39 75.019 ;
     RECT  25.2 74.929 63.054 75.019 ;
     RECT  215.856 73.885 215.982 75.046 ;
     RECT  4.428 75.001 4.698 75.091 ;
     RECT  5.472 75.001 5.49 75.091 ;
     RECT  64.404 74.971 65.214 75.119 ;
     RECT  90.792 74.921 138.582 75.119 ;
     RECT  186.015 74.965 186.534 75.119 ;
     RECT  190.188 74.971 195.102 75.119 ;
     RECT  3.924 75.091 5.49 75.127 ;
     RECT  74.916 74.921 89.874 75.155 ;
     RECT  190.188 75.119 194.922 75.155 ;
     RECT  18.615 75.019 63.054 75.163 ;
     RECT  186.015 75.119 186.462 75.191 ;
     RECT  190.188 75.155 193.266 75.191 ;
     RECT  3.924 75.127 5.922 75.199 ;
     RECT  18.54 75.163 63.054 75.227 ;
     RECT  192.708 75.191 193.266 75.227 ;
     RECT  194.256 75.155 194.922 75.227 ;
     RECT  140.22 75.091 140.238 75.235 ;
     RECT  3.744 75.199 5.922 75.259 ;
     RECT  195.984 74.849 205.794 75.271 ;
     RECT  206.676 74.381 214.866 75.271 ;
     RECT  192.708 75.227 193.014 75.299 ;
     RECT  139.608 75.235 140.238 75.389 ;
     RECT  194.328 75.227 194.922 75.389 ;
     RECT  66.348 74.723 71.766 75.397 ;
     RECT  72.576 74.651 74.034 75.397 ;
     RECT  194.328 75.389 194.886 75.437 ;
     RECT  194.328 75.437 194.814 75.497 ;
     RECT  3.744 75.259 6.282 75.505 ;
     RECT  150.48 74.929 150.498 75.505 ;
     RECT  66.348 75.397 74.034 75.533 ;
     RECT  2.415 2.413 2.697 75.541 ;
     RECT  3.744 75.505 6.354 75.541 ;
     RECT  7.815 74.659 9.738 75.541 ;
     RECT  18.54 75.227 24.534 75.541 ;
     RECT  195.984 75.271 214.866 75.569 ;
     RECT  13.215 2.413 13.497 75.595 ;
     RECT  2.415 75.541 6.534 75.631 ;
     RECT  7.308 75.541 9.738 75.631 ;
     RECT  17.1 75.361 17.118 75.631 ;
     RECT  90.792 75.119 111.186 75.643 ;
     RECT  18.252 75.541 24.534 75.659 ;
     RECT  66.492 75.533 74.034 75.667 ;
     RECT  74.916 75.155 87.966 75.667 ;
     RECT  88.815 75.155 89.874 75.691 ;
     RECT  90.684 75.643 111.186 75.691 ;
     RECT  66.492 75.667 87.966 75.695 ;
     RECT  150.444 75.505 150.498 75.703 ;
     RECT  197.892 75.569 198.342 75.725 ;
     RECT  2.415 75.631 9.738 75.731 ;
     RECT  111.996 75.119 138.582 75.731 ;
     RECT  139.356 75.469 139.446 75.731 ;
     RECT  199.188 75.569 214.866 75.731 ;
     RECT  190.26 75.191 191.697 75.767 ;
     RECT  10.476 24.715 10.494 75.775 ;
     RECT  12.852 75.595 13.497 75.775 ;
     RECT  16.92 75.631 17.118 75.775 ;
     RECT  134.028 75.731 138.582 75.775 ;
     RECT  76.716 75.695 87.966 75.803 ;
     RECT  140.22 75.389 140.238 75.803 ;
     RECT  150.408 75.703 150.57 75.803 ;
     RECT  16.92 75.775 17.37 75.811 ;
     RECT  25.668 75.227 63.054 75.839 ;
     RECT  66.492 75.695 75.906 75.839 ;
     RECT  200.052 75.731 214.866 75.839 ;
     RECT  215.784 75.046 215.982 75.883 ;
     RECT  64.476 75.119 64.494 75.928 ;
     RECT  38.52 75.839 63.054 75.929 ;
     RECT  197.892 75.725 198.018 75.929 ;
     RECT  199.188 75.731 199.314 75.929 ;
     RECT  88.815 75.691 111.186 75.937 ;
     RECT  111.996 75.731 133.29 75.937 ;
     RECT  12.456 75.775 13.497 75.965 ;
     RECT  25.668 75.839 37.674 75.965 ;
     RECT  76.716 75.803 81.558 75.965 ;
     RECT  197.892 75.929 197.91 75.965 ;
     RECT  199.188 75.929 199.206 75.965 ;
     RECT  2.415 75.731 6.462 75.973 ;
     RECT  18.615 75.659 24.534 75.979 ;
     RECT  25.668 75.965 37.566 75.979 ;
     RECT  76.752 75.965 81.558 76.001 ;
     RECT  192.708 75.299 192.762 76.009 ;
     RECT  215.676 75.883 215.982 76.013 ;
     RECT  192.672 76.009 192.762 76.037 ;
     RECT  15.912 75.901 16.002 76.045 ;
     RECT  151.56 74.309 151.578 76.045 ;
     RECT  134.028 75.775 139.122 76.061 ;
     RECT  15.912 76.045 16.038 76.081 ;
     RECT  16.92 75.811 17.514 76.081 ;
     RECT  195.984 75.569 197.154 76.109 ;
     RECT  15.912 76.081 17.514 76.199 ;
     RECT  134.028 76.061 138.366 76.199 ;
     RECT  192.672 76.037 192.69 76.199 ;
     RECT  76.752 76.001 81.522 76.235 ;
     RECT  190.26 75.767 190.278 76.271 ;
     RECT  200.268 75.839 214.866 76.271 ;
     RECT  7.2 75.731 9.738 76.351 ;
     RECT  10.476 75.775 10.89 76.351 ;
     RECT  15.912 76.199 17.442 76.351 ;
     RECT  82.404 75.803 87.966 76.351 ;
     RECT  88.815 75.937 133.29 76.351 ;
     RECT  134.028 76.199 138.294 76.379 ;
     RECT  201.132 76.271 214.866 76.379 ;
     RECT  2.34 75.973 6.462 76.397 ;
     RECT  65.52 76.045 65.538 76.441 ;
     RECT  66.492 75.839 75.834 76.441 ;
     RECT  195.984 76.109 197.097 76.441 ;
     RECT  7.2 76.351 10.89 76.469 ;
     RECT  82.404 76.351 133.29 76.469 ;
     RECT  139.104 76.061 139.122 76.469 ;
     RECT  82.404 76.469 118.026 76.493 ;
     RECT  14.292 76.351 14.958 76.505 ;
     RECT  200.268 76.271 200.286 76.505 ;
     RECT  215.712 76.013 215.982 76.505 ;
     RECT  63.864 75.928 64.494 76.513 ;
     RECT  18.615 75.979 37.566 76.541 ;
     RECT  2.34 76.397 4.59 76.585 ;
     RECT  14.364 76.505 14.958 76.585 ;
     RECT  15.804 76.351 17.442 76.585 ;
     RECT  115.704 76.493 118.026 76.613 ;
     RECT  134.028 76.379 138.114 76.613 ;
     RECT  195.768 76.441 197.097 76.613 ;
     RECT  118.872 76.469 133.29 76.621 ;
     RECT  134.028 76.613 138.078 76.621 ;
     RECT  151.56 76.045 151.65 76.621 ;
     RECT  65.52 76.441 75.834 76.649 ;
     RECT  5.364 76.397 6.462 76.711 ;
     RECT  7.2 76.469 10.494 76.711 ;
     RECT  65.556 76.649 75.834 76.733 ;
     RECT  82.404 76.493 114.966 76.739 ;
     RECT  115.74 76.613 118.026 76.739 ;
     RECT  152.712 76.549 152.73 76.739 ;
     RECT  201.204 76.379 201.366 76.739 ;
     RECT  82.404 76.739 114.93 76.775 ;
     RECT  118.872 76.621 138.078 76.775 ;
     RECT  150.408 75.803 150.534 76.775 ;
     RECT  201.204 76.739 201.222 76.775 ;
     RECT  82.404 76.775 92.286 76.783 ;
     RECT  12.132 76.747 12.15 76.784 ;
     RECT  27.324 76.541 37.566 76.795 ;
     RECT  38.556 75.929 63.054 76.795 ;
     RECT  27.324 76.795 63.054 76.811 ;
     RECT  151.272 76.621 151.65 76.811 ;
     RECT  93.168 76.775 114.93 76.847 ;
     RECT  82.368 76.783 92.286 76.855 ;
     RECT  148.215 72.959 148.497 76.891 ;
     RECT  149.436 76.621 149.454 76.891 ;
     RECT  151.272 76.811 151.614 76.891 ;
     RECT  82.332 76.855 92.286 76.919 ;
     RECT  65.628 76.733 75.834 76.939 ;
     RECT  76.86 76.235 81.522 76.981 ;
     RECT  82.332 76.919 86.922 76.981 ;
     RECT  14.364 76.585 17.442 77.009 ;
     RECT  118.872 76.775 138.042 77.009 ;
     RECT  118.872 77.009 133.254 77.045 ;
     RECT  134.028 77.009 137.97 77.045 ;
     RECT  202.215 76.379 214.866 77.081 ;
     RECT  13.14 75.965 13.497 77.083 ;
     RECT  18.615 76.541 26.586 77.089 ;
     RECT  118.872 77.045 132.606 77.117 ;
     RECT  2.304 76.585 4.59 77.125 ;
     RECT  5.364 76.711 10.494 77.125 ;
     RECT  13.14 77.083 13.626 77.125 ;
     RECT  65.628 76.939 75.978 77.125 ;
     RECT  76.788 76.981 86.922 77.125 ;
     RECT  65.628 77.125 86.922 77.126 ;
     RECT  148.215 76.891 149.454 77.153 ;
     RECT  12.996 77.125 13.626 77.161 ;
     RECT  202.215 77.081 214.83 77.189 ;
     RECT  12.456 77.161 13.626 77.251 ;
     RECT  14.364 77.009 16.434 77.251 ;
     RECT  18.54 77.089 26.586 77.279 ;
     RECT  65.628 77.126 86.886 77.279 ;
     RECT  135.36 77.045 137.826 77.279 ;
     RECT  115.776 76.739 118.026 77.323 ;
     RECT  134.028 77.045 134.226 77.357 ;
     RECT  118.872 77.117 132.534 77.36 ;
     RECT  18.54 77.279 25.074 77.371 ;
     RECT  134.136 77.357 134.226 77.387 ;
     RECT  135.36 77.279 137.79 77.387 ;
     RECT  1.764 77.125 10.494 77.395 ;
     RECT  25.884 77.279 26.586 77.431 ;
     RECT  27.324 76.811 28.53 77.431 ;
     RECT  118.872 77.36 132.498 77.453 ;
     RECT  65.628 77.279 81.054 77.459 ;
     RECT  136.728 77.387 137.79 77.459 ;
     RECT  63.864 76.513 64.674 77.515 ;
     RECT  115.776 77.323 118.134 77.515 ;
     RECT  118.872 77.453 129.654 77.515 ;
     RECT  142.815 71.789 143.097 77.515 ;
     RECT  1.728 77.395 10.494 77.521 ;
     RECT  11.484 77.275 11.646 77.521 ;
     RECT  29.268 76.811 63.054 77.521 ;
     RECT  63.864 77.515 64.71 77.521 ;
     RECT  115.776 77.515 129.654 77.521 ;
     RECT  149.436 77.153 149.454 77.521 ;
     RECT  152.46 76.855 152.478 77.521 ;
     RECT  1.728 77.521 11.646 77.549 ;
     RECT  66.384 77.459 81.054 77.549 ;
     RECT  135.36 77.387 135.666 77.549 ;
     RECT  136.8 77.459 137.79 77.555 ;
     RECT  142.815 77.515 143.19 77.555 ;
     RECT  148.215 77.153 148.59 77.555 ;
     RECT  93.24 76.847 114.93 77.557 ;
     RECT  115.74 77.521 129.654 77.557 ;
     RECT  136.8 77.555 137.697 77.585 ;
     RECT  202.215 77.189 214.794 77.585 ;
     RECT  17.46 77.431 17.478 77.593 ;
     RECT  25.884 77.431 28.53 77.593 ;
     RECT  29.268 77.521 64.71 77.593 ;
     RECT  149.436 77.521 149.706 77.597 ;
     RECT  93.24 77.557 129.654 77.621 ;
     RECT  203.472 77.585 214.794 77.657 ;
     RECT  0.144 77.053 0.162 77.665 ;
     RECT  1.764 77.549 11.646 77.665 ;
     RECT  12.456 77.251 16.434 77.665 ;
     RECT  87.696 76.919 92.286 77.665 ;
     RECT  93.24 77.621 129.402 77.665 ;
     RECT  87.696 77.665 129.402 77.729 ;
     RECT  203.616 77.657 214.794 77.729 ;
     RECT  1.764 77.665 16.434 77.755 ;
     RECT  17.46 77.593 17.73 77.755 ;
     RECT  18.468 77.371 25.074 77.755 ;
     RECT  135.36 77.549 135.378 77.819 ;
     RECT  215.82 76.505 215.982 77.819 ;
     RECT  1.764 77.755 25.074 77.837 ;
     RECT  130.536 77.453 132.498 77.855 ;
     RECT  132.015 77.855 132.498 77.885 ;
     RECT  215.82 77.819 215.838 77.891 ;
     RECT  150.84 76.891 151.614 77.899 ;
     RECT  150.516 77.899 151.614 77.935 ;
     RECT  152.352 77.521 152.478 77.935 ;
     RECT  25.884 77.593 64.71 77.963 ;
     RECT  87.696 77.729 129.006 77.963 ;
     RECT  134.424 77.791 134.442 77.971 ;
     RECT  25.884 77.963 63.702 77.981 ;
     RECT  134.424 77.971 134.514 77.999 ;
     RECT  81.864 77.279 86.886 78.043 ;
     RECT  87.696 77.963 128.934 78.043 ;
     RECT  66.708 77.549 81.054 78.061 ;
     RECT  81.864 78.043 128.934 78.061 ;
     RECT  66.708 78.061 128.934 78.077 ;
     RECT  25.884 77.981 63.054 78.089 ;
     RECT  64.548 77.963 64.71 78.089 ;
     RECT  130.536 77.855 131.13 78.089 ;
     RECT  134.496 77.999 134.514 78.089 ;
     RECT  205.38 77.729 214.794 78.089 ;
     RECT  150.516 77.935 152.478 78.097 ;
     RECT  205.524 78.089 214.758 78.125 ;
     RECT  205.524 78.125 210.69 78.161 ;
     RECT  64.656 78.089 64.71 78.169 ;
     RECT  65.628 77.459 65.646 78.169 ;
     RECT  146.484 78.097 146.502 78.169 ;
     RECT  150.516 78.097 152.838 78.169 ;
     RECT  1.8 77.837 25.074 78.205 ;
     RECT  25.884 78.089 35.154 78.205 ;
     RECT  70.452 78.077 128.934 78.221 ;
     RECT  211.5 78.125 214.758 78.233 ;
     RECT  146.484 78.169 146.574 78.269 ;
     RECT  1.8 78.205 35.154 78.317 ;
     RECT  2.304 78.317 35.154 78.359 ;
     RECT  203.616 77.729 204.642 78.359 ;
     RECT  205.524 78.161 210.402 78.359 ;
     RECT  66.708 78.077 69.714 78.368 ;
     RECT  2.304 78.359 16.506 78.395 ;
     RECT  17.316 78.359 35.154 78.395 ;
     RECT  150.48 78.169 152.838 78.395 ;
     RECT  209.556 78.359 210.402 78.395 ;
     RECT  152.784 78.395 152.838 78.439 ;
     RECT  153.615 74.489 160.578 78.439 ;
     RECT  211.788 78.233 214.758 78.503 ;
     RECT  0.108 77.665 0.162 78.509 ;
     RECT  113.292 78.221 128.934 78.539 ;
     RECT  146.484 78.269 146.502 78.539 ;
     RECT  202.215 77.585 202.554 78.539 ;
     RECT  205.74 78.359 208.35 78.539 ;
     RECT  212.112 78.503 214.758 78.539 ;
     RECT  212.112 78.539 214.326 78.584 ;
     RECT  149.436 77.597 149.454 78.601 ;
     RECT  150.48 78.395 152.046 78.601 ;
     RECT  2.304 78.395 16.47 78.629 ;
     RECT  35.928 78.089 63.054 78.629 ;
     RECT  66.708 78.368 69.642 78.629 ;
     RECT  113.292 78.539 128.862 78.629 ;
     RECT  131.112 78.089 131.13 78.629 ;
     RECT  149.436 78.601 152.046 78.629 ;
     RECT  206.244 78.539 208.35 78.629 ;
     RECT  209.556 78.395 209.682 78.629 ;
     RECT  212.112 78.584 213.534 78.629 ;
     RECT  214.272 78.584 214.326 78.629 ;
     RECT  17.316 78.395 21.762 78.665 ;
     RECT  66.708 78.629 69.426 78.665 ;
     RECT  70.452 78.221 112.41 78.665 ;
     RECT  149.436 78.629 151.614 78.665 ;
     RECT  206.244 78.629 206.694 78.665 ;
     RECT  209.556 78.629 209.574 78.665 ;
     RECT  212.112 78.629 212.13 78.665 ;
     RECT  70.56 78.665 112.41 78.701 ;
     RECT  71.892 78.701 112.41 78.737 ;
     RECT  72.072 78.737 84.078 78.809 ;
     RECT  113.292 78.629 128.322 78.809 ;
     RECT  22.788 78.395 35.154 78.899 ;
     RECT  212.868 78.629 213.534 78.899 ;
     RECT  214.308 78.629 214.326 78.899 ;
     RECT  28.224 78.899 35.154 78.907 ;
     RECT  35.928 78.629 41.382 78.907 ;
     RECT  64.656 78.169 65.646 78.907 ;
     RECT  66.708 78.665 67.734 78.907 ;
     RECT  70.56 78.701 71.01 78.935 ;
     RECT  64.656 78.907 67.734 78.943 ;
     RECT  113.292 78.809 128.286 78.971 ;
     RECT  203.616 78.359 204.102 78.971 ;
     RECT  70.632 78.935 71.01 79.007 ;
     RECT  113.292 78.971 127.17 79.007 ;
     RECT  127.944 78.971 128.286 79.007 ;
     RECT  212.868 78.899 213.297 79.007 ;
     RECT  42.156 78.629 63.054 79.043 ;
     RECT  64.62 78.943 67.734 79.043 ;
     RECT  152.784 78.439 160.578 79.079 ;
     RECT  113.292 79.007 119.286 79.085 ;
     RECT  84.888 78.737 112.41 79.141 ;
     RECT  113.292 79.085 114.21 79.141 ;
     RECT  22.824 78.899 27.45 79.169 ;
     RECT  64.62 79.043 64.818 79.169 ;
     RECT  69.084 78.665 69.282 79.169 ;
     RECT  115.056 79.085 119.286 79.169 ;
     RECT  120.06 79.007 127.17 79.169 ;
     RECT  127.944 79.007 128.214 79.169 ;
     RECT  152.892 79.079 160.578 79.169 ;
     RECT  17.316 78.665 21.582 79.205 ;
     RECT  128.052 79.169 128.07 79.205 ;
     RECT  64.62 79.169 64.674 79.213 ;
     RECT  23.616 79.169 27.45 79.229 ;
     RECT  42.192 79.043 63.054 79.229 ;
     RECT  72.432 78.809 84.078 79.229 ;
     RECT  69.084 79.169 69.21 79.241 ;
     RECT  153 79.169 160.578 79.241 ;
     RECT  25.668 79.229 27.45 79.277 ;
     RECT  65.556 79.043 67.734 79.277 ;
     RECT  2.304 78.629 16.326 79.285 ;
     RECT  17.316 79.205 20.574 79.285 ;
     RECT  115.056 79.169 118.458 79.313 ;
     RECT  0.108 78.509 0.126 79.339 ;
     RECT  120.6 79.169 127.17 79.349 ;
     RECT  120.6 79.349 126.954 79.373 ;
     RECT  2.268 79.285 16.326 79.439 ;
     RECT  17.172 79.285 20.574 79.439 ;
     RECT  21.564 79.205 21.582 79.439 ;
     RECT  72.504 79.229 84.078 79.439 ;
     RECT  84.888 79.141 114.21 79.439 ;
     RECT  118.116 79.313 118.458 79.439 ;
     RECT  120.6 79.373 124.434 79.439 ;
     RECT  125.172 79.373 126.954 79.439 ;
     RECT  70.704 79.007 71.01 79.447 ;
     RECT  2.268 79.439 15.318 79.475 ;
     RECT  16.308 79.439 16.326 79.475 ;
     RECT  120.6 79.439 121.662 79.475 ;
     RECT  125.172 79.439 125.874 79.475 ;
     RECT  65.988 79.277 67.734 79.483 ;
     RECT  65.988 79.483 67.806 79.519 ;
     RECT  72.54 79.439 84.078 79.519 ;
     RECT  84.888 79.439 112.05 79.519 ;
     RECT  2.268 79.475 14.85 79.547 ;
     RECT  17.208 79.439 20.322 79.619 ;
     RECT  125.172 79.475 125.262 79.619 ;
     RECT  2.268 79.547 14.526 79.709 ;
     RECT  17.208 79.619 20.178 79.709 ;
     RECT  25.668 79.277 27.27 79.709 ;
     RECT  70.704 79.447 71.298 79.709 ;
     RECT  115.056 79.313 117.342 79.709 ;
     RECT  122.544 79.439 124.398 79.709 ;
     RECT  126.615 79.439 126.954 79.709 ;
     RECT  2.268 79.709 14.418 79.745 ;
     RECT  25.776 79.709 26.406 79.745 ;
     RECT  115.056 79.709 117.27 79.745 ;
     RECT  122.544 79.709 123.39 79.745 ;
     RECT  149.868 78.665 151.614 79.753 ;
     RECT  65.988 79.519 67.842 79.757 ;
     RECT  124.38 79.709 124.398 79.757 ;
     RECT  17.208 79.709 19.962 79.781 ;
     RECT  25.776 79.745 26.154 79.781 ;
     RECT  70.704 79.709 71.19 79.781 ;
     RECT  122.544 79.745 123.246 79.781 ;
     RECT  120.6 79.475 121.59 79.805 ;
     RECT  122.544 79.781 123.102 79.805 ;
     RECT  28.224 78.907 41.382 79.825 ;
     RECT  42.192 79.229 62.982 79.825 ;
     RECT  17.676 79.781 19.962 79.853 ;
     RECT  0.108 79.339 0.162 79.861 ;
     RECT  28.224 79.825 62.982 79.861 ;
     RECT  112.788 79.439 114.21 79.861 ;
     RECT  17.748 79.853 19.962 79.889 ;
     RECT  72.54 79.519 112.05 79.889 ;
     RECT  195.768 76.613 195.786 79.889 ;
     RECT  2.268 79.745 13.698 79.949 ;
     RECT  2.304 79.949 13.698 79.979 ;
     RECT  16.38 79.483 16.398 79.979 ;
     RECT  73.728 79.889 112.05 79.979 ;
     RECT  69.048 79.951 69.066 79.987 ;
     RECT  112.788 79.861 114.282 79.987 ;
     RECT  21.492 79.951 21.51 79.997 ;
     RECT  2.304 79.979 12.474 80.015 ;
     RECT  18.504 79.889 19.962 80.015 ;
     RECT  73.728 79.979 87.39 80.015 ;
     RECT  115.056 79.745 117.234 80.015 ;
     RECT  69.048 79.987 69.174 80.053 ;
     RECT  66.42 79.757 67.842 80.059 ;
     RECT  112.788 79.987 114.318 80.059 ;
     RECT  115.056 80.015 116.838 80.059 ;
     RECT  72.54 79.889 72.99 80.087 ;
     RECT  206.676 78.665 206.694 80.087 ;
     RECT  68.976 80.053 69.174 80.093 ;
     RECT  24.015 79.229 24.297 80.095 ;
     RECT  28.152 79.861 62.982 80.123 ;
     RECT  203.616 78.971 203.634 80.123 ;
     RECT  22.824 79.169 22.842 80.131 ;
     RECT  24.015 80.095 24.822 80.131 ;
     RECT  64.188 79.213 64.674 80.131 ;
     RECT  88.236 79.979 112.05 80.132 ;
     RECT  69.048 80.093 69.174 80.141 ;
     RECT  69.084 80.141 69.174 80.159 ;
     RECT  149.868 79.753 151.65 80.159 ;
     RECT  196.524 76.613 197.097 80.159 ;
     RECT  0.108 79.861 0.558 80.237 ;
     RECT  2.304 80.015 11.97 80.249 ;
     RECT  22.428 80.131 25.002 80.249 ;
     RECT  25.776 79.781 25.974 80.249 ;
     RECT  28.152 80.123 62.874 80.249 ;
     RECT  64.008 80.131 64.674 80.257 ;
     RECT  18.615 80.015 19.962 80.285 ;
     RECT  22.428 80.249 24.297 80.285 ;
     RECT  25.776 80.249 25.794 80.285 ;
     RECT  28.152 80.249 28.17 80.285 ;
     RECT  22.968 80.285 22.986 80.321 ;
     RECT  28.908 80.249 30.51 80.321 ;
     RECT  2.304 80.249 10.998 80.333 ;
     RECT  0.216 80.237 0.558 80.357 ;
     RECT  66.42 80.059 67.878 80.357 ;
     RECT  88.272 80.132 112.05 80.365 ;
     RECT  112.788 80.059 116.838 80.365 ;
     RECT  31.356 80.249 62.874 80.393 ;
     RECT  70.704 79.781 71.118 80.401 ;
     RECT  152.784 80.293 152.802 80.401 ;
     RECT  32.94 80.393 62.874 80.429 ;
     RECT  72.54 80.087 72.897 80.443 ;
     RECT  2.304 80.333 10.494 80.519 ;
     RECT  31.356 80.393 31.842 80.519 ;
     RECT  69.516 80.293 69.534 80.519 ;
     RECT  152.784 80.401 152.838 80.519 ;
     RECT  70.416 80.401 71.118 80.539 ;
     RECT  71.928 80.443 72.897 80.539 ;
     RECT  2.304 80.519 10.278 80.555 ;
     RECT  31.356 80.519 31.482 80.555 ;
     RECT  151.164 80.159 151.65 80.563 ;
     RECT  152.784 80.519 152.802 80.563 ;
     RECT  151.164 80.563 151.758 80.599 ;
     RECT  152.532 80.563 152.802 80.599 ;
     RECT  120.6 79.805 121.497 80.621 ;
     RECT  63.864 80.257 64.674 80.663 ;
     RECT  207.615 78.629 208.35 80.663 ;
     RECT  0.54 80.357 0.558 80.683 ;
     RECT  194.796 75.497 194.814 80.699 ;
     RECT  73.728 80.015 87.318 80.761 ;
     RECT  118.44 79.439 118.458 80.761 ;
     RECT  2.304 80.555 9.774 80.789 ;
     RECT  19.944 80.285 19.962 80.789 ;
     RECT  88.272 80.365 116.838 80.789 ;
     RECT  70.416 80.539 72.897 80.827 ;
     RECT  73.728 80.761 87.354 80.833 ;
     RECT  73.728 80.833 87.498 80.861 ;
     RECT  13.215 79.979 13.698 80.869 ;
     RECT  70.416 80.827 72.99 80.869 ;
     RECT  73.728 80.861 73.818 80.897 ;
     RECT  118.26 80.761 118.458 80.905 ;
     RECT  151.164 80.599 152.802 80.905 ;
     RECT  0.54 80.683 1.17 80.909 ;
     RECT  13.215 80.869 13.914 80.909 ;
     RECT  13.215 80.909 13.497 80.923 ;
     RECT  66.708 80.357 67.878 80.941 ;
     RECT  74.664 80.861 87.498 80.941 ;
     RECT  88.272 80.789 95.202 80.941 ;
     RECT  117.864 80.905 118.458 80.941 ;
     RECT  149.868 80.159 150.138 80.941 ;
     RECT  151.056 80.905 152.802 80.941 ;
     RECT  23.904 80.285 24.297 80.969 ;
     RECT  13.104 80.923 13.497 80.971 ;
     RECT  64.008 80.663 64.674 81.031 ;
     RECT  65.556 80.905 65.574 81.031 ;
     RECT  66.708 80.941 68.058 81.031 ;
     RECT  25.092 80.923 25.11 81.053 ;
     RECT  28.908 80.321 29.898 81.059 ;
     RECT  74.664 80.941 95.202 81.059 ;
     RECT  117.864 80.941 118.53 81.059 ;
     RECT  149.868 80.941 152.802 81.059 ;
     RECT  2.304 80.789 9.702 81.101 ;
     RECT  74.7 81.059 95.202 81.149 ;
     RECT  95.94 80.789 116.838 81.163 ;
     RECT  66.708 81.031 68.562 81.167 ;
     RECT  64.008 81.031 65.574 81.197 ;
     RECT  66.708 81.167 68.382 81.203 ;
     RECT  95.94 81.163 117.018 81.203 ;
     RECT  123.084 79.805 123.102 81.203 ;
     RECT  70.308 80.869 72.99 81.211 ;
     RECT  150.624 81.059 152.802 81.239 ;
     RECT  0.108 81.175 0.126 81.293 ;
     RECT  150.624 81.239 152.622 81.329 ;
     RECT  153.615 79.241 160.578 81.337 ;
     RECT  146.484 81.163 146.502 81.341 ;
     RECT  12.456 80.971 13.497 81.365 ;
     RECT  74.916 81.149 95.202 81.365 ;
     RECT  28.908 81.059 29.697 81.373 ;
     RECT  75.024 81.365 95.202 81.401 ;
     RECT  69.696 81.211 73.134 81.437 ;
     RECT  65.412 81.197 65.574 81.481 ;
     RECT  64.008 81.197 64.494 81.485 ;
     RECT  64.008 81.485 64.422 81.509 ;
     RECT  69.696 81.437 73.062 81.509 ;
     RECT  12.528 81.365 13.497 81.599 ;
     RECT  27.36 81.409 27.378 81.599 ;
     RECT  88.596 81.401 95.202 81.607 ;
     RECT  95.94 81.203 116.946 81.607 ;
     RECT  2.304 81.101 8.802 81.643 ;
     RECT  149.868 81.059 149.886 81.671 ;
     RECT  141.516 81.571 141.534 81.677 ;
     RECT  69.696 81.509 73.026 81.679 ;
     RECT  1.152 80.909 1.17 81.715 ;
     RECT  9.684 81.101 9.702 81.751 ;
     RECT  0.54 81.715 1.17 81.869 ;
     RECT  150.624 81.329 152.586 81.869 ;
     RECT  1.152 81.869 1.17 81.905 ;
     RECT  69.192 81.679 73.026 81.905 ;
     RECT  124.236 81.715 124.254 81.913 ;
     RECT  123.732 81.913 124.254 81.931 ;
     RECT  152.532 81.869 152.586 81.941 ;
     RECT  69.444 81.905 73.026 81.965 ;
     RECT  69.444 81.965 70.83 81.977 ;
     RECT  150.624 81.869 151.614 81.979 ;
     RECT  9.684 81.751 10.422 81.985 ;
     RECT  65.412 81.481 66.222 82.013 ;
     RECT  2.268 81.643 8.802 82.021 ;
     RECT  9.684 81.985 10.494 82.021 ;
     RECT  88.596 81.607 116.946 82.021 ;
     RECT  117.864 81.059 118.458 82.021 ;
     RECT  122.616 81.985 122.634 82.021 ;
     RECT  2.268 82.021 10.494 82.027 ;
     RECT  88.596 82.021 118.458 82.049 ;
     RECT  67.215 81.203 68.382 82.111 ;
     RECT  123.732 81.931 124.326 82.111 ;
     RECT  65.916 82.013 66.222 82.123 ;
     RECT  67.215 82.111 68.706 82.123 ;
     RECT  148.215 77.555 148.497 82.123 ;
     RECT  153.432 81.337 160.578 82.139 ;
     RECT  121.215 80.621 121.497 82.147 ;
     RECT  122.616 82.021 122.778 82.147 ;
     RECT  148.215 82.123 148.878 82.175 ;
     RECT  150.444 81.979 151.614 82.175 ;
     RECT  88.596 82.049 113.778 82.183 ;
     RECT  120.888 82.147 121.497 82.183 ;
     RECT  122.616 82.147 122.85 82.183 ;
     RECT  69.48 81.977 70.83 82.211 ;
     RECT  28.764 81.373 29.697 82.219 ;
     RECT  75.024 81.401 87.75 82.219 ;
     RECT  88.524 82.183 113.778 82.219 ;
     RECT  114.516 82.049 118.458 82.219 ;
     RECT  119.34 80.635 119.358 82.219 ;
     RECT  120.888 82.183 122.85 82.219 ;
     RECT  123.624 82.111 124.326 82.219 ;
     RECT  75.024 82.219 113.778 82.255 ;
     RECT  2.232 82.027 10.494 82.283 ;
     RECT  114.516 82.219 119.358 82.283 ;
     RECT  120.888 82.219 124.326 82.283 ;
     RECT  28.512 82.219 29.697 82.291 ;
     RECT  30.924 82.147 30.942 82.291 ;
     RECT  64.08 81.509 64.422 82.291 ;
     RECT  117.72 82.283 119.358 82.291 ;
     RECT  117.72 82.291 119.682 82.319 ;
     RECT  120.924 82.283 124.326 82.319 ;
     RECT  114.516 82.283 116.658 82.349 ;
     RECT  26.064 81.985 26.73 82.381 ;
     RECT  33.012 80.429 62.874 82.409 ;
     RECT  74.664 82.255 113.778 82.409 ;
     RECT  114.66 82.349 116.658 82.409 ;
     RECT  148.215 82.175 148.734 82.409 ;
     RECT  150.444 82.175 151.506 82.409 ;
     RECT  27.504 82.021 27.522 82.417 ;
     RECT  28.332 82.291 31.878 82.417 ;
     RECT  2.268 82.283 10.494 82.445 ;
     RECT  27.504 82.417 31.878 82.445 ;
     RECT  63.9 82.291 64.422 82.445 ;
     RECT  65.916 82.123 68.706 82.445 ;
     RECT  74.664 82.409 81.63 82.445 ;
     RECT  82.368 82.409 113.418 82.445 ;
     RECT  114.66 82.409 116.514 82.445 ;
     RECT  71.748 81.965 73.026 82.481 ;
     RECT  82.728 82.445 113.418 82.481 ;
     RECT  64.08 82.445 64.422 82.489 ;
     RECT  64.08 82.489 64.458 82.517 ;
     RECT  82.728 82.481 112.842 82.517 ;
     RECT  27.504 82.445 31.482 82.553 ;
     RECT  118.656 82.319 119.682 82.553 ;
     RECT  2.304 82.445 10.494 82.561 ;
     RECT  11.376 82.525 11.394 82.561 ;
     RECT  25.128 82.381 26.73 82.561 ;
     RECT  27.504 82.553 31.41 82.561 ;
     RECT  25.128 82.561 31.41 82.589 ;
     RECT  114.66 82.445 116.406 82.589 ;
     RECT  120.924 82.319 122.454 82.589 ;
     RECT  123.228 82.319 124.326 82.589 ;
     RECT  74.664 82.445 81.414 82.651 ;
     RECT  2.304 82.561 11.538 82.679 ;
     RECT  112.536 82.517 112.842 82.679 ;
     RECT  114.66 82.589 116.097 82.679 ;
     RECT  117.72 82.319 117.882 82.679 ;
     RECT  119.664 82.553 119.682 82.679 ;
     RECT  121.215 82.589 122.454 82.679 ;
     RECT  21.132 82.651 21.15 82.687 ;
     RECT  69.696 82.211 70.83 82.687 ;
     RECT  72.216 82.481 73.026 82.687 ;
     RECT  150.444 82.409 151.074 82.687 ;
     RECT  121.215 82.679 122.274 82.688 ;
     RECT  74.016 82.651 81.414 82.715 ;
     RECT  112.788 82.679 112.842 82.715 ;
     RECT  114.66 82.679 114.678 82.715 ;
     RECT  115.416 82.679 116.097 82.715 ;
     RECT  118.656 82.553 118.674 82.715 ;
     RECT  153.54 82.139 160.578 82.733 ;
     RECT  69.696 82.687 70.902 82.747 ;
     RECT  123.372 82.589 124.326 82.747 ;
     RECT  17.136 82.381 17.154 82.751 ;
     RECT  25.128 82.589 31.338 82.751 ;
     RECT  64.188 82.517 64.458 82.823 ;
     RECT  123.372 82.747 124.434 82.823 ;
     RECT  140.328 82.291 140.346 82.823 ;
     RECT  150.408 82.687 151.074 82.823 ;
     RECT  18.615 80.285 18.897 82.831 ;
     RECT  20.736 82.687 21.15 82.831 ;
     RECT  112.824 82.715 112.842 82.859 ;
     RECT  18.252 82.831 18.897 82.921 ;
     RECT  19.872 82.831 21.15 82.949 ;
     RECT  26.532 82.751 31.338 82.949 ;
     RECT  33.012 82.409 62.838 82.949 ;
     RECT  65.916 82.445 68.526 82.949 ;
     RECT  69.696 82.747 71.406 82.949 ;
     RECT  25.128 82.751 25.686 82.985 ;
     RECT  34.092 82.949 62.838 82.985 ;
     RECT  117.792 82.679 117.81 82.985 ;
     RECT  0.108 82.219 0.162 82.987 ;
     RECT  123.48 82.823 124.434 82.987 ;
     RECT  115.524 82.715 116.097 83.021 ;
     RECT  123.48 82.987 124.83 83.021 ;
     RECT  64.404 82.823 64.458 83.029 ;
     RECT  65.916 82.949 68.49 83.035 ;
     RECT  12.312 82.795 12.33 83.065 ;
     RECT  13.215 81.599 13.497 83.065 ;
     RECT  19.872 82.949 19.89 83.069 ;
     RECT  132.015 77.885 132.297 83.083 ;
     RECT  142.815 77.555 143.097 83.083 ;
     RECT  0.108 82.987 0.342 83.093 ;
     RECT  34.308 82.985 62.838 83.093 ;
     RECT  14.832 82.831 14.85 83.101 ;
     RECT  22.824 82.759 22.842 83.101 ;
     RECT  0.324 83.093 0.342 83.117 ;
     RECT  150.48 82.823 151.074 83.117 ;
     RECT  131.904 83.083 132.297 83.129 ;
     RECT  142.704 83.083 143.097 83.129 ;
     RECT  2.304 82.679 11.502 83.179 ;
     RECT  12.312 83.065 13.497 83.191 ;
     RECT  14.688 83.101 14.85 83.191 ;
     RECT  82.728 82.517 111.762 83.191 ;
     RECT  74.016 82.715 81.126 83.213 ;
     RECT  34.56 83.093 62.838 83.219 ;
     RECT  72.216 82.687 73.134 83.219 ;
     RECT  82.692 83.191 111.762 83.219 ;
     RECT  123.48 83.021 124.038 83.219 ;
     RECT  124.812 83.021 124.83 83.219 ;
     RECT  150.696 83.117 151.074 83.219 ;
     RECT  82.692 83.219 100.746 83.227 ;
     RECT  72.324 83.219 73.134 83.255 ;
     RECT  101.484 83.219 111.726 83.255 ;
     RECT  153.54 82.733 160.542 83.255 ;
     RECT  65.772 83.035 68.49 83.261 ;
     RECT  34.776 83.219 62.838 83.263 ;
     RECT  25.668 82.985 25.686 83.291 ;
     RECT  64.404 83.029 64.638 83.291 ;
     RECT  108.396 83.255 111.726 83.291 ;
     RECT  69.732 82.949 71.406 83.309 ;
     RECT  74.088 83.213 81.126 83.327 ;
     RECT  12.276 83.191 13.497 83.335 ;
     RECT  14.688 83.191 14.958 83.335 ;
     RECT  17.64 82.921 18.897 83.335 ;
     RECT  24.015 80.969 24.297 83.335 ;
     RECT  30.78 82.949 31.338 83.335 ;
     RECT  81.972 83.227 100.746 83.357 ;
     RECT  2.268 83.179 11.502 83.363 ;
     RECT  34.776 83.263 62.874 83.363 ;
     RECT  65.988 83.261 68.49 83.363 ;
     RECT  80.1 83.327 81.126 83.363 ;
     RECT  108.468 83.291 111.726 83.363 ;
     RECT  14.688 83.335 15.426 83.371 ;
     RECT  20.664 82.949 21.15 83.371 ;
     RECT  90.144 83.357 100.746 83.405 ;
     RECT  12.276 83.335 13.698 83.461 ;
     RECT  80.172 83.363 81.126 83.461 ;
     RECT  81.972 83.357 89.37 83.461 ;
     RECT  152.568 81.941 152.586 83.461 ;
     RECT  22.824 83.101 22.878 83.467 ;
     RECT  24.015 83.335 24.894 83.467 ;
     RECT  20.664 83.371 21.474 83.489 ;
     RECT  26.532 82.949 29.97 83.489 ;
     RECT  30.78 83.335 31.806 83.489 ;
     RECT  72.396 83.255 73.134 83.489 ;
     RECT  74.088 83.327 79.326 83.489 ;
     RECT  93.24 83.405 100.746 83.489 ;
     RECT  12.276 83.461 13.77 83.497 ;
     RECT  14.688 83.371 15.822 83.497 ;
     RECT  26.532 83.489 26.766 83.497 ;
     RECT  64.62 83.291 64.638 83.497 ;
     RECT  21.456 83.489 21.474 83.501 ;
     RECT  30.78 83.489 31.734 83.501 ;
     RECT  80.172 83.461 89.37 83.501 ;
     RECT  34.776 83.363 62.838 83.525 ;
     RECT  64.62 83.497 64.818 83.525 ;
     RECT  101.484 83.255 107.586 83.525 ;
     RECT  108.468 83.363 110.898 83.525 ;
     RECT  64.8 83.525 64.818 83.533 ;
     RECT  72.504 83.489 73.134 83.56 ;
     RECT  72.504 83.56 73.206 83.561 ;
     RECT  101.556 83.525 107.586 83.561 ;
     RECT  123.48 83.219 123.606 83.561 ;
     RECT  23.904 83.467 24.894 83.569 ;
     RECT  72.615 83.561 73.206 83.597 ;
     RECT  108.504 83.525 110.898 83.597 ;
     RECT  2.304 83.363 11.502 83.605 ;
     RECT  12.276 83.497 15.822 83.605 ;
     RECT  17.64 83.335 18.954 83.605 ;
     RECT  34.815 83.525 62.802 83.633 ;
     RECT  64.8 83.533 64.962 83.633 ;
     RECT  66.708 83.363 68.49 83.633 ;
     RECT  90.144 83.405 92.358 83.633 ;
     RECT  95.868 83.489 100.746 83.633 ;
     RECT  108.504 83.597 110.826 83.633 ;
     RECT  22.608 83.467 22.878 83.641 ;
     RECT  152.568 83.461 152.73 83.641 ;
     RECT  30.852 83.501 31.734 83.645 ;
     RECT  80.172 83.501 81.414 83.669 ;
     RECT  108.504 83.633 110.754 83.669 ;
     RECT  123.48 83.561 123.498 83.669 ;
     RECT  0.54 83.605 0.558 83.693 ;
     RECT  34.815 83.633 62.097 83.759 ;
     RECT  64.8 83.633 64.89 83.759 ;
     RECT  66.744 83.633 68.49 83.759 ;
     RECT  72.615 83.597 73.026 83.759 ;
     RECT  80.172 83.669 80.262 83.759 ;
     RECT  81 83.669 81.414 83.759 ;
     RECT  82.188 83.501 89.37 83.759 ;
     RECT  90.144 83.633 91.026 83.759 ;
     RECT  91.8 83.633 92.358 83.759 ;
     RECT  93.24 83.489 95.13 83.759 ;
     RECT  96.264 83.633 100.746 83.759 ;
     RECT  101.556 83.561 103.014 83.759 ;
     RECT  104.004 83.561 107.586 83.759 ;
     RECT  121.215 82.688 122.022 83.759 ;
     RECT  151.056 83.219 151.074 83.759 ;
     RECT  152.46 83.641 152.73 83.759 ;
     RECT  153.576 83.255 160.542 83.759 ;
     RECT  80.172 83.759 80.19 83.789 ;
     RECT  92.16 83.759 92.358 83.789 ;
     RECT  20.664 83.489 20.682 83.795 ;
     RECT  30.852 83.645 31.302 83.795 ;
     RECT  69.732 83.309 71.334 83.795 ;
     RECT  76.608 83.489 79.326 83.795 ;
     RECT  81 83.759 81.27 83.795 ;
     RECT  82.332 83.759 89.334 83.795 ;
     RECT  93.24 83.759 93.474 83.795 ;
     RECT  94.215 83.759 95.058 83.795 ;
     RECT  96.264 83.759 96.282 83.795 ;
     RECT  97.38 83.759 100.746 83.795 ;
     RECT  101.556 83.759 102.294 83.795 ;
     RECT  104.004 83.759 107.226 83.795 ;
     RECT  108.504 83.669 110.697 83.795 ;
     RECT  152.568 83.759 152.586 83.795 ;
     RECT  17.28 83.605 18.954 83.803 ;
     RECT  109.476 83.795 110.697 83.831 ;
     RECT  74.088 83.489 75.69 83.837 ;
     RECT  153.615 83.759 160.542 83.837 ;
     RECT  22.608 83.641 23.058 83.839 ;
     RECT  108.504 83.795 108.594 83.867 ;
     RECT  33.012 82.949 33.282 83.875 ;
     RECT  66.744 83.759 68.418 83.903 ;
     RECT  2.304 83.605 15.966 83.911 ;
     RECT  17.28 83.803 18.99 83.911 ;
     RECT  22.536 83.839 23.058 83.911 ;
     RECT  23.868 83.569 24.894 83.911 ;
     RECT  33.012 83.875 33.354 83.911 ;
     RECT  36.288 83.759 62.097 83.987 ;
     RECT  67.215 83.903 68.418 83.987 ;
     RECT  76.608 83.795 78.297 83.987 ;
     RECT  97.38 83.795 99.897 83.987 ;
     RECT  109.548 83.831 110.697 83.987 ;
     RECT  115.815 83.021 116.097 83.987 ;
     RECT  121.215 83.759 121.497 83.987 ;
     RECT  126.615 79.709 126.897 83.987 ;
     RECT  132.015 83.129 132.297 83.987 ;
     RECT  137.415 77.585 137.697 83.987 ;
     RECT  142.815 83.129 143.097 83.987 ;
     RECT  148.215 82.409 148.497 83.987 ;
     RECT  153.615 83.837 160.506 83.987 ;
     RECT  74.664 83.837 75.69 84.029 ;
     RECT  82.728 83.795 89.334 84.029 ;
     RECT  93.24 83.795 93.258 84.029 ;
     RECT  97.38 83.987 99.705 84.029 ;
     RECT  104.148 83.795 104.166 84.029 ;
     RECT  104.94 83.795 107.226 84.029 ;
     RECT  2.304 83.911 16.218 84.037 ;
     RECT  17.28 83.911 19.026 84.037 ;
     RECT  68.076 83.987 68.418 84.065 ;
     RECT  74.664 84.029 75.258 84.065 ;
     RECT  76.608 83.987 78.105 84.065 ;
     RECT  82.728 84.029 83.574 84.065 ;
     RECT  84.384 84.029 85.158 84.065 ;
     RECT  88.38 84.029 89.334 84.065 ;
     RECT  92.16 83.789 92.178 84.065 ;
     RECT  101.664 83.795 102.294 84.065 ;
     RECT  106.344 84.029 107.226 84.065 ;
     RECT  154.512 83.987 160.506 84.065 ;
     RECT  32.832 83.911 33.354 84.073 ;
     RECT  2.304 84.037 19.026 84.077 ;
     RECT  69.732 83.795 71.262 84.101 ;
     RECT  22.536 83.911 25.182 84.109 ;
     RECT  27.54 83.489 29.97 84.109 ;
     RECT  68.4 84.065 68.418 84.137 ;
     RECT  84.42 84.065 85.158 84.173 ;
     RECT  98.244 84.029 99.705 84.173 ;
     RECT  27.54 84.109 30.042 84.181 ;
     RECT  36.288 83.987 61.905 84.209 ;
     RECT  79.308 83.795 79.326 84.209 ;
     RECT  81 83.795 81.126 84.209 ;
     RECT  90.144 83.759 90.918 84.209 ;
     RECT  104.976 84.029 105.105 84.209 ;
     RECT  106.74 84.065 107.226 84.209 ;
     RECT  37.368 84.209 61.905 84.257 ;
     RECT  67.215 83.987 67.305 84.257 ;
     RECT  72.615 83.759 72.99 84.257 ;
     RECT  76.86 84.065 78.105 84.257 ;
     RECT  82.728 84.065 83.505 84.257 ;
     RECT  88.815 84.065 89.334 84.257 ;
     RECT  94.215 83.795 94.734 84.257 ;
     RECT  99.615 84.173 99.705 84.257 ;
     RECT  105.015 84.209 105.105 84.257 ;
     RECT  109.548 83.987 110.505 84.257 ;
     RECT  115.815 83.987 115.905 84.257 ;
     RECT  121.215 83.987 121.305 84.257 ;
     RECT  126.615 83.987 126.705 84.257 ;
     RECT  132.015 83.987 132.105 84.257 ;
     RECT  137.415 83.987 137.505 84.257 ;
     RECT  142.815 83.987 142.905 84.257 ;
     RECT  148.215 83.987 148.305 84.257 ;
     RECT  153.615 83.987 153.705 84.257 ;
     RECT  26.244 83.497 26.766 84.271 ;
     RECT  31.068 83.795 31.302 84.299 ;
     RECT  76.86 84.257 77.634 84.299 ;
     RECT  85.896 84.029 85.914 84.299 ;
     RECT  94.644 84.257 94.734 84.299 ;
     RECT  107.208 84.209 107.226 84.299 ;
     RECT  15.696 84.077 19.026 84.307 ;
     RECT  25.992 84.271 26.766 84.307 ;
     RECT  27.54 84.181 30.114 84.307 ;
     RECT  22.536 84.109 25.254 84.331 ;
     RECT  32.796 84.073 33.354 84.331 ;
     RECT  72.972 84.257 72.99 84.335 ;
     RECT  76.86 84.299 77.562 84.335 ;
     RECT  81 84.209 81.09 84.335 ;
     RECT  84.42 84.173 84.438 84.335 ;
     RECT  101.736 84.065 102.294 84.335 ;
     RECT  108.504 83.867 108.522 84.335 ;
     RECT  34.815 83.759 35.37 84.343 ;
     RECT  15.696 84.307 19.206 84.379 ;
     RECT  22.176 84.331 25.254 84.379 ;
     RECT  25.992 84.307 30.114 84.379 ;
     RECT  74.916 84.065 75.258 84.407 ;
     RECT  109.548 84.257 110.358 84.407 ;
     RECT  74.916 84.407 74.934 84.443 ;
     RECT  81 84.335 81.018 84.443 ;
     RECT  97.38 84.029 97.398 84.443 ;
     RECT  32.796 84.331 33.678 84.451 ;
     RECT  76.86 84.335 76.878 84.479 ;
     RECT  15.696 84.379 19.926 84.523 ;
     RECT  71.244 84.101 71.262 84.524 ;
     RECT  90.9 84.209 90.918 84.524 ;
     RECT  15.696 84.523 20.502 84.541 ;
     RECT  32.652 84.451 33.678 84.605 ;
     RECT  15.696 84.541 21.15 84.613 ;
     RECT  34.668 84.343 35.37 84.613 ;
     RECT  36.288 84.209 36.378 84.613 ;
     RECT  2.304 84.077 14.886 84.641 ;
     RECT  15.696 84.613 21.402 84.649 ;
     RECT  22.176 84.379 30.114 84.649 ;
     RECT  34.668 84.613 36.378 84.649 ;
     RECT  15.696 84.649 30.114 84.685 ;
     RECT  32.724 84.605 33.678 84.685 ;
     RECT  34.488 84.649 36.378 84.685 ;
     RECT  0.108 83.947 0.162 84.712 ;
     RECT  69.732 84.101 69.75 84.713 ;
     RECT  0.108 84.712 0.198 84.749 ;
     RECT  32.724 84.685 36.378 84.839 ;
     RECT  31.104 84.299 31.302 84.847 ;
     RECT  15.696 84.685 30.15 84.911 ;
     RECT  32.796 84.839 36.378 84.955 ;
     RECT  37.368 84.257 61.722 84.955 ;
     RECT  101.736 84.335 101.826 84.983 ;
     RECT  94.716 84.299 94.734 85.019 ;
     RECT  15.696 84.911 21.438 85.109 ;
     RECT  22.284 84.911 30.15 85.217 ;
     RECT  100.728 83.795 100.746 85.217 ;
     RECT  32.796 84.955 61.722 85.229 ;
     RECT  82.728 84.257 82.746 85.253 ;
     RECT  25.092 85.217 30.15 85.379 ;
     RECT  90.144 84.209 90.162 85.379 ;
     RECT  25.092 85.379 28.422 85.415 ;
     RECT  29.232 85.379 30.15 85.415 ;
     RECT  2.304 84.641 8.298 85.423 ;
     RECT  0.108 84.749 0.162 85.483 ;
     RECT  9.144 84.641 14.886 85.483 ;
     RECT  89.316 84.257 89.334 85.487 ;
     RECT  31.104 84.847 31.41 85.495 ;
     RECT  29.415 85.415 30.15 85.531 ;
     RECT  30.924 85.495 31.41 85.531 ;
     RECT  2.304 85.423 8.334 85.657 ;
     RECT  9.108 85.483 14.886 85.657 ;
     RECT  32.796 85.229 36.378 85.657 ;
     RECT  32.58 85.657 36.378 85.709 ;
     RECT  25.092 85.415 28.278 85.721 ;
     RECT  32.58 85.709 33.966 85.721 ;
     RECT  34.74 85.709 36.378 85.721 ;
     RECT  2.304 85.657 14.886 85.729 ;
     RECT  15.696 85.109 21.402 85.729 ;
     RECT  22.284 85.217 24.354 85.729 ;
     RECT  37.116 85.229 61.722 85.757 ;
     RECT  29.415 85.531 31.41 85.765 ;
     RECT  29.415 85.765 31.806 85.891 ;
     RECT  32.58 85.721 33.894 85.891 ;
     RECT  2.304 85.729 21.402 85.919 ;
     RECT  25.092 85.721 28.026 85.919 ;
     RECT  18 85.919 21.402 85.927 ;
     RECT  22.212 85.729 24.354 85.927 ;
     RECT  2.304 85.919 17.226 85.955 ;
     RECT  34.776 85.721 36.198 85.991 ;
     RECT  18 85.927 24.354 85.999 ;
     RECT  25.092 85.919 25.686 85.999 ;
     RECT  37.116 85.757 55.638 86.035 ;
     RECT  29.415 85.891 33.894 86.045 ;
     RECT  0.108 85.483 0.558 86.063 ;
     RECT  32.256 86.045 33.894 86.063 ;
     RECT  37.008 86.035 55.638 86.099 ;
     RECT  1.296 86.059 1.314 86.155 ;
     RECT  18 85.999 25.686 86.189 ;
     RECT  26.424 85.919 27.702 86.189 ;
     RECT  37.008 86.099 55.458 86.189 ;
     RECT  18.324 86.189 25.686 86.225 ;
     RECT  29.415 86.045 31.482 86.225 ;
     RECT  34.776 85.991 35.946 86.225 ;
     RECT  18.324 86.225 23.022 86.297 ;
     RECT  37.044 86.189 55.458 86.297 ;
     RECT  2.304 85.955 17.01 86.333 ;
     RECT  2.304 86.333 11.142 86.369 ;
     RECT  26.424 86.189 26.946 86.369 ;
     RECT  31.032 86.225 31.482 86.369 ;
     RECT  56.415 85.757 61.722 86.4 ;
     RECT  101.736 84.983 101.754 86.4 ;
     RECT  109.548 84.407 109.566 86.4 ;
     RECT  110.34 84.407 110.358 86.4 ;
     RECT  154.584 84.065 160.506 86.4 ;
     RECT  21.744 86.297 23.022 86.432 ;
     RECT  1.296 86.155 1.386 86.443 ;
     RECT  2.304 86.369 8.586 86.459 ;
     RECT  12.024 86.333 12.15 86.459 ;
     RECT  18.324 86.297 20.718 86.459 ;
     RECT  23.796 86.225 25.686 86.459 ;
     RECT  26.424 86.369 26.874 86.459 ;
     RECT  29.415 86.225 30.258 86.459 ;
     RECT  23.796 86.459 24.354 86.477 ;
     RECT  12.024 86.459 12.042 86.495 ;
     RECT  12.888 86.333 17.01 86.495 ;
     RECT  18.504 86.459 19.242 86.495 ;
     RECT  20.268 86.459 20.718 86.495 ;
     RECT  21.744 86.432 22.986 86.495 ;
     RECT  26.424 86.459 26.802 86.495 ;
     RECT  31.032 86.369 31.338 86.525 ;
     RECT  18.54 86.495 19.242 86.567 ;
     RECT  22.824 86.495 22.986 86.567 ;
     RECT  25.596 86.459 25.686 86.567 ;
     RECT  26.46 86.495 26.802 86.567 ;
     RECT  27.684 86.189 27.702 86.567 ;
     RECT  31.032 86.525 31.05 86.567 ;
     RECT  32.796 86.063 33.894 86.587 ;
     RECT  34.776 86.225 35.694 86.587 ;
     RECT  9.648 86.369 11.142 86.603 ;
     RECT  22.824 86.567 22.842 86.603 ;
     RECT  26.46 86.567 26.478 86.603 ;
     RECT  32.796 86.587 35.694 86.621 ;
     RECT  18.615 86.567 19.242 86.639 ;
     RECT  21.96 86.495 21.978 86.639 ;
     RECT  9.648 86.603 11.034 86.729 ;
     RECT  13.068 86.495 14.994 86.729 ;
     RECT  24.015 86.477 24.354 86.729 ;
     RECT  0.108 86.063 0.126 86.765 ;
     RECT  16.02 86.495 17.01 86.765 ;
     RECT  16.164 86.765 17.01 86.809 ;
     RECT  16.164 86.809 17.046 86.881 ;
     RECT  13.104 86.729 14.994 86.909 ;
     RECT  32.796 86.621 33.354 86.909 ;
     RECT  9.684 86.729 10.926 86.999 ;
     RECT  13.104 86.909 14.958 86.999 ;
     RECT  20.7 86.495 20.718 86.999 ;
     RECT  32.796 86.909 33.318 86.999 ;
     RECT  34.38 86.621 35.694 86.999 ;
     RECT  2.304 86.459 8.298 87.035 ;
     RECT  16.164 86.881 17.118 87.035 ;
     RECT  33.048 86.999 33.318 87.035 ;
     RECT  34.38 86.999 35.658 87.035 ;
     RECT  25.668 86.567 25.686 87.071 ;
     RECT  14.904 86.999 14.958 87.107 ;
     RECT  16.38 87.035 17.118 87.107 ;
     RECT  37.944 86.297 55.458 87.107 ;
     RECT  14.94 87.107 14.958 87.143 ;
     RECT  16.38 87.107 16.398 87.143 ;
     RECT  37.044 86.297 37.062 87.151 ;
     RECT  37.944 87.107 38.574 87.151 ;
     RECT  37.044 87.151 38.574 87.163 ;
     RECT  33.048 87.035 33.282 87.197 ;
     RECT  36.648 87.163 38.574 87.197 ;
     RECT  2.34 87.035 8.298 87.211 ;
     RECT  39.312 87.107 55.458 87.269 ;
     RECT  1.152 86.443 1.386 87.305 ;
     RECT  39.42 87.269 55.458 87.305 ;
     RECT  2.34 87.211 8.73 87.313 ;
     RECT  34.38 87.035 35.586 87.341 ;
     RECT  36.648 87.197 36.81 87.341 ;
     RECT  40.215 87.305 55.458 87.355 ;
     RECT  56.415 86.4 160.506 87.355 ;
     RECT  1.296 87.305 1.386 87.377 ;
     RECT  24.015 86.729 24.297 87.403 ;
     RECT  2.34 87.313 8.91 87.413 ;
     RECT  9.684 86.999 9.702 87.449 ;
     RECT  10.836 86.999 10.926 87.449 ;
     RECT  13.104 86.999 13.497 87.449 ;
     RECT  22.824 87.349 22.842 87.449 ;
     RECT  23.904 87.403 24.297 87.449 ;
     RECT  30.78 87.349 30.798 87.449 ;
     RECT  33.12 87.197 33.282 87.449 ;
     RECT  34.488 87.341 35.262 87.449 ;
     RECT  34.488 87.449 35.097 87.539 ;
     RECT  36.792 87.341 36.81 87.539 ;
     RECT  37.584 87.197 38.574 87.539 ;
     RECT  40.215 87.355 160.506 87.611 ;
     RECT  33.12 87.449 33.246 87.629 ;
     RECT  37.584 87.539 38.466 87.647 ;
     RECT  1.368 87.377 1.386 87.683 ;
     RECT  37.944 87.647 38.466 87.719 ;
     RECT  37.944 87.719 38.214 87.845 ;
     RECT  10.836 87.449 10.854 87.869 ;
     RECT  39.42 87.305 39.438 87.881 ;
     RECT  2.34 87.413 8.838 87.965 ;
     RECT  2.34 87.965 8.097 88.079 ;
     RECT  45.324 87.611 160.506 88.151 ;
     RECT  40.215 87.611 44.298 88.259 ;
     RECT  33.156 87.629 33.246 88.457 ;
     RECT  33.192 88.457 33.246 88.493 ;
     RECT  2.376 88.079 8.097 88.619 ;
     RECT  45.324 88.151 49.41 88.691 ;
     RECT  37.116 88.501 37.134 88.727 ;
     RECT  8.82 87.965 8.838 88.763 ;
     RECT  50.148 88.151 160.506 88.763 ;
     RECT  2.415 88.619 8.097 88.889 ;
     RECT  43.92 88.259 44.298 89.231 ;
     RECT  50.184 88.763 160.506 89.303 ;
     RECT  6.912 88.889 8.097 89.311 ;
     RECT  6.912 89.311 8.622 89.339 ;
     RECT  33.228 88.493 33.246 89.339 ;
     RECT  2.415 88.889 6.174 89.473 ;
     RECT  7.308 89.339 8.622 89.515 ;
     RECT  1.728 89.473 6.174 89.645 ;
     RECT  2.415 89.645 6.174 89.699 ;
     RECT  2.415 89.699 5.022 89.735 ;
     RECT  7.308 89.515 8.802 89.735 ;
     RECT  43.92 89.231 43.938 89.807 ;
     RECT  4.932 89.735 5.022 89.879 ;
     RECT  2.415 89.735 3.834 89.969 ;
     RECT  0.108 89.707 0.126 90.005 ;
     RECT  3.42 89.969 3.834 90.005 ;
     RECT  40.215 88.259 42.966 90.005 ;
     RECT  3.456 90.005 3.834 90.481 ;
     RECT  3.456 90.481 4.446 90.509 ;
     RECT  3.456 90.509 3.474 90.545 ;
     RECT  4.428 90.509 4.446 90.557 ;
     RECT  7.308 89.735 8.097 91.049 ;
     RECT  7.416 91.049 8.097 91.319 ;
     RECT  50.292 89.303 160.506 91.661 ;
     RECT  40.215 90.005 41.13 93.353 ;
     RECT  50.292 91.661 159.966 94.157 ;
     RECT  6.156 89.699 6.174 94.289 ;
     RECT  50.292 94.157 159.894 94.685 ;
     RECT  45.324 88.691 49.338 94.973 ;
     RECT  50.292 94.685 159.75 95.453 ;
     RECT  41.868 90.005 42.966 95.477 ;
     RECT  42.516 95.477 42.966 95.513 ;
     RECT  42.516 95.513 42.642 95.549 ;
     RECT  49.32 94.973 49.338 95.639 ;
     RECT  50.292 95.453 159.678 95.789 ;
     RECT  45.324 94.973 48.042 96.179 ;
     RECT  42.624 95.549 42.642 96.449 ;
     RECT  47.088 96.179 48.042 96.989 ;
     RECT  50.292 95.789 159.297 97.853 ;
     RECT  156.744 97.853 159.297 97.949 ;
     RECT  50.292 97.853 155.79 98.141 ;
     RECT  157.32 97.949 159.297 98.237 ;
     RECT  48.024 96.989 48.042 98.879 ;
     RECT  50.292 98.141 155.646 99.059 ;
     RECT  45.324 96.179 45.897 99.149 ;
     RECT  50.724 99.059 155.646 99.185 ;
     RECT  51.015 99.185 155.646 101.693 ;
     RECT  51.015 101.693 155.43 104.669 ;
     RECT  51.015 104.669 155.304 107.803 ;
     RECT  51.015 107.803 155.394 111.341 ;
     RECT  56.016 111.341 155.394 112.445 ;
     RECT  56.016 112.445 57.15 112.493 ;
     RECT  56.415 112.493 57.15 112.541 ;
     RECT  57.924 112.445 155.394 113.261 ;
     RECT  51.015 111.341 55.242 113.305 ;
     RECT  50.436 113.305 55.242 113.309 ;
     RECT  50.436 113.309 53.766 113.357 ;
     RECT  51.015 113.357 53.766 114.845 ;
     RECT  56.415 112.541 56.697 115.483 ;
     RECT  51.015 114.845 53.586 115.517 ;
     RECT  56.304 115.483 56.697 115.529 ;
     RECT  54.756 113.309 55.242 116.045 ;
     RECT  56.415 115.529 56.697 116.671 ;
     RECT  56.304 116.671 56.697 117.149 ;
     RECT  157.896 98.237 159.297 117.245 ;
     RECT  57.996 113.261 155.394 118.603 ;
     RECT  57.96 118.603 155.394 118.7 ;
     RECT  57.996 118.7 155.394 118.769 ;
     RECT  58.068 118.769 155.394 118.781 ;
     RECT  51.015 115.517 53.478 119.789 ;
     RECT  45.615 99.149 45.897 119.983 ;
     RECT  37.944 87.845 37.962 120.011 ;
     RECT  157.896 117.245 157.914 120.125 ;
     RECT  51.015 119.789 51.894 120.221 ;
     RECT  52.812 119.789 53.478 120.317 ;
     RECT  53.388 120.317 53.478 120.605 ;
     RECT  58.104 118.781 155.394 120.859 ;
     RECT  58.068 120.859 155.394 120.989 ;
     RECT  56.415 117.149 56.697 120.991 ;
     RECT  58.104 120.989 155.394 121.085 ;
     RECT  58.14 121.085 155.394 121.373 ;
     RECT  58.176 121.373 155.394 121.469 ;
     RECT  56.304 120.991 56.697 121.568 ;
     RECT  51.015 120.221 51.786 122.237 ;
     RECT  58.32 121.469 155.394 122.521 ;
     RECT  58.32 122.521 155.61 122.621 ;
     RECT  58.32 122.621 58.338 122.717 ;
     RECT  51.015 122.237 51.39 122.813 ;
     RECT  157.248 122.755 157.266 122.917 ;
     RECT  156.744 122.917 157.266 123.061 ;
     RECT  156.744 123.061 157.302 123.581 ;
     RECT  59.652 122.621 155.61 124.253 ;
     RECT  59.652 124.253 155.394 124.349 ;
     RECT  156.744 123.581 156.798 124.375 ;
     RECT  157.968 124.069 157.986 124.375 ;
     RECT  59.832 124.349 155.394 124.445 ;
     RECT  156.744 124.375 157.986 124.445 ;
     RECT  157.752 124.445 157.986 124.565 ;
     RECT  158.004 124.681 158.022 124.799 ;
     RECT  55.224 116.045 55.242 124.925 ;
     RECT  156.744 124.445 156.762 124.925 ;
     RECT  59.868 124.445 155.394 124.979 ;
     RECT  60.228 124.979 155.394 124.987 ;
     RECT  157.572 125.347 157.59 125.483 ;
     RECT  56.415 121.568 56.697 125.851 ;
     RECT  157.608 125.755 157.626 125.851 ;
     RECT  60.228 124.987 155.61 125.947 ;
     RECT  157.608 125.851 157.806 126.139 ;
     RECT  57.888 125.995 57.906 126.173 ;
     RECT  157.608 126.139 157.842 126.235 ;
     RECT  60.228 125.947 156.222 126.283 ;
     RECT  53.388 120.605 53.406 126.317 ;
     RECT  56.304 125.851 56.697 126.329 ;
     RECT  59.76 126.283 156.222 126.329 ;
     RECT  59.76 126.329 155.394 126.419 ;
     RECT  59.76 126.419 155.304 126.509 ;
     RECT  157.536 126.235 157.842 126.725 ;
     RECT  156.204 126.329 156.222 126.959 ;
     RECT  60.48 126.509 155.304 127.44 ;
     RECT  61.815 129.583 61.905 129.853 ;
     RECT  67.215 129.583 67.305 129.853 ;
     RECT  72.615 129.583 72.705 129.853 ;
     RECT  78.015 129.583 78.105 129.853 ;
     RECT  83.415 129.583 83.505 129.853 ;
     RECT  88.815 129.583 88.905 129.853 ;
     RECT  94.215 129.583 94.305 129.853 ;
     RECT  99.615 129.583 99.705 129.853 ;
     RECT  105.015 129.583 105.105 129.853 ;
     RECT  110.415 129.583 110.505 129.853 ;
     RECT  115.815 129.583 115.905 129.853 ;
     RECT  121.215 129.583 121.305 129.853 ;
     RECT  126.615 129.583 126.705 129.853 ;
     RECT  132.015 129.583 132.105 129.853 ;
     RECT  137.415 129.583 137.505 129.853 ;
     RECT  142.815 129.583 142.905 129.853 ;
     RECT  148.215 129.583 148.305 129.853 ;
     RECT  153.615 129.583 153.705 129.853 ;
     RECT  49.32 131.659 49.338 132.089 ;
     RECT  47.916 132.091 47.934 132.131 ;
     RECT  47.088 96.989 47.106 148.019 ;
     RECT  44.892 119.983 45.897 148.135 ;
     RECT  44.892 148.135 46.17 148.219 ;
     RECT  44.604 148.219 46.17 148.289 ;
     RECT  44.676 148.289 45.897 148.739 ;
     RECT  2.415 89.969 2.697 148.787 ;
     RECT  7.815 91.319 8.097 148.787 ;
     RECT  13.215 87.449 13.497 148.787 ;
     RECT  18.615 86.639 18.897 148.787 ;
     RECT  24.015 87.449 24.297 148.787 ;
     RECT  29.415 86.459 29.697 148.787 ;
     RECT  34.815 87.539 35.097 148.787 ;
     RECT  40.215 93.353 40.497 148.787 ;
     RECT  44.856 148.739 45.897 148.787 ;
     RECT  51.015 122.813 51.297 148.787 ;
     RECT  56.415 126.329 56.697 148.787 ;
     RECT  61.815 129.853 62.097 148.787 ;
     RECT  67.215 129.853 67.497 148.787 ;
     RECT  72.615 129.853 72.897 148.787 ;
     RECT  78.015 129.853 78.297 148.787 ;
     RECT  83.415 129.853 83.697 148.787 ;
     RECT  88.815 129.853 89.097 148.787 ;
     RECT  94.215 129.853 94.497 148.787 ;
     RECT  99.615 129.853 99.897 148.787 ;
     RECT  105.015 129.853 105.297 148.787 ;
     RECT  110.415 129.853 110.697 148.787 ;
     RECT  115.815 129.853 116.097 148.787 ;
     RECT  121.215 129.853 121.497 148.787 ;
     RECT  126.615 129.853 126.897 148.787 ;
     RECT  132.015 129.853 132.297 148.787 ;
     RECT  137.415 129.853 137.697 148.787 ;
     RECT  142.815 129.853 143.097 148.787 ;
     RECT  148.215 129.853 148.497 148.787 ;
     RECT  153.615 129.853 153.897 148.787 ;
     RECT  159.015 117.245 159.297 148.787 ;
     RECT  164.415 72.959 164.697 148.787 ;
     RECT  169.815 2.413 170.097 148.787 ;
     RECT  175.215 71.789 175.497 148.787 ;
     RECT  180.615 2.413 180.897 148.787 ;
     RECT  186.015 75.191 186.297 148.787 ;
     RECT  191.415 75.767 191.697 148.787 ;
     RECT  196.815 80.159 197.097 148.787 ;
     RECT  202.215 78.539 202.497 148.787 ;
     RECT  207.615 80.663 207.897 148.787 ;
     RECT  213.015 79.007 213.297 148.787 ;
     RECT  44.856 148.787 45.705 148.829 ;
     RECT  44.892 148.829 45.705 148.973 ;
     RECT  45 148.973 45.705 149.021 ;
     RECT  2.415 148.787 2.505 149.057 ;
     RECT  7.815 148.787 7.905 149.057 ;
     RECT  13.215 148.787 13.305 149.057 ;
     RECT  18.615 148.787 18.705 149.057 ;
     RECT  24.015 148.787 24.105 149.057 ;
     RECT  29.415 148.787 29.505 149.057 ;
     RECT  34.815 148.787 34.905 149.057 ;
     RECT  40.215 148.787 40.305 149.057 ;
     RECT  45.615 149.021 45.705 149.057 ;
     RECT  51.015 148.787 51.105 149.057 ;
     RECT  56.415 148.787 56.505 149.057 ;
     RECT  61.815 148.787 61.905 149.057 ;
     RECT  67.215 148.787 67.305 149.057 ;
     RECT  72.615 148.787 72.705 149.057 ;
     RECT  78.015 148.787 78.105 149.057 ;
     RECT  83.415 148.787 83.505 149.057 ;
     RECT  88.815 148.787 88.905 149.057 ;
     RECT  94.215 148.787 94.305 149.057 ;
     RECT  99.615 148.787 99.705 149.057 ;
     RECT  105.015 148.787 105.105 149.057 ;
     RECT  110.415 148.787 110.505 149.057 ;
     RECT  115.815 148.787 115.905 149.057 ;
     RECT  121.215 148.787 121.305 149.057 ;
     RECT  126.615 148.787 126.705 149.057 ;
     RECT  132.015 148.787 132.105 149.057 ;
     RECT  137.415 148.787 137.505 149.057 ;
     RECT  142.815 148.787 142.905 149.057 ;
     RECT  148.215 148.787 148.305 149.057 ;
     RECT  153.615 148.787 153.705 149.057 ;
     RECT  159.015 148.787 159.105 149.057 ;
     RECT  164.415 148.787 164.505 149.057 ;
     RECT  169.815 148.787 169.905 149.057 ;
     RECT  175.215 148.787 175.305 149.057 ;
     RECT  180.615 148.787 180.705 149.057 ;
     RECT  186.015 148.787 186.105 149.057 ;
     RECT  191.415 148.787 191.505 149.057 ;
     RECT  196.815 148.787 196.905 149.057 ;
     RECT  202.215 148.787 202.305 149.057 ;
     RECT  207.615 148.787 207.705 149.057 ;
     RECT  213.015 148.787 213.105 149.057 ;
     RECT  45.036 150.475 45.054 151.099 ;
     RECT  44.964 151.099 45.054 151.181 ;
    LAYER M4 ;
     RECT  0.06 77.52 0.133 86.664 ;
     RECT  0.06 89.616 0.137 89.736 ;
     RECT  0.133 76.848 0.181 86.664 ;
     RECT  0.181 76.848 0.277 87.288 ;
     RECT  0.133 88.416 0.277 88.44 ;
     RECT  0.325 75.792 2.293 75.816 ;
     RECT  0.277 76.848 2.293 88.44 ;
     RECT  2.293 75.792 2.408 88.44 ;
     RECT  0.137 89.616 2.408 89.64 ;
     RECT  2.408 2.148 2.512 149.052 ;
     RECT  2.512 2.418 2.704 148.782 ;
     RECT  2.704 75.552 3.685 89.544 ;
     RECT  3.685 75.216 3.829 89.544 ;
     RECT  3.829 75.12 3.923 89.544 ;
     RECT  3.923 75.12 4.652 88.536 ;
     RECT  4.652 75.024 5.137 88.536 ;
     RECT  3.923 89.52 5.137 89.544 ;
     RECT  5.137 75.024 5.177 89.544 ;
     RECT  5.177 75.024 5.507 89.064 ;
     RECT  5.507 75.168 5.825 89.064 ;
     RECT  5.825 75.168 5.933 88.488 ;
     RECT  5.933 75.264 6.293 88.488 ;
     RECT  5.173 50.592 6.469 50.616 ;
     RECT  6.293 75.648 6.617 88.488 ;
     RECT  6.617 75.648 7.292 87.72 ;
     RECT  7.621 25.296 7.808 25.32 ;
     RECT  6.469 50.016 7.808 50.616 ;
     RECT  7.292 75.552 7.808 87.72 ;
     RECT  7.657 89.52 7.808 89.544 ;
     RECT  4.417 90.528 7.808 90.552 ;
     RECT  7.808 2.148 7.912 149.052 ;
     RECT  7.912 2.418 8.104 148.782 ;
     RECT  8.104 77.904 8.771 87.96 ;
     RECT  8.104 89.52 8.813 89.544 ;
     RECT  8.104 76.032 9.173 76.776 ;
     RECT  8.771 77.952 9.461 87.96 ;
     RECT  8.104 25.296 9.493 25.32 ;
     RECT  9.461 77.952 9.713 83.256 ;
     RECT  9.713 78.048 10.217 83.256 ;
     RECT  9.493 25.008 10.465 25.32 ;
     RECT  10.217 83.232 10.465 83.256 ;
     RECT  9.461 84.288 10.465 87.96 ;
     RECT  10.217 78.048 11.009 81.72 ;
     RECT  11.009 78.048 11.117 79.896 ;
     RECT  9.173 76.08 11.461 76.776 ;
     RECT  11.461 76.08 11.548 77.304 ;
     RECT  11.117 78.336 11.651 79.896 ;
     RECT  11.651 78.432 11.987 79.896 ;
     RECT  11.548 76.08 12.161 76.776 ;
     RECT  11.987 78.432 12.733 79.224 ;
     RECT  12.161 76.08 12.812 76.104 ;
     RECT  10.465 24.72 13.208 25.32 ;
     RECT  8.104 49.248 13.208 50.616 ;
     RECT  12.853 68.928 13.208 68.952 ;
     RECT  12.812 75.6 13.208 76.104 ;
     RECT  12.733 78.384 13.208 79.224 ;
     RECT  11.009 80.88 13.208 81.72 ;
     RECT  10.465 83.232 13.208 87.96 ;
     RECT  8.104 90.528 13.208 90.552 ;
     RECT  13.208 2.148 13.312 149.052 ;
     RECT  13.312 2.418 13.504 148.782 ;
     RECT  13.504 83.856 13.781 87.96 ;
     RECT  13.504 80.88 13.925 81.72 ;
     RECT  13.504 78.24 14.213 79.224 ;
     RECT  13.781 84.048 14.773 87.96 ;
     RECT  13.504 77.088 14.785 77.112 ;
     RECT  14.773 83.76 15.617 87.96 ;
     RECT  14.785 76.512 15.793 77.112 ;
     RECT  14.213 78.24 15.793 79.128 ;
     RECT  15.617 84.288 16.873 87.96 ;
     RECT  15.793 76.512 17.317 79.128 ;
     RECT  17.317 75.792 17.363 79.128 ;
     RECT  17.363 77.088 17.381 79.128 ;
     RECT  17.363 75.792 17.404 75.816 ;
     RECT  16.873 84.048 17.629 87.96 ;
     RECT  17.629 83.76 17.917 87.96 ;
     RECT  17.381 77.088 18.421 78.648 ;
     RECT  13.504 24.72 18.608 25.32 ;
     RECT  13.504 49.248 18.608 50.616 ;
     RECT  13.504 68.928 18.608 68.952 ;
     RECT  18.529 75.216 18.608 75.24 ;
     RECT  18.421 77.088 18.608 79.272 ;
     RECT  13.925 80.928 18.608 81.72 ;
     RECT  17.917 83.04 18.608 87.96 ;
     RECT  13.504 90.528 18.608 90.552 ;
     RECT  18.608 2.148 18.712 149.052 ;
     RECT  18.712 2.418 18.904 148.782 ;
     RECT  18.904 78.336 19.001 79.272 ;
     RECT  18.904 75.216 19.469 75.24 ;
     RECT  20.348 75.36 20.365 75.384 ;
     RECT  18.904 77.088 20.365 77.112 ;
     RECT  20.365 75.36 20.435 77.112 ;
     RECT  20.389 74.352 20.941 74.376 ;
     RECT  20.435 75.888 21.013 77.112 ;
     RECT  19.001 78.336 21.013 78.984 ;
     RECT  21.013 75.888 21.017 78.984 ;
     RECT  18.904 80.928 21.121 81.72 ;
     RECT  18.904 83.04 21.121 83.064 ;
     RECT  21.121 80.928 21.205 83.064 ;
     RECT  21.017 75.888 21.397 78.648 ;
     RECT  18.904 84.288 21.445 87.96 ;
     RECT  21.205 80.928 21.481 81.72 ;
     RECT  20.941 74.352 22.021 74.424 ;
     RECT  21.397 75.456 22.021 78.648 ;
     RECT  21.481 79.968 23.077 81.72 ;
     RECT  22.021 74.352 23.564 78.648 ;
     RECT  23.077 79.728 23.564 81.72 ;
     RECT  21.445 83.472 23.893 87.96 ;
     RECT  18.904 24.72 24.008 25.32 ;
     RECT  18.904 49.248 24.008 50.616 ;
     RECT  18.904 68.928 24.008 68.952 ;
     RECT  23.564 74.352 24.008 81.72 ;
     RECT  23.893 82.752 24.008 87.96 ;
     RECT  18.904 90.528 24.008 90.552 ;
     RECT  24.008 2.148 24.112 149.052 ;
     RECT  24.112 2.418 24.304 148.782 ;
     RECT  24.304 74.352 24.419 81.72 ;
     RECT  24.419 74.352 25.043 77.832 ;
     RECT  24.419 79.2 25.139 81.72 ;
     RECT  25.043 74.352 26.197 77.112 ;
     RECT  26.197 74.352 26.233 77.688 ;
     RECT  26.233 74.016 26.521 77.688 ;
     RECT  25.139 79.488 26.725 81.72 ;
     RECT  24.304 82.752 26.741 82.776 ;
     RECT  26.521 74.016 27.059 77.976 ;
     RECT  24.304 68.928 27.061 68.952 ;
     RECT  27.02 65.328 27.157 65.352 ;
     RECT  24.304 49.248 27.203 50.616 ;
     RECT  27.061 68.928 27.209 69.48 ;
     RECT  27.157 65.088 27.425 65.736 ;
     RECT  24.304 84.288 27.601 87.96 ;
     RECT  26.725 78.96 27.637 81.72 ;
     RECT  27.059 74.016 27.641 77.544 ;
     RECT  27.637 78.96 27.709 82.68 ;
     RECT  27.601 84 27.709 87.96 ;
     RECT  27.277 71.712 27.745 71.736 ;
     RECT  27.641 74.064 27.929 77.544 ;
     RECT  27.709 83.76 27.965 87.96 ;
     RECT  27.745 71.424 28.001 71.736 ;
     RECT  27.709 78.624 28.397 82.68 ;
     RECT  28.405 67.296 28.429 67.32 ;
     RECT  28.429 67.296 28.573 67.848 ;
     RECT  27.209 69.456 28.573 69.48 ;
     RECT  28.001 71.712 28.753 71.736 ;
     RECT  28.753 71.712 28.789 72.744 ;
     RECT  27.929 74.256 28.789 77.544 ;
     RECT  28.789 71.712 29.005 73.128 ;
     RECT  28.789 74.256 29.005 77.976 ;
     RECT  28.573 67.296 29.041 69.48 ;
     RECT  29.005 71.712 29.401 77.976 ;
     RECT  24.304 24.72 29.408 25.32 ;
     RECT  27.203 50.016 29.408 50.616 ;
     RECT  27.425 65.712 29.408 65.736 ;
     RECT  29.041 67.296 29.408 70.104 ;
     RECT  29.401 71.664 29.408 77.976 ;
     RECT  28.397 78.96 29.408 82.68 ;
     RECT  27.965 83.856 29.408 87.96 ;
     RECT  24.304 90.528 29.408 90.552 ;
     RECT  29.408 2.148 29.512 149.052 ;
     RECT  29.512 2.418 29.704 148.782 ;
     RECT  29.704 69.312 29.981 72.312 ;
     RECT  29.981 70.704 30.197 72.312 ;
     RECT  29.981 69.312 30.611 69.72 ;
     RECT  30.197 71.04 30.733 72.312 ;
     RECT  29.704 73.488 30.733 81.72 ;
     RECT  30.733 71.04 30.737 81.72 ;
     RECT  29.704 67.68 30.769 67.848 ;
     RECT  29.704 83.472 30.809 87.96 ;
     RECT  30.737 78.336 30.913 81.72 ;
     RECT  30.737 71.04 31.133 77.304 ;
     RECT  30.769 67.68 31.309 68.28 ;
     RECT  30.913 78.336 31.385 82.2 ;
     RECT  31.309 67.392 31.453 68.28 ;
     RECT  31.453 67.296 31.621 68.28 ;
     RECT  30.611 69.312 31.621 69.528 ;
     RECT  31.133 71.04 31.849 72.216 ;
     RECT  31.849 70.608 32.033 72.216 ;
     RECT  32.033 70.704 32.249 72.216 ;
     RECT  31.621 67.296 33.073 69.528 ;
     RECT  32.249 71.04 33.073 72.216 ;
     RECT  31.133 73.488 33.073 77.304 ;
     RECT  29.704 90.528 33.107 90.552 ;
     RECT  33.073 71.04 33.469 77.304 ;
     RECT  31.385 78.432 33.469 82.2 ;
     RECT  33.073 67.056 33.473 69.528 ;
     RECT  33.469 71.04 33.613 82.2 ;
     RECT  30.809 83.616 33.613 87.96 ;
     RECT  33.613 70.656 33.725 87.96 ;
     RECT  33.473 67.056 33.761 69.48 ;
     RECT  33.725 71.232 33.797 87.96 ;
     RECT  33.797 72.192 34.801 87.96 ;
     RECT  29.704 24.72 34.808 25.32 ;
     RECT  29.704 50.016 34.808 50.616 ;
     RECT  33.761 67.056 34.808 68.232 ;
     RECT  33.761 69.312 34.808 69.48 ;
     RECT  34.801 71.424 34.808 87.96 ;
     RECT  34.808 2.148 34.912 149.052 ;
     RECT  34.912 2.418 35.104 148.782 ;
     RECT  35.104 71.424 35.219 82.2 ;
     RECT  35.104 83.424 36.277 87.96 ;
     RECT  35.104 69.456 36.62 70.248 ;
     RECT  35.219 71.424 36.62 82.056 ;
     RECT  36.62 69.456 36.707 82.056 ;
     RECT  35.104 66.72 36.821 67.704 ;
     RECT  36.707 69.456 36.925 70.488 ;
     RECT  36.821 67.056 37.069 67.704 ;
     RECT  36.925 69.024 37.069 70.488 ;
     RECT  36.707 71.76 37.181 82.056 ;
     RECT  36.277 83.232 37.397 87.96 ;
     RECT  37.069 67.056 38.329 70.488 ;
     RECT  38.329 67.056 38.339 70.632 ;
     RECT  37.181 71.808 38.437 82.056 ;
     RECT  38.437 71.808 38.581 82.2 ;
     RECT  37.397 83.472 38.581 87.96 ;
     RECT  38.339 69.744 38.725 70.632 ;
     RECT  38.581 71.808 38.725 87.96 ;
     RECT  38.725 69.744 38.837 87.96 ;
     RECT  38.339 67.056 38.873 68.712 ;
     RECT  38.873 67.344 39.625 68.712 ;
     RECT  38.837 69.744 39.625 70.392 ;
     RECT  39.625 67.344 40.057 70.392 ;
     RECT  40.057 66.864 40.129 70.392 ;
     RECT  35.104 24.72 40.208 25.32 ;
     RECT  35.104 50.016 40.208 50.616 ;
     RECT  40.129 66.528 40.208 70.392 ;
     RECT  38.837 71.376 40.208 87.96 ;
     RECT  40.208 2.148 40.312 149.052 ;
     RECT  40.312 2.418 40.504 148.782 ;
     RECT  40.504 65.952 40.817 68.952 ;
     RECT  40.817 66.864 41.033 68.952 ;
     RECT  40.504 71.856 41.213 87.96 ;
     RECT  41.033 67.008 41.569 68.952 ;
     RECT  40.504 88.944 41.603 88.968 ;
     RECT  41.569 67.008 41.605 69.528 ;
     RECT  41.605 67.008 41.717 69.912 ;
     RECT  41.213 72.288 42.001 87.96 ;
     RECT  41.717 67.008 42.289 68.76 ;
     RECT  41.717 69.888 42.541 69.912 ;
     RECT  42.325 65.376 42.617 65.4 ;
     RECT  42.289 66.48 42.829 68.76 ;
     RECT  42.001 72.288 42.833 88.104 ;
     RECT  42.833 72.768 43.049 88.104 ;
     RECT  42.829 66.48 43.333 68.904 ;
     RECT  43.049 72.768 43.841 87.96 ;
     RECT  43.333 66.288 43.909 68.904 ;
     RECT  42.541 69.888 44.021 70.152 ;
     RECT  43.909 66.24 44.129 68.904 ;
     RECT  44.129 66.288 44.233 68.904 ;
     RECT  44.593 148.224 44.965 148.248 ;
     RECT  44.953 151.104 44.965 151.128 ;
     RECT  44.965 150.48 45.065 151.128 ;
     RECT  44.773 64.944 45.385 64.968 ;
     RECT  44.233 66.288 45.385 69.48 ;
     RECT  40.504 24.72 45.608 25.32 ;
     RECT  40.504 50.016 45.608 50.616 ;
     RECT  45.385 64.944 45.608 69.48 ;
     RECT  43.841 73.008 45.608 87.96 ;
     RECT  42.325 89.952 45.608 89.976 ;
     RECT  44.629 116.448 45.608 116.472 ;
     RECT  44.965 148.224 45.608 149.016 ;
     RECT  45.608 2.148 45.712 149.052 ;
     RECT  45.712 2.418 45.904 148.782 ;
     RECT  45.904 64.944 45.965 68.76 ;
     RECT  45.965 64.944 46.217 68.52 ;
     RECT  46.217 65.472 46.361 68.52 ;
     RECT  46.361 65.472 46.469 68.472 ;
     RECT  46.469 65.472 46.793 68.328 ;
     RECT  45.904 89.952 46.793 90.072 ;
     RECT  46.793 66.192 46.865 68.328 ;
     RECT  45.904 73.008 47.077 87.96 ;
     RECT  47.077 72.912 47.689 87.96 ;
     RECT  45.065 151.104 47.843 151.128 ;
     RECT  47.797 132.096 47.945 132.12 ;
     RECT  46.865 66.192 48.265 67.848 ;
     RECT  47.689 72.528 48.341 87.96 ;
     RECT  48.265 65.472 48.413 67.848 ;
     RECT  48.877 71.376 49.057 71.4 ;
     RECT  48.413 65.568 49.129 67.848 ;
     RECT  49.129 65.568 49.277 68.712 ;
     RECT  49.277 66.192 49.309 68.712 ;
     RECT  49.057 71.376 49.345 71.496 ;
     RECT  49.309 131.664 49.393 131.688 ;
     RECT  49.345 71.376 49.745 71.784 ;
     RECT  48.553 91.056 50.869 91.08 ;
     RECT  45.904 24.72 51.008 25.32 ;
     RECT  50.101 48.672 51.008 48.696 ;
     RECT  45.904 50.016 51.008 50.616 ;
     RECT  49.309 66.192 51.008 69.48 ;
     RECT  49.745 71.472 51.008 71.784 ;
     RECT  48.341 72.816 51.008 87.96 ;
     RECT  46.793 90.048 51.008 90.072 ;
     RECT  50.869 91.056 51.008 91.464 ;
     RECT  50.461 94.08 51.008 94.104 ;
     RECT  49.333 113.328 51.008 113.352 ;
     RECT  45.904 116.448 51.008 116.472 ;
     RECT  51.008 2.148 51.112 149.052 ;
     RECT  51.112 2.418 51.304 148.782 ;
     RECT  51.304 90.048 51.779 93.528 ;
     RECT  51.779 90.48 52.049 93.528 ;
     RECT  51.304 112.848 52.093 114.072 ;
     RECT  51.304 70.368 52.121 70.728 ;
     RECT  51.304 45.552 52.163 45.576 ;
     RECT  51.304 41.616 52.316 41.64 ;
     RECT  52.121 70.368 52.337 70.68 ;
     RECT  51.304 72.816 52.357 88.584 ;
     RECT  52.316 41.52 52.403 41.64 ;
     RECT  52.049 90.48 52.403 92.76 ;
     RECT  52.412 41.808 52.499 41.832 ;
     RECT  51.304 47.232 52.585 47.256 ;
     RECT  51.304 48.672 52.585 48.696 ;
     RECT  52.549 100.896 52.621 100.92 ;
     RECT  51.304 117.888 52.621 118.632 ;
     RECT  51.304 119.76 52.621 122.808 ;
     RECT  52.621 100.896 52.657 101.112 ;
     RECT  51.304 65.472 52.693 69.24 ;
     RECT  52.337 70.368 52.693 70.584 ;
     RECT  51.304 116.448 52.693 116.856 ;
     RECT  52.403 90.576 52.697 92.76 ;
     RECT  52.513 103.008 52.7 103.032 ;
     RECT  52.7 103.008 52.741 103.128 ;
     RECT  52.621 104.16 52.741 104.184 ;
     RECT  51.304 43.68 52.805 43.704 ;
     RECT  52.501 63.648 52.837 63.672 ;
     RECT  52.873 94.656 52.945 94.68 ;
     RECT  52.657 100.896 52.945 101.256 ;
     RECT  52.741 103.008 52.945 104.184 ;
     RECT  52.945 94.656 52.981 94.872 ;
     RECT  52.297 50.016 53.009 50.04 ;
     RECT  52.697 91.008 53.053 92.76 ;
     RECT  52.981 94.08 53.053 94.872 ;
     RECT  52.945 100.896 53.053 101.688 ;
     RECT  52.549 57.072 53.077 57.096 ;
     RECT  52.693 65.472 53.093 70.584 ;
     RECT  52.945 103.008 53.093 104.664 ;
     RECT  52.693 116.304 53.125 116.856 ;
     RECT  53.053 100.32 53.161 101.688 ;
     RECT  53.017 96.192 53.269 96.216 ;
     RECT  53.093 66 53.305 70.584 ;
     RECT  53.269 96.096 53.341 96.216 ;
     RECT  52.837 97.248 53.341 97.272 ;
     RECT  53.016 53.952 53.345 53.976 ;
     RECT  53.125 115.68 53.365 116.856 ;
     RECT  52.621 117.888 53.365 122.808 ;
     RECT  53.161 100.32 53.377 101.736 ;
     RECT  53.269 125.856 53.377 125.88 ;
     RECT  53.317 60.144 53.413 60.168 ;
     RECT  53.377 100.176 53.413 101.736 ;
     RECT  53.305 66 53.453 70.68 ;
     RECT  52.093 113.76 53.461 114.072 ;
     RECT  53.341 96.096 53.489 97.272 ;
     RECT  53.489 97.248 53.521 97.272 ;
     RECT  53.053 91.008 53.557 94.872 ;
     RECT  53.489 96.096 53.557 96.12 ;
     RECT  53.365 115.68 53.557 122.808 ;
     RECT  53.557 91.008 53.561 96.12 ;
     RECT  53.377 42.816 53.665 42.84 ;
     RECT  53.629 44.88 53.701 44.904 ;
     RECT  52.585 47.232 53.701 48.696 ;
     RECT  53.413 59.568 53.701 60.168 ;
     RECT  52.357 72.816 53.701 89.16 ;
     RECT  53.701 46.8 53.737 48.696 ;
     RECT  53.009 50.016 53.737 50.76 ;
     RECT  53.453 66.096 53.737 70.68 ;
     RECT  53.461 113.568 53.737 114.072 ;
     RECT  53.557 115.488 53.737 122.808 ;
     RECT  53.521 97.248 53.773 97.56 ;
     RECT  52.801 98.64 53.773 98.664 ;
     RECT  53.737 46.8 53.777 50.76 ;
     RECT  53.773 97.248 53.804 98.664 ;
     RECT  53.665 41.856 53.809 42.84 ;
     RECT  53.701 44.88 53.845 45.288 ;
     RECT  53.777 46.8 53.881 49.608 ;
     RECT  53.413 100.176 53.881 101.784 ;
     RECT  53.845 44.88 53.884 45.576 ;
     RECT  53.093 103.008 53.885 104.568 ;
     RECT  53.809 41.856 53.917 42.888 ;
     RECT  53.077 56.448 54.037 57.096 ;
     RECT  53.884 44.688 54.065 45.576 ;
     RECT  54.025 55.248 54.085 55.272 ;
     RECT  53.917 41.472 54.097 42.888 ;
     RECT  53.777 50.592 54.097 50.76 ;
     RECT  53.053 51.744 54.097 51.768 ;
     RECT  53.885 103.632 54.133 104.568 ;
     RECT  53.804 97.248 54.169 99.192 ;
     RECT  53.881 100.176 54.169 101.976 ;
     RECT  54.169 97.248 54.277 101.976 ;
     RECT  53.737 113.568 54.313 122.808 ;
     RECT  53.701 72.816 54.325 89.496 ;
     RECT  53.377 125.856 54.325 126.312 ;
     RECT  54.097 50.592 54.349 51.768 ;
     RECT  54.037 56.256 54.349 57.096 ;
     RECT  54.313 113.28 54.373 122.808 ;
     RECT  54.349 40.176 54.385 40.2 ;
     RECT  54.097 41.472 54.385 43.416 ;
     RECT  53.737 66.096 54.421 71.16 ;
     RECT  53.561 91.008 54.467 95.784 ;
     RECT  54.373 113.28 54.469 123.288 ;
     RECT  54.065 45.264 54.497 45.576 ;
     RECT  54.421 65.904 54.517 71.16 ;
     RECT  54.385 41.424 54.524 43.416 ;
     RECT  54.085 54.864 54.565 55.272 ;
     RECT  54.133 103.632 54.565 104.76 ;
     RECT  53.881 46.752 54.605 49.608 ;
     RECT  54.325 125.088 54.613 126.312 ;
     RECT  53.701 59.568 54.637 60.648 ;
     RECT  54.277 97.248 54.641 102.264 ;
     RECT  54.385 40.032 54.673 40.2 ;
     RECT  54.524 41.232 54.673 43.416 ;
     RECT  54.565 54.48 54.673 55.272 ;
     RECT  54.325 72.624 54.673 89.496 ;
     RECT  54.493 33.072 54.677 33.096 ;
     RECT  54.493 38.736 54.709 38.76 ;
     RECT  54.349 50.592 54.757 51.912 ;
     RECT  54.517 65.904 54.805 71.256 ;
     RECT  54.613 124.944 54.805 126.312 ;
     RECT  54.467 91.104 54.817 95.784 ;
     RECT  54.641 97.248 54.817 100.92 ;
     RECT  54.757 50.592 54.889 52.776 ;
     RECT  54.673 72.624 54.925 89.784 ;
     RECT  54.889 50.592 54.997 53.016 ;
     RECT  54.565 103.632 54.997 104.808 ;
     RECT  54.745 34.128 55.033 34.152 ;
     RECT  54.497 45.264 55.033 45.288 ;
     RECT  54.641 101.952 55.033 102.264 ;
     RECT  54.637 110.016 55.033 110.04 ;
     RECT  54.925 72.624 55.043 89.88 ;
     RECT  55.033 33.12 55.105 34.152 ;
     RECT  55.043 72.624 55.133 85.608 ;
     RECT  55.033 29.664 55.141 29.688 ;
     RECT  54.997 50.304 55.141 53.016 ;
     RECT  54.673 54.048 55.141 55.272 ;
     RECT  54.709 38.736 55.177 39 ;
     RECT  54.805 65.904 55.189 71.4 ;
     RECT  55.133 72.384 55.189 85.608 ;
     RECT  54.805 124.656 55.189 126.312 ;
     RECT  55.033 101.952 55.213 102.648 ;
     RECT  54.997 103.632 55.213 104.856 ;
     RECT  55.033 110.016 55.213 110.904 ;
     RECT  55.033 45.216 55.249 45.288 ;
     RECT  55.189 65.904 55.253 85.608 ;
     RECT  55.253 65.904 55.283 85.272 ;
     RECT  54.673 40.032 55.285 43.416 ;
     RECT  55.189 124.608 55.333 126.312 ;
     RECT  55.105 33.12 55.357 34.392 ;
     RECT  55.213 110.016 55.357 111.432 ;
     RECT  55.177 108.336 55.429 108.36 ;
     RECT  52.837 63.216 55.477 63.672 ;
     RECT  54.469 113.184 55.477 123.288 ;
     RECT  55.043 86.736 55.493 89.88 ;
     RECT  54.817 91.104 55.493 100.92 ;
     RECT  55.249 45.168 55.573 45.288 ;
     RECT  54.349 56.256 55.573 57.576 ;
     RECT  54.637 58.896 55.573 60.648 ;
     RECT  55.477 113.04 55.573 123.288 ;
     RECT  55.573 112.992 55.621 123.288 ;
     RECT  55.141 29.664 55.645 30.648 ;
     RECT  55.429 107.568 55.645 108.36 ;
     RECT  55.285 40.032 55.717 43.896 ;
     RECT  55.573 44.88 55.717 45.288 ;
     RECT  55.141 36.816 55.753 36.84 ;
     RECT  55.213 101.952 55.753 104.856 ;
     RECT  54.025 105.936 55.753 105.96 ;
     RECT  55.645 28.8 55.897 30.648 ;
     RECT  55.357 33.12 55.897 35.208 ;
     RECT  54.605 46.752 55.897 49.224 ;
     RECT  55.897 28.8 55.933 31.272 ;
     RECT  55.897 33.072 55.933 35.208 ;
     RECT  55.753 36.816 55.957 37.416 ;
     RECT  55.621 112.704 55.957 123.288 ;
     RECT  55.333 124.608 55.957 126.456 ;
     RECT  55.645 27.168 55.969 27.192 ;
     RECT  55.933 28.8 55.969 35.208 ;
     RECT  55.957 112.704 56.005 126.456 ;
     RECT  55.897 46.32 56.041 49.224 ;
     RECT  55.141 50.304 56.041 55.272 ;
     RECT  55.645 107.52 56.041 108.696 ;
     RECT  55.357 109.728 56.041 111.432 ;
     RECT  56.005 112.464 56.041 126.456 ;
     RECT  55.477 63.216 56.053 63.816 ;
     RECT  56.041 107.52 56.113 126.456 ;
     RECT  55.957 36.816 56.149 37.656 ;
     RECT  55.493 86.736 56.149 100.92 ;
     RECT  55.177 38.688 56.245 39 ;
     RECT  55.717 40.032 56.245 45.288 ;
     RECT  55.969 27.12 56.257 27.192 ;
     RECT  55.969 28.176 56.257 35.208 ;
     RECT  56.149 36.624 56.257 37.656 ;
     RECT  56.257 27.12 56.293 37.656 ;
     RECT  55.573 56.256 56.293 60.648 ;
     RECT  56.245 38.688 56.365 45.288 ;
     RECT  56.041 46.32 56.365 55.272 ;
     RECT  56.149 86.64 56.365 100.92 ;
     RECT  55.753 101.952 56.365 105.96 ;
     RECT  51.304 24.72 56.408 25.32 ;
     RECT  56.293 26.832 56.408 37.656 ;
     RECT  56.365 38.688 56.408 55.272 ;
     RECT  56.293 56.256 56.408 61.416 ;
     RECT  56.053 62.448 56.408 63.816 ;
     RECT  55.283 66.672 56.408 85.272 ;
     RECT  56.365 86.64 56.408 105.96 ;
     RECT  56.113 107.28 56.408 126.456 ;
     RECT  56.408 2.148 56.512 149.052 ;
     RECT  56.512 2.418 56.704 148.782 ;
     RECT  56.704 24.72 57.233 63.816 ;
     RECT  57.233 40.848 57.251 63.816 ;
     RECT  57.233 24.72 57.269 39.816 ;
     RECT  57.269 24.72 57.521 39.72 ;
     RECT  56.704 69.216 57.593 85.224 ;
     RECT  57.521 24.72 57.629 37.128 ;
     RECT  57.629 24.72 57.737 30.6 ;
     RECT  57.593 70.368 57.769 85.224 ;
     RECT  57.629 31.728 57.773 37.128 ;
     RECT  56.704 66.624 57.809 68.136 ;
     RECT  56.704 86.736 57.829 126.456 ;
     RECT  57.769 70.368 57.877 85.56 ;
     RECT  57.829 86.688 57.877 126.456 ;
     RECT  57.737 24.72 57.913 27.672 ;
     RECT  57.809 66.72 58.093 68.136 ;
     RECT  57.593 69.216 58.093 69.24 ;
     RECT  57.913 24.624 58.309 27.672 ;
     RECT  57.521 38.736 58.597 39.72 ;
     RECT  57.251 40.944 58.597 63.816 ;
     RECT  57.737 29.328 58.669 30.6 ;
     RECT  57.773 31.728 58.669 33 ;
     RECT  57.773 34.032 58.669 37.128 ;
     RECT  58.597 38.736 58.669 63.816 ;
     RECT  58.309 24.528 58.705 27.672 ;
     RECT  58.669 29.328 58.705 33 ;
     RECT  57.877 70.368 58.705 126.456 ;
     RECT  58.705 24.528 58.741 33 ;
     RECT  58.669 34.032 58.741 63.816 ;
     RECT  58.093 66.72 58.741 69.24 ;
     RECT  58.705 70.272 58.741 126.456 ;
     RECT  59.509 65.136 59.605 65.16 ;
     RECT  58.741 66.72 59.749 126.456 ;
     RECT  59.749 66.72 60.185 126.504 ;
     RECT  58.741 24.528 60.552 63.816 ;
     RECT  59.605 64.992 60.552 65.16 ;
     RECT  60.185 67.248 60.552 126.504 ;
     RECT  60.552 23.76 60.707 65.16 ;
     RECT  60.707 23.76 60.803 65.112 ;
     RECT  60.803 23.76 60.899 65.064 ;
     RECT  60.552 67.248 60.947 127.44 ;
     RECT  60.947 85.488 61.265 127.44 ;
     RECT  60.947 67.248 61.808 84.252 ;
     RECT  61.808 2.148 61.912 21.612 ;
     RECT  61.808 66.948 61.912 84.252 ;
     RECT  61.808 129.588 61.912 149.052 ;
     RECT  61.912 2.418 62.104 21.342 ;
     RECT  61.912 66.948 62.104 84.12 ;
     RECT  61.912 129.858 62.104 148.782 ;
     RECT  62.104 66.948 62.845 69 ;
     RECT  62.845 66.72 63.173 69 ;
     RECT  62.104 70.608 63.173 84.12 ;
     RECT  63.173 67.248 63.829 69 ;
     RECT  63.173 71.28 63.875 84.12 ;
     RECT  63.829 67.248 64.109 69.528 ;
     RECT  64.573 70.272 64.937 70.296 ;
     RECT  64.109 67.248 65.113 69.048 ;
     RECT  65.113 67.248 65.945 69.288 ;
     RECT  65.945 69.264 66.697 69.288 ;
     RECT  63.875 71.376 66.697 84.12 ;
     RECT  66.697 69.264 66.841 69.72 ;
     RECT  66.697 71.04 66.841 84.12 ;
     RECT  65.945 67.248 67.208 68.232 ;
     RECT  66.841 69.264 67.208 84.12 ;
     RECT  67.208 2.148 67.312 21.612 ;
     RECT  67.208 66.948 67.312 84.252 ;
     RECT  67.208 129.588 67.312 149.052 ;
     RECT  67.312 2.418 67.504 21.342 ;
     RECT  67.312 67.218 67.504 84.12 ;
     RECT  67.312 129.858 67.504 148.782 ;
     RECT  67.504 67.296 67.781 69.864 ;
     RECT  67.781 68.976 68.973 69.864 ;
     RECT  67.504 71.376 68.973 84.12 ;
     RECT  67.781 67.296 69.001 67.704 ;
     RECT  68.973 68.976 69.001 84.12 ;
     RECT  69.001 67.296 69.329 84.12 ;
     RECT  69.329 67.296 70.049 69.048 ;
     RECT  70.049 67.296 71.665 67.704 ;
     RECT  71.665 67.248 71.881 67.704 ;
     RECT  70.049 68.688 71.881 69.048 ;
     RECT  71.881 67.248 72.061 69.048 ;
     RECT  69.329 70.176 72.061 84.12 ;
     RECT  72.061 67.248 72.608 84.12 ;
     RECT  72.608 2.148 72.712 21.612 ;
     RECT  72.608 66.948 72.712 84.252 ;
     RECT  72.608 129.588 72.712 149.052 ;
     RECT  72.712 2.418 72.904 21.342 ;
     RECT  72.712 67.218 72.904 84.12 ;
     RECT  72.712 129.858 72.904 148.782 ;
     RECT  72.904 67.296 73.433 84.12 ;
     RECT  73.433 67.344 75.161 84.12 ;
     RECT  75.161 67.68 76.165 84.12 ;
     RECT  76.165 67.392 76.957 84.12 ;
     RECT  76.957 67.296 76.993 84.12 ;
     RECT  76.993 67.2 78.008 84.12 ;
     RECT  78.008 2.148 78.112 21.612 ;
     RECT  78.008 66.948 78.112 84.252 ;
     RECT  78.008 129.588 78.112 149.052 ;
     RECT  78.112 2.418 78.304 21.342 ;
     RECT  78.112 67.218 78.304 84.12 ;
     RECT  78.112 129.858 78.304 148.782 ;
     RECT  78.304 67.584 79.301 84.12 ;
     RECT  79.301 67.584 80.269 69.72 ;
     RECT  79.301 70.704 80.269 84.12 ;
     RECT  80.269 67.584 80.953 84.12 ;
     RECT  80.953 67.488 81.205 84.12 ;
     RECT  81.205 67.44 81.277 84.12 ;
     RECT  81.277 67.344 83.408 84.12 ;
     RECT  83.408 2.148 83.512 21.612 ;
     RECT  83.408 66.948 83.512 84.252 ;
     RECT  83.408 129.588 83.512 149.052 ;
     RECT  83.512 2.418 83.704 21.342 ;
     RECT  83.512 67.218 83.704 84.12 ;
     RECT  83.512 129.858 83.704 148.782 ;
     RECT  83.704 67.68 86.209 84.12 ;
     RECT  86.209 67.584 86.605 84.12 ;
     RECT  86.605 67.344 86.789 84.12 ;
     RECT  86.789 67.584 87.329 84.12 ;
     RECT  87.329 67.584 88.808 69.528 ;
     RECT  87.329 70.512 88.808 84.12 ;
     RECT  88.808 2.148 88.912 21.612 ;
     RECT  88.808 66.948 88.912 84.252 ;
     RECT  88.808 129.588 88.912 149.052 ;
     RECT  88.912 2.418 89.104 21.342 ;
     RECT  88.912 67.218 89.104 84.12 ;
     RECT  88.912 129.858 89.104 148.782 ;
     RECT  89.104 71.184 89.795 84.12 ;
     RECT  89.104 67.68 90.323 70.152 ;
     RECT  90.323 67.68 90.493 70.008 ;
     RECT  90.493 67.632 90.673 70.008 ;
     RECT  89.795 71.376 91.765 84.12 ;
     RECT  90.673 67.296 91.901 70.008 ;
     RECT  91.765 71.184 91.901 84.12 ;
     RECT  91.901 67.296 92.009 69 ;
     RECT  92.009 67.68 92.941 69 ;
     RECT  91.901 69.984 92.941 70.008 ;
     RECT  91.901 71.28 94.021 84.12 ;
     RECT  92.941 67.68 94.208 70.008 ;
     RECT  94.021 71.184 94.208 84.12 ;
     RECT  94.208 2.148 94.312 21.612 ;
     RECT  94.208 66.948 94.312 84.252 ;
     RECT  94.208 129.588 94.312 149.052 ;
     RECT  94.312 2.418 94.504 21.342 ;
     RECT  94.312 67.218 94.504 84.12 ;
     RECT  94.312 129.858 94.504 148.782 ;
     RECT  94.504 67.68 94.637 69.864 ;
     RECT  94.637 67.68 95.609 69.048 ;
     RECT  95.609 67.68 95.753 68.76 ;
     RECT  94.504 70.848 95.933 84.12 ;
     RECT  95.753 67.68 95.969 68.376 ;
     RECT  95.969 67.68 96.365 68.328 ;
     RECT  96.365 67.68 96.545 68.136 ;
     RECT  95.933 71.04 97.405 84.12 ;
     RECT  96.545 67.68 97.945 67.704 ;
     RECT  97.945 67.68 97.985 68.904 ;
     RECT  97.405 70.704 98.377 84.12 ;
     RECT  98.377 70.656 98.953 84.12 ;
     RECT  97.985 67.92 99.608 68.904 ;
     RECT  98.953 70.032 99.608 84.12 ;
     RECT  99.608 2.148 99.712 21.612 ;
     RECT  99.608 66.948 99.712 84.252 ;
     RECT  99.608 129.588 99.712 149.052 ;
     RECT  99.712 2.418 99.904 21.342 ;
     RECT  99.712 67.218 99.904 84.12 ;
     RECT  99.712 129.858 99.904 148.782 ;
     RECT  99.904 70.032 100.547 70.056 ;
     RECT  100.897 69.504 101.009 69.528 ;
     RECT  99.904 71.376 105.008 84.12 ;
     RECT  105.008 2.148 105.112 21.612 ;
     RECT  105.008 66.948 105.112 84.252 ;
     RECT  105.008 129.588 105.112 149.052 ;
     RECT  105.112 2.418 105.304 21.342 ;
     RECT  105.112 67.218 105.304 84.12 ;
     RECT  105.112 129.858 105.304 148.782 ;
     RECT  105.304 71.376 107.057 84.12 ;
     RECT  107.057 71.376 107.381 83.64 ;
     RECT  107.381 71.616 110.408 83.64 ;
     RECT  110.408 2.148 110.512 21.612 ;
     RECT  110.408 66.948 110.512 84.252 ;
     RECT  110.408 129.588 110.512 149.052 ;
     RECT  110.512 2.418 110.704 21.342 ;
     RECT  110.512 67.218 110.704 83.982 ;
     RECT  110.512 129.858 110.704 148.782 ;
     RECT  110.704 71.616 110.86 83.64 ;
     RECT  110.86 71.616 113.429 71.784 ;
     RECT  110.86 72.96 113.645 83.64 ;
     RECT  113.429 71.76 114.577 71.784 ;
     RECT  114.577 71.664 114.613 71.784 ;
     RECT  113.645 72.96 114.613 73.272 ;
     RECT  114.613 71.664 114.653 73.272 ;
     RECT  114.653 71.664 115.808 73.128 ;
     RECT  113.645 74.4 115.808 83.64 ;
     RECT  115.808 2.148 115.912 21.612 ;
     RECT  115.808 66.948 115.912 84.252 ;
     RECT  115.808 129.588 115.912 149.052 ;
     RECT  115.912 2.418 116.104 21.342 ;
     RECT  115.912 67.218 116.104 83.982 ;
     RECT  115.912 129.858 116.104 148.782 ;
     RECT  116.104 71.664 117.587 83.64 ;
     RECT  117.587 71.76 118.289 83.64 ;
     RECT  118.289 71.76 119.977 72.984 ;
     RECT  118.289 74.016 119.977 83.64 ;
     RECT  119.977 71.76 120.409 83.64 ;
     RECT  120.409 71.184 121.208 83.64 ;
     RECT  121.208 2.148 121.312 21.612 ;
     RECT  121.208 66.948 121.312 84.252 ;
     RECT  121.208 129.588 121.312 149.052 ;
     RECT  121.312 2.418 121.504 21.342 ;
     RECT  121.312 67.218 121.504 83.982 ;
     RECT  121.312 129.858 121.504 148.782 ;
     RECT  121.504 81.312 122.033 83.64 ;
     RECT  121.504 71.088 122.485 79.8 ;
     RECT  122.485 70.848 122.497 79.8 ;
     RECT  122.497 70.704 124.157 79.8 ;
     RECT  122.033 81.312 124.337 82.776 ;
     RECT  124.337 82.752 124.445 82.776 ;
     RECT  124.157 71.664 126.608 79.8 ;
     RECT  124.337 81.312 126.608 81.672 ;
     RECT  124.801 82.992 126.608 83.016 ;
     RECT  126.608 2.148 126.712 21.612 ;
     RECT  126.608 66.948 126.712 84.252 ;
     RECT  126.608 129.588 126.712 149.052 ;
     RECT  126.712 2.418 126.904 21.342 ;
     RECT  126.712 67.218 126.904 83.982 ;
     RECT  126.712 129.858 126.904 148.782 ;
     RECT  126.904 71.712 128.297 79.8 ;
     RECT  128.297 71.712 128.333 78.744 ;
     RECT  128.333 71.712 128.531 78.504 ;
     RECT  128.531 71.76 130.349 78.504 ;
     RECT  130.349 73.056 131.605 78.504 ;
     RECT  130.349 71.76 132.008 71.784 ;
     RECT  131.605 72.912 132.008 78.504 ;
     RECT  128.297 79.776 132.008 79.8 ;
     RECT  126.904 81.312 132.008 81.672 ;
     RECT  126.904 83.088 132.008 83.112 ;
     RECT  132.008 2.148 132.112 21.612 ;
     RECT  132.008 66.948 132.112 84.252 ;
     RECT  132.008 129.588 132.112 149.052 ;
     RECT  132.112 2.418 132.304 21.342 ;
     RECT  132.112 67.218 132.304 83.982 ;
     RECT  132.112 129.858 132.304 148.782 ;
     RECT  132.304 71.76 133.193 78.504 ;
     RECT  133.193 73.488 135.857 78.504 ;
     RECT  133.193 71.76 137.408 71.784 ;
     RECT  135.857 73.632 137.408 78.504 ;
     RECT  132.304 79.776 137.408 79.8 ;
     RECT  132.304 81.312 137.408 81.672 ;
     RECT  132.304 83.088 137.408 83.112 ;
     RECT  137.408 2.148 137.512 21.612 ;
     RECT  137.408 66.948 137.512 84.252 ;
     RECT  137.408 129.588 137.512 149.052 ;
     RECT  137.512 2.418 137.704 21.342 ;
     RECT  137.512 67.218 137.704 83.982 ;
     RECT  137.512 129.858 137.704 148.782 ;
     RECT  137.704 73.632 138.269 78.504 ;
     RECT  138.269 73.872 138.737 78.504 ;
     RECT  138.737 73.872 139.529 75.288 ;
     RECT  137.704 81.312 141.545 81.672 ;
     RECT  137.704 71.76 142.808 71.784 ;
     RECT  139.529 73.872 142.808 73.896 ;
     RECT  139.529 74.976 142.808 75.288 ;
     RECT  138.737 76.848 142.808 78.504 ;
     RECT  137.704 79.776 142.808 79.8 ;
     RECT  141.545 81.312 142.808 81.336 ;
     RECT  137.704 83.088 142.808 83.112 ;
     RECT  142.808 2.148 142.912 21.612 ;
     RECT  142.808 66.948 142.912 84.252 ;
     RECT  142.808 129.588 142.912 149.052 ;
     RECT  142.912 2.418 143.104 21.342 ;
     RECT  142.912 67.218 143.104 83.982 ;
     RECT  142.912 129.858 143.104 148.782 ;
     RECT  143.104 74.976 143.219 75.288 ;
     RECT  143.104 81.312 143.219 81.528 ;
     RECT  143.219 81.312 146.473 81.336 ;
     RECT  146.473 81.168 146.513 81.336 ;
     RECT  143.104 71.76 148.208 71.784 ;
     RECT  143.104 72.912 148.208 73.896 ;
     RECT  143.219 75.12 148.208 75.288 ;
     RECT  143.104 76.848 148.208 78.504 ;
     RECT  143.104 79.776 148.208 79.8 ;
     RECT  146.513 81.168 148.208 81.192 ;
     RECT  143.104 83.088 148.208 83.112 ;
     RECT  148.208 2.148 148.312 21.612 ;
     RECT  148.208 66.948 148.312 84.252 ;
     RECT  148.208 129.588 148.312 149.052 ;
     RECT  148.312 2.418 148.504 21.342 ;
     RECT  148.312 67.218 148.504 83.982 ;
     RECT  148.312 129.858 148.504 148.782 ;
     RECT  148.504 79.776 149.941 79.8 ;
     RECT  148.504 81.168 149.941 83.112 ;
     RECT  149.941 79.776 149.987 83.112 ;
     RECT  149.987 80.496 150.028 83.112 ;
     RECT  150.028 81.168 150.509 83.112 ;
     RECT  60.899 23.76 150.997 64.8 ;
     RECT  150.509 81.168 151.244 83.016 ;
     RECT  151.244 80.352 151.285 83.016 ;
     RECT  151.285 79.776 151.331 83.016 ;
     RECT  151.331 82.08 151.625 83.016 ;
     RECT  151.331 79.776 151.661 79.8 ;
     RECT  148.504 71.76 153.608 71.784 ;
     RECT  148.504 72.912 153.608 73.896 ;
     RECT  148.504 75.12 153.608 75.288 ;
     RECT  148.504 76.848 153.608 78.504 ;
     RECT  152.593 81.072 153.608 81.096 ;
     RECT  151.625 82.992 153.608 83.016 ;
     RECT  153.608 2.148 153.712 21.612 ;
     RECT  153.608 66.948 153.712 84.252 ;
     RECT  153.608 129.588 153.712 149.052 ;
     RECT  153.712 2.418 153.904 21.342 ;
     RECT  153.712 67.218 153.904 83.982 ;
     RECT  153.712 129.858 153.904 148.782 ;
     RECT  153.904 72.816 154.897 75.384 ;
     RECT  153.904 76.848 154.897 79.8 ;
     RECT  154.861 84.96 154.897 84.984 ;
     RECT  61.265 86.4 154.897 127.44 ;
     RECT  154.897 72.816 154.969 79.8 ;
     RECT  153.904 81.072 154.969 81.24 ;
     RECT  153.904 82.224 154.969 83.256 ;
     RECT  154.969 72.816 155.029 79.992 ;
     RECT  154.969 81.024 155.029 81.24 ;
     RECT  154.969 70.512 155.077 70.536 ;
     RECT  153.904 71.76 155.077 71.784 ;
     RECT  155.029 72.816 155.077 81.24 ;
     RECT  154.969 82.224 155.077 83.304 ;
     RECT  155.041 68.544 155.113 68.568 ;
     RECT  155.077 70.512 155.113 71.784 ;
     RECT  155.077 72.816 155.113 83.304 ;
     RECT  150.997 23.328 155.185 64.8 ;
     RECT  155.185 23.328 155.232 64.968 ;
     RECT  154.897 84.96 155.232 127.44 ;
     RECT  155.113 70.512 155.249 83.304 ;
     RECT  155.249 70.416 155.317 83.304 ;
     RECT  155.317 70.416 155.333 83.88 ;
     RECT  155.232 23.328 155.405 23.352 ;
     RECT  155.232 24.528 155.405 63.72 ;
     RECT  155.232 87.168 155.405 126.36 ;
     RECT  155.405 45.072 155.441 51.24 ;
     RECT  155.405 54.384 155.441 63.72 ;
     RECT  155.405 101.376 155.441 107.832 ;
     RECT  155.441 104.736 155.459 107.832 ;
     RECT  155.441 48.24 155.477 51.24 ;
     RECT  155.441 57.456 155.477 63.72 ;
     RECT  155.405 24.528 155.507 35.88 ;
     RECT  155.333 70.512 155.507 83.88 ;
     RECT  155.441 54.384 155.513 55.752 ;
     RECT  155.477 58.704 155.513 63.72 ;
     RECT  155.441 101.376 155.513 101.688 ;
     RECT  155.513 58.704 155.549 63.624 ;
     RECT  155.232 84.96 155.555 85.608 ;
     RECT  155.405 87.168 155.555 99.192 ;
     RECT  155.555 84.96 155.581 85.512 ;
     RECT  155.555 87.168 155.603 98.328 ;
     RECT  155.113 68.544 155.617 69.24 ;
     RECT  155.477 51.216 155.621 51.24 ;
     RECT  155.405 123.168 155.621 126.264 ;
     RECT  155.405 113.952 155.651 113.976 ;
     RECT  155.513 101.52 155.657 101.688 ;
     RECT  155.581 84.912 155.665 85.512 ;
     RECT  155.507 24.528 155.699 35.736 ;
     RECT  155.665 85.488 155.699 85.512 ;
     RECT  155.459 107.808 155.699 107.832 ;
     RECT  155.617 68.4 155.843 69.24 ;
     RECT  155.232 64.848 155.891 64.968 ;
     RECT  155.699 24.624 155.909 35.736 ;
     RECT  155.909 24.72 155.987 35.736 ;
     RECT  155.891 64.848 156.125 64.92 ;
     RECT  155.761 66.768 156.373 66.792 ;
     RECT  155.843 69.216 156.373 69.24 ;
     RECT  155.507 70.512 156.373 83.784 ;
     RECT  155.977 67.824 156.419 67.848 ;
     RECT  156.373 66.72 156.46 66.84 ;
     RECT  155.549 60.528 156.517 63.624 ;
     RECT  156.46 66.816 156.521 66.84 ;
     RECT  156.373 69.216 156.613 83.784 ;
     RECT  156.517 60.528 156.629 64.44 ;
     RECT  155.987 24.816 156.701 35.736 ;
     RECT  156.613 69.216 156.733 83.832 ;
     RECT  156.733 69.216 156.737 83.88 ;
     RECT  156.629 60.528 156.773 63.624 ;
     RECT  155.621 123.36 156.773 126.264 ;
     RECT  156.737 70.608 157.069 83.88 ;
     RECT  157.069 71.76 157.091 83.88 ;
     RECT  155.603 87.168 157.097 98.232 ;
     RECT  157.097 87.168 157.139 92.856 ;
     RECT  157.139 87.168 157.169 92.664 ;
     RECT  156.773 123.36 157.277 124.44 ;
     RECT  157.277 123.36 157.313 123.384 ;
     RECT  157.277 124.416 157.313 124.44 ;
     RECT  157.097 93.984 157.349 98.232 ;
     RECT  156.737 69.216 157.475 69.24 ;
     RECT  157.091 71.76 157.523 75.816 ;
     RECT  156.773 60.528 157.565 63.528 ;
     RECT  156.773 125.76 157.565 126.264 ;
     RECT  157.523 71.76 157.571 75.288 ;
     RECT  157.349 93.984 157.571 97.752 ;
     RECT  157.571 93.984 157.637 95.832 ;
     RECT  157.565 125.76 157.637 126.168 ;
     RECT  157.637 94.08 157.706 95.832 ;
     RECT  157.571 96.864 157.781 97.752 ;
     RECT  157.637 126.144 157.853 126.168 ;
     RECT  155.405 120.096 157.925 120.12 ;
     RECT  155.405 110.88 157.961 110.904 ;
     RECT  157.091 76.848 158.003 83.88 ;
     RECT  155.405 38.928 158.437 38.952 ;
     RECT  157.741 66.672 158.437 66.696 ;
     RECT  157.069 70.608 158.437 70.68 ;
     RECT  157.169 87.168 158.437 92.472 ;
     RECT  158.003 76.848 158.54 80.376 ;
     RECT  156.701 24.816 159.008 26.568 ;
     RECT  156.701 27.6 159.008 35.736 ;
     RECT  158.437 38.688 159.008 38.952 ;
     RECT  155.405 41.616 159.008 41.64 ;
     RECT  158.437 42.72 159.008 42.84 ;
     RECT  155.441 45.072 159.008 45.096 ;
     RECT  158.437 46.656 159.008 46.776 ;
     RECT  158.437 50.688 159.008 50.808 ;
     RECT  158.437 54.624 159.008 54.744 ;
     RECT  158.437 58.656 159.008 58.776 ;
     RECT  157.565 60.624 159.008 63.528 ;
     RECT  158.437 66.672 159.008 66.792 ;
     RECT  158.437 70.608 159.008 70.728 ;
     RECT  157.571 71.76 159.008 71.784 ;
     RECT  157.571 72.816 159.008 75.288 ;
     RECT  158.54 76.704 159.008 80.376 ;
     RECT  158.003 81.744 159.008 83.88 ;
     RECT  158.437 86.544 159.008 92.472 ;
     RECT  157.706 94.08 159.008 95.784 ;
     RECT  157.781 97.44 159.008 97.752 ;
     RECT  155.405 117.216 159.008 117.24 ;
     RECT  159.008 2.148 159.112 149.052 ;
     RECT  159.112 2.418 159.304 148.782 ;
     RECT  159.304 35.712 159.365 35.736 ;
     RECT  159.304 81.648 159.365 81.672 ;
     RECT  159.304 25.008 159.401 25.032 ;
     RECT  159.304 88.128 159.401 89.736 ;
     RECT  159.401 89.712 159.437 89.736 ;
     RECT  159.401 88.128 159.473 88.488 ;
     RECT  159.304 72.912 159.509 75.288 ;
     RECT  159.473 88.128 159.509 88.152 ;
     RECT  159.304 90.864 159.653 91.992 ;
     RECT  159.304 31.68 159.689 33.336 ;
     RECT  159.304 76.848 159.689 79.704 ;
     RECT  159.304 94.08 159.689 95.784 ;
     RECT  159.304 26.064 159.725 26.568 ;
     RECT  159.509 72.912 159.725 74.136 ;
     RECT  159.689 94.08 159.725 95.448 ;
     RECT  159.725 94.128 159.761 95.448 ;
     RECT  159.304 34.704 159.869 34.728 ;
     RECT  159.653 91.104 159.869 91.992 ;
     RECT  159.689 31.728 159.905 33.336 ;
     RECT  159.761 94.128 159.905 94.68 ;
     RECT  159.304 69.504 159.913 69.528 ;
     RECT  159.869 91.104 159.941 91.656 ;
     RECT  159.905 94.128 159.977 94.152 ;
     RECT  159.725 26.256 160.013 26.568 ;
     RECT  159.304 60.912 160.157 63.336 ;
     RECT  159.304 27.6 160.193 30.168 ;
     RECT  159.941 91.344 160.193 91.656 ;
     RECT  159.304 82.704 160.229 83.88 ;
     RECT  160.193 29.616 160.265 30.168 ;
     RECT  160.229 83.808 160.265 83.88 ;
     RECT  160.013 26.256 160.337 26.28 ;
     RECT  159.689 76.848 160.337 78.936 ;
     RECT  160.193 27.6 160.373 28.008 ;
     RECT  159.905 32.784 160.409 33.336 ;
     RECT  160.409 32.784 160.445 32.808 ;
     RECT  159.905 31.728 160.481 31.752 ;
     RECT  160.193 91.632 160.517 91.656 ;
     RECT  160.373 27.984 160.553 28.008 ;
     RECT  160.265 83.808 160.553 83.832 ;
     RECT  160.265 29.616 160.589 29.64 ;
     RECT  160.229 82.704 160.589 82.728 ;
     RECT  160.157 61.392 160.805 63.336 ;
     RECT  160.805 61.392 162.497 62.856 ;
     RECT  159.509 75.12 162.515 75.288 ;
     RECT  159.725 72.912 162.997 73.896 ;
     RECT  162.997 72.816 163.037 73.896 ;
     RECT  159.304 71.76 164.041 71.784 ;
     RECT  163.037 72.816 164.041 72.84 ;
     RECT  162.497 61.392 164.408 62.328 ;
     RECT  164.041 71.76 164.408 72.84 ;
     RECT  163.037 73.872 164.408 73.896 ;
     RECT  162.515 75.264 164.408 75.288 ;
     RECT  160.337 76.848 164.408 77.976 ;
     RECT  164.408 2.148 164.512 149.052 ;
     RECT  164.512 2.418 164.704 148.782 ;
     RECT  164.704 61.392 165.989 62.28 ;
     RECT  165.989 62.16 166.169 62.28 ;
     RECT  166.169 62.16 168.041 62.184 ;
     RECT  164.704 71.76 168.661 73.896 ;
     RECT  164.704 75.264 168.661 75.288 ;
     RECT  168.661 71.76 168.707 75.288 ;
     RECT  168.707 71.76 169.808 72.168 ;
     RECT  168.707 73.872 169.808 75.288 ;
     RECT  164.704 76.848 169.808 77.976 ;
     RECT  169.808 2.148 169.912 149.052 ;
     RECT  169.912 2.418 170.104 148.782 ;
     RECT  170.104 71.76 175.208 72.168 ;
     RECT  170.104 73.872 175.208 75.288 ;
     RECT  170.104 76.848 175.208 77.976 ;
     RECT  175.208 2.148 175.312 149.052 ;
     RECT  175.312 2.418 175.504 148.782 ;
     RECT  175.504 71.76 180.608 72.168 ;
     RECT  175.504 73.872 180.608 75.288 ;
     RECT  175.504 76.848 180.608 77.976 ;
     RECT  180.608 2.148 180.712 149.052 ;
     RECT  180.712 2.418 180.904 148.782 ;
     RECT  180.904 71.76 186.008 72.168 ;
     RECT  180.904 73.872 186.008 75.288 ;
     RECT  180.904 76.848 186.008 77.976 ;
     RECT  186.008 2.148 186.112 149.052 ;
     RECT  186.112 2.418 186.304 148.782 ;
     RECT  186.304 71.76 189.997 72.168 ;
     RECT  186.304 73.872 189.997 75.288 ;
     RECT  189.997 71.76 190.391 75.288 ;
     RECT  190.391 71.76 190.573 75.336 ;
     RECT  190.573 71.76 191.408 75.432 ;
     RECT  186.304 76.848 191.408 77.976 ;
     RECT  191.408 2.148 191.512 149.052 ;
     RECT  191.512 2.418 191.704 148.782 ;
     RECT  191.704 71.76 191.843 75.432 ;
     RECT  191.843 71.76 193.093 72.168 ;
     RECT  191.843 73.488 193.093 75.432 ;
     RECT  193.093 71.76 194.389 75.432 ;
     RECT  194.389 71.664 194.897 75.432 ;
     RECT  194.897 71.664 195.185 74.952 ;
     RECT  195.185 71.664 196.441 74.904 ;
     RECT  194.245 68.928 196.808 68.952 ;
     RECT  196.441 71.664 196.808 75.432 ;
     RECT  191.704 76.848 196.808 77.976 ;
     RECT  196.808 2.148 196.912 149.052 ;
     RECT  196.912 2.418 197.104 148.782 ;
     RECT  197.104 71.76 198.097 75.816 ;
     RECT  198.097 71.616 198.701 75.816 ;
     RECT  198.701 71.232 199.109 75.816 ;
     RECT  199.109 71.232 199.285 71.88 ;
     RECT  199.285 71.04 199.577 71.88 ;
     RECT  199.109 73.008 200.245 75.816 ;
     RECT  197.104 76.848 200.245 77.976 ;
     RECT  199.577 71.472 200.581 71.88 ;
     RECT  200.245 73.008 200.581 77.976 ;
     RECT  200.581 71.472 200.945 77.976 ;
     RECT  200.257 68.976 201.836 69 ;
     RECT  200.945 71.472 202.057 71.688 ;
     RECT  201.836 68.976 202.208 69.72 ;
     RECT  202.057 71.184 202.208 71.688 ;
     RECT  200.945 72.816 202.208 77.976 ;
     RECT  202.208 2.148 202.312 149.052 ;
     RECT  202.312 2.418 202.504 148.782 ;
     RECT  202.504 69.408 203.641 69.432 ;
     RECT  202.504 70.992 203.651 77.976 ;
     RECT  203.641 68.64 203.749 69.432 ;
     RECT  203.749 68.64 203.833 70.104 ;
     RECT  203.833 68.64 204.077 69.432 ;
     RECT  203.651 71.184 204.329 77.976 ;
     RECT  204.329 71.184 204.401 77.304 ;
     RECT  204.077 68.64 204.433 68.664 ;
     RECT  204.401 71.28 204.437 77.304 ;
     RECT  204.437 73.008 204.653 77.304 ;
     RECT  204.653 76.848 205.369 77.304 ;
     RECT  204.433 68.112 205.405 68.664 ;
     RECT  204.437 71.28 205.441 71.928 ;
     RECT  204.653 73.008 205.441 75.768 ;
     RECT  205.441 70.944 205.729 75.768 ;
     RECT  205.369 76.848 205.769 78.072 ;
     RECT  205.729 70.944 205.981 75.816 ;
     RECT  205.769 76.848 205.981 77.688 ;
     RECT  205.981 70.944 206.053 77.688 ;
     RECT  206.053 70.704 206.381 77.688 ;
     RECT  206.381 76.848 207.013 77.688 ;
     RECT  205.405 68.112 207.26 68.952 ;
     RECT  206.381 70.704 207.457 75.816 ;
     RECT  207.013 76.848 207.457 78.6 ;
     RECT  207.26 67.488 207.608 68.952 ;
     RECT  207.457 70.704 207.608 78.6 ;
     RECT  207.608 2.148 207.712 149.052 ;
     RECT  207.712 2.418 207.904 148.782 ;
     RECT  207.904 68.928 208.325 75.24 ;
     RECT  207.904 76.752 208.721 77.544 ;
     RECT  208.721 77.424 209.117 77.544 ;
     RECT  207.904 67.68 209.369 67.704 ;
     RECT  208.325 68.928 209.369 72.84 ;
     RECT  209.369 69.216 209.653 72.84 ;
     RECT  208.325 73.968 209.653 75.24 ;
     RECT  209.653 69.216 209.693 75.24 ;
     RECT  209.117 77.424 209.693 77.448 ;
     RECT  209.693 69.216 209.801 73.368 ;
     RECT  209.801 70.656 209.837 73.368 ;
     RECT  209.725 76.32 210.301 76.344 ;
     RECT  209.801 69.216 210.337 69.528 ;
     RECT  209.693 74.352 210.445 75.24 ;
     RECT  210.301 76.32 210.445 77.064 ;
     RECT  209.837 71.04 210.449 73.368 ;
     RECT  210.337 68.544 210.485 69.528 ;
     RECT  210.449 71.04 210.949 71.208 ;
     RECT  210.449 72.192 211.057 73.368 ;
     RECT  210.445 74.352 211.057 77.064 ;
     RECT  211.057 72.192 211.061 77.064 ;
     RECT  210.949 70.992 211.129 71.208 ;
     RECT  211.061 77.04 211.349 77.064 ;
     RECT  211.129 70.56 211.453 71.208 ;
     RECT  211.061 72.192 211.453 75.72 ;
     RECT  210.485 69.456 211.489 69.528 ;
     RECT  211.453 70.56 211.489 75.72 ;
     RECT  212.641 68.112 212.749 68.136 ;
     RECT  211.489 69.456 212.857 75.72 ;
     RECT  212.749 67.392 212.929 68.136 ;
     RECT  212.857 69.456 212.929 76.008 ;
     RECT  212.929 67.392 213.008 76.008 ;
     RECT  212.965 77.136 213.008 77.16 ;
     RECT  213.008 2.148 213.112 149.052 ;
     RECT  213.112 2.418 213.304 148.782 ;
     RECT  213.304 70.56 213.473 77.16 ;
     RECT  213.473 70.56 213.581 76.584 ;
     RECT  213.581 70.608 214.693 76.584 ;
     RECT  213.304 67.392 215.921 69.192 ;
     RECT  215.921 67.536 215.964 69.192 ;
     RECT  214.693 70.608 215.964 76.68 ;
    LAYER M5 ;
     RECT  2.4 2.137 2.52 2.151 ;
     RECT  7.8 2.137 7.92 2.151 ;
     RECT  13.2 2.137 13.32 2.151 ;
     RECT  18.6 2.137 18.72 2.151 ;
     RECT  24 2.137 24.12 2.151 ;
     RECT  29.4 2.137 29.52 2.151 ;
     RECT  34.8 2.137 34.92 2.151 ;
     RECT  40.2 2.137 40.32 2.151 ;
     RECT  45.6 2.137 45.72 2.151 ;
     RECT  51 2.137 51.12 2.151 ;
     RECT  56.4 2.137 56.52 2.151 ;
     RECT  61.8 2.137 61.92 2.151 ;
     RECT  67.2 2.137 67.32 2.151 ;
     RECT  72.6 2.137 72.72 2.151 ;
     RECT  78 2.137 78.12 2.151 ;
     RECT  83.4 2.137 83.52 2.151 ;
     RECT  88.8 2.137 88.92 2.151 ;
     RECT  94.2 2.137 94.32 2.151 ;
     RECT  99.6 2.137 99.72 2.151 ;
     RECT  105 2.137 105.12 2.151 ;
     RECT  110.4 2.137 110.52 2.151 ;
     RECT  115.8 2.137 115.92 2.151 ;
     RECT  121.2 2.137 121.32 2.151 ;
     RECT  126.6 2.137 126.72 2.151 ;
     RECT  132 2.137 132.12 2.151 ;
     RECT  137.4 2.137 137.52 2.151 ;
     RECT  142.8 2.137 142.92 2.151 ;
     RECT  148.2 2.137 148.32 2.151 ;
     RECT  153.6 2.137 153.72 2.151 ;
     RECT  159 2.137 159.12 2.151 ;
     RECT  164.4 2.137 164.52 2.151 ;
     RECT  169.8 2.137 169.92 2.151 ;
     RECT  175.2 2.137 175.32 2.151 ;
     RECT  180.6 2.137 180.72 2.151 ;
     RECT  186 2.137 186.12 2.151 ;
     RECT  191.4 2.137 191.52 2.151 ;
     RECT  196.8 2.137 196.92 2.151 ;
     RECT  202.2 2.137 202.32 2.151 ;
     RECT  207.6 2.137 207.72 2.151 ;
     RECT  213 2.137 213.12 2.151 ;
     RECT  155.664 24.517 155.688 24.709 ;
     RECT  58.32 24.517 58.344 24.805 ;
     RECT  155.664 24.709 155.976 25.093 ;
     RECT  7.8 2.151 8.112 25.285 ;
     RECT  159 2.151 159.312 25.381 ;
     RECT  155.664 25.093 156.024 25.477 ;
     RECT  155.376 25.477 156.024 26.341 ;
     RECT  155.376 26.341 156.312 26.725 ;
     RECT  155.376 26.725 156.552 27.109 ;
     RECT  59.808 27.541 59.832 27.731 ;
     RECT  155.376 27.109 156.6 27.781 ;
     RECT  56.4 2.151 56.712 27.925 ;
     RECT  57.696 24.805 58.344 27.925 ;
     RECT  158.592 25.381 159.312 29.221 ;
     RECT  158.496 29.221 159.312 29.317 ;
     RECT  56.4 27.925 58.344 30.323 ;
     RECT  155.376 27.781 157.08 30.373 ;
     RECT  158.496 29.317 159.624 30.373 ;
     RECT  60.384 32.197 60.408 32.387 ;
     RECT  56.4 30.323 56.712 32.773 ;
     RECT  57.696 30.323 58.344 32.773 ;
     RECT  56.4 32.773 58.344 33.061 ;
     RECT  55.968 33.061 58.344 34.883 ;
     RECT  56.208 34.883 58.344 37.621 ;
     RECT  55.968 37.621 58.344 40.549 ;
     RECT  55.536 40.549 58.344 41.221 ;
     RECT  52.368 41.509 52.392 41.797 ;
     RECT  51 2.151 51.312 43.669 ;
     RECT  52.368 41.797 52.488 43.669 ;
     RECT  51 43.669 52.488 47.221 ;
     RECT  51 47.221 53.112 47.267 ;
     RECT  51 47.267 51.312 48.661 ;
     RECT  52.464 47.267 53.112 48.707 ;
     RECT  54.576 41.221 58.344 49.091 ;
     RECT  60.24 48.997 60.264 49.235 ;
     RECT  52.464 48.707 53.016 50.005 ;
     RECT  54.576 49.091 56.712 50.053 ;
     RECT  57.696 49.091 58.344 50.053 ;
     RECT  50.112 48.661 51.312 50.195 ;
     RECT  52.464 50.005 53.064 50.771 ;
     RECT  54.576 50.053 58.344 51.109 ;
     RECT  54.384 51.109 58.344 51.301 ;
     RECT  59.52 49.957 59.544 51.301 ;
     RECT  54.384 51.301 59.544 53.701 ;
     RECT  52.464 50.771 53.016 53.941 ;
     RECT  54.384 53.701 59.592 54.277 ;
     RECT  54.384 54.277 60.408 54.853 ;
     RECT  52.464 53.941 53.112 56.245 ;
     RECT  54.096 54.853 60.408 56.245 ;
     RECT  45.6 2.151 45.912 64.933 ;
     RECT  52.464 56.245 60.408 65.029 ;
     RECT  61.8 2.151 62.112 65.029 ;
     RECT  27.168 49.237 27.192 65.317 ;
     RECT  29.4 2.151 29.712 65.701 ;
     RECT  27.072 65.317 27.192 65.747 ;
     RECT  28.416 65.701 29.712 67.331 ;
     RECT  70.992 67.333 71.016 67.475 ;
     RECT  207.6 2.151 207.912 67.477 ;
     RECT  44.784 64.933 45.912 67.619 ;
     RECT  83.4 2.151 83.712 67.909 ;
     RECT  51 50.195 51.312 67.957 ;
     RECT  52.464 65.029 62.112 67.957 ;
     RECT  64.224 67.237 64.248 68.147 ;
     RECT  83.28 67.909 83.712 68.197 ;
     RECT  94.2 2.151 94.512 68.197 ;
     RECT  37.632 67.045 37.656 68.245 ;
     RECT  83.28 68.197 83.832 68.339 ;
     RECT  29.4 67.331 29.712 68.341 ;
     RECT  83.28 68.339 83.712 68.341 ;
     RECT  207.312 67.477 207.912 68.341 ;
     RECT  94.2 68.197 94.632 68.387 ;
     RECT  82.608 68.341 83.712 68.773 ;
     RECT  76.08 68.149 76.104 68.915 ;
     RECT  13.2 2.151 13.512 68.917 ;
     RECT  207.168 68.341 207.912 68.963 ;
     RECT  202.2 2.151 202.512 68.965 ;
     RECT  63.216 68.341 63.24 69.011 ;
     RECT  81.744 68.773 83.712 69.059 ;
     RECT  75.888 68.965 75.912 69.107 ;
     RECT  155.376 30.373 159.624 69.109 ;
     RECT  29.28 68.341 29.712 69.301 ;
     RECT  29.28 69.301 30.6 69.347 ;
     RECT  31.632 68.773 31.656 69.347 ;
     RECT  27.072 65.747 27.096 69.491 ;
     RECT  155.28 69.109 159.624 69.493 ;
     RECT  83.28 69.059 83.712 69.539 ;
     RECT  29.4 69.347 30.6 69.731 ;
     RECT  85.104 69.589 85.128 69.731 ;
     RECT  201.888 68.965 202.512 69.731 ;
     RECT  99.6 2.151 99.912 70.021 ;
     RECT  74.112 68.389 74.136 70.307 ;
     RECT  155.28 69.493 159.864 70.451 ;
     RECT  37.632 68.245 38.328 70.499 ;
     RECT  213 2.151 213.312 70.501 ;
     RECT  212.064 70.501 213.312 70.643 ;
     RECT  69.024 69.829 69.048 70.691 ;
     RECT  207.312 68.963 207.912 70.693 ;
     RECT  203.76 70.069 203.784 70.981 ;
     RECT  88.8 2.151 89.112 71.173 ;
     RECT  90.288 70.117 90.312 71.173 ;
     RECT  203.616 70.981 203.784 71.219 ;
     RECT  207.024 70.693 207.912 71.221 ;
     RECT  63.84 69.493 63.864 71.315 ;
     RECT  80.448 70.885 80.472 71.557 ;
     RECT  80.448 71.557 80.616 71.603 ;
     RECT  105 2.151 105.312 71.653 ;
     RECT  80.592 71.603 80.616 71.699 ;
     RECT  117.552 71.653 117.576 71.749 ;
     RECT  198.72 71.221 198.744 71.891 ;
     RECT  99.6 70.021 100.536 71.939 ;
     RECT  88.8 71.173 90.312 71.987 ;
     RECT  194.256 68.917 194.28 72.131 ;
     RECT  36.672 70.933 36.696 72.133 ;
     RECT  94.2 68.387 94.512 72.229 ;
     RECT  200.592 71.845 200.616 72.419 ;
     RECT  91.776 71.173 91.8 72.467 ;
     RECT  81.744 69.059 81.768 72.517 ;
     RECT  117.408 71.749 117.576 72.517 ;
     RECT  117.408 72.517 117.864 72.563 ;
     RECT  110.4 2.151 110.712 72.565 ;
     RECT  80.928 72.517 81.768 72.659 ;
     RECT  94.08 72.229 94.512 72.709 ;
     RECT  102.672 71.797 102.696 72.805 ;
     RECT  104.016 71.653 105.312 72.805 ;
     RECT  191.4 2.151 191.712 72.805 ;
     RECT  102.672 72.805 105.432 72.851 ;
     RECT  122.496 70.837 122.52 72.851 ;
     RECT  71.376 71.797 71.4 72.901 ;
     RECT  142.8 2.151 143.112 72.901 ;
     RECT  203.616 71.219 203.64 72.947 ;
     RECT  36.672 72.133 36.984 72.995 ;
     RECT  102.672 72.851 103.176 72.995 ;
     RECT  83.4 69.539 83.712 73.045 ;
     RECT  34.8 2.151 35.112 73.093 ;
     RECT  71.376 72.901 71.496 73.093 ;
     RECT  76.176 73.045 76.2 73.235 ;
     RECT  117.84 72.563 117.864 73.235 ;
     RECT  83.4 73.045 83.928 73.333 ;
     RECT  83.04 73.333 83.928 73.379 ;
     RECT  107.904 72.565 107.928 73.477 ;
     RECT  79.824 73.045 79.848 73.523 ;
     RECT  107.472 73.477 107.928 73.523 ;
     RECT  191.4 72.805 191.832 73.523 ;
     RECT  198.384 72.901 198.408 73.571 ;
     RECT  70.704 73.093 71.496 73.573 ;
     RECT  93.456 72.709 94.512 73.619 ;
     RECT  32.928 73.573 32.952 73.715 ;
     RECT  196.8 2.151 197.112 73.717 ;
     RECT  121.2 2.151 121.512 73.765 ;
     RECT  110.4 72.565 110.808 73.811 ;
     RECT  151.008 23.317 151.032 73.811 ;
     RECT  207.024 71.221 208.104 73.811 ;
     RECT  29.4 69.731 29.712 73.813 ;
     RECT  155.376 70.451 159.864 73.909 ;
     RECT  119.136 72.949 119.16 74.051 ;
     RECT  51 67.957 62.112 74.053 ;
     RECT  105 72.851 105.432 74.053 ;
     RECT  67.2 2.151 67.512 74.101 ;
     RECT  69.888 73.573 71.496 74.291 ;
     RECT  135.648 73.477 135.672 74.291 ;
     RECT  110.4 73.811 110.712 74.341 ;
     RECT  110.304 74.341 110.712 74.483 ;
     RECT  38.304 70.499 38.328 74.533 ;
     RECT  94.08 73.619 94.512 74.533 ;
     RECT  36.96 72.995 36.984 74.579 ;
     RECT  109.248 73.333 109.272 74.579 ;
     RECT  168.672 72.901 168.696 74.627 ;
     RECT  121.2 73.765 122.472 74.629 ;
     RECT  196.656 73.717 197.112 74.675 ;
     RECT  67.2 74.101 67.944 74.723 ;
     RECT  88.8 71.987 89.784 74.723 ;
     RECT  94.08 74.533 94.632 74.723 ;
     RECT  38.208 74.533 38.328 74.771 ;
     RECT  94.2 74.723 94.632 74.771 ;
     RECT  105 74.053 106.152 74.771 ;
     RECT  107.472 73.523 107.496 74.771 ;
     RECT  129.936 74.053 129.96 74.771 ;
     RECT  112.08 74.005 112.104 74.819 ;
     RECT  34.272 73.093 35.112 74.821 ;
     RECT  133.92 74.101 133.944 74.963 ;
     RECT  24 2.151 24.312 74.965 ;
     RECT  51 74.053 62.328 74.965 ;
     RECT  99.6 71.939 99.912 74.965 ;
     RECT  5.184 50.581 5.208 75.013 ;
     RECT  113.568 73.477 113.592 75.013 ;
     RECT  34.272 74.821 35.208 75.059 ;
     RECT  96.912 74.965 96.936 75.061 ;
     RECT  95.664 74.053 95.688 75.107 ;
     RECT  4.704 75.013 5.496 75.109 ;
     RECT  99.6 74.965 100.632 75.109 ;
     RECT  113.568 75.013 113.64 75.155 ;
     RECT  162.48 73.477 162.504 75.155 ;
     RECT  3.84 75.109 5.496 75.157 ;
     RECT  6.48 50.005 6.504 75.157 ;
     RECT  3.84 75.157 6.504 75.205 ;
     RECT  128.496 71.701 128.52 75.205 ;
     RECT  50.64 74.965 62.328 75.251 ;
     RECT  96.912 75.061 97.32 75.251 ;
     RECT  99.6 75.109 100.728 75.251 ;
     RECT  115.8 2.151 116.112 75.253 ;
     RECT  75.264 73.477 75.288 75.299 ;
     RECT  20.4 74.341 20.424 75.395 ;
     RECT  45.6 67.619 45.912 75.397 ;
     RECT  81.744 72.659 81.768 75.397 ;
     RECT  115.8 75.253 117 75.443 ;
     RECT  22.32 75.157 22.344 75.445 ;
     RECT  2.4 2.151 2.712 75.541 ;
     RECT  3.696 75.205 6.504 75.541 ;
     RECT  7.632 25.285 8.112 75.541 ;
     RECT  45.024 75.397 45.912 75.587 ;
     RECT  50.736 75.251 62.328 75.779 ;
     RECT  21.408 75.445 22.344 75.781 ;
     RECT  24 74.965 24.408 75.781 ;
     RECT  29.4 73.813 30.312 75.781 ;
     RECT  48.96 75.157 48.984 75.781 ;
     RECT  120.96 74.629 122.472 75.781 ;
     RECT  132 2.151 132.312 75.781 ;
     RECT  76.944 75.013 76.968 75.827 ;
     RECT  113.616 75.155 113.64 75.827 ;
     RECT  51 75.779 62.328 75.875 ;
     RECT  21.408 75.781 24.408 75.923 ;
     RECT  97.296 75.251 97.32 75.971 ;
     RECT  40.2 2.151 40.512 75.973 ;
     RECT  102.672 72.995 102.696 75.973 ;
     RECT  80.784 75.397 81.768 76.021 ;
     RECT  12.864 68.917 13.512 76.115 ;
     RECT  128.496 75.205 129 76.115 ;
     RECT  102.672 75.973 102.84 76.163 ;
     RECT  80.592 76.021 81.768 76.259 ;
     RECT  2.4 75.541 8.112 76.261 ;
     RECT  22.32 75.923 24.408 76.261 ;
     RECT  25.632 75.637 25.656 76.309 ;
     RECT  70.704 74.291 71.496 76.309 ;
     RECT  72.6 2.151 72.912 76.309 ;
     RECT  115.8 75.443 116.112 76.309 ;
     RECT  99.6 75.251 99.912 76.357 ;
     RECT  29.28 75.781 30.312 76.403 ;
     RECT  40.2 75.973 41.016 76.403 ;
     RECT  131.04 75.781 132.312 76.403 ;
     RECT  83.04 73.379 83.712 76.405 ;
     RECT  88.8 74.723 89.112 76.453 ;
     RECT  99.12 76.357 99.912 76.453 ;
     RECT  51 75.875 62.232 76.499 ;
     RECT  200.256 75.589 200.28 76.499 ;
     RECT  17.328 75.781 17.352 76.547 ;
     RECT  88.8 76.453 89.4 76.595 ;
     RECT  99.12 76.453 100.296 76.595 ;
     RECT  87.504 76.405 87.528 76.643 ;
     RECT  84.96 76.405 84.984 76.693 ;
     RECT  22.32 76.261 24.456 76.741 ;
     RECT  25.632 76.309 25.752 76.741 ;
     RECT  0.336 75.781 0.36 76.837 ;
     RECT  48.864 75.781 48.984 76.885 ;
     RECT  22.32 76.741 25.752 76.931 ;
     RECT  79.296 76.453 79.32 76.931 ;
     RECT  80.976 76.259 81.768 76.931 ;
     RECT  102.816 76.163 102.84 76.931 ;
     RECT  128.496 76.115 128.664 76.931 ;
     RECT  44.496 76.501 44.52 76.979 ;
     RECT  47.136 75.781 47.16 76.979 ;
     RECT  99.12 76.595 99.912 76.979 ;
     RECT  48.864 76.885 49.032 76.981 ;
     RECT  82.8 76.405 83.712 77.075 ;
     RECT  70.704 76.309 72.912 77.173 ;
     RECT  126.6 2.151 126.912 77.173 ;
     RECT  128.496 76.931 128.52 77.173 ;
     RECT  22.32 76.931 25.032 77.267 ;
     RECT  86.928 77.125 86.952 77.267 ;
     RECT  29.28 76.403 29.712 77.269 ;
     RECT  11.472 76.069 11.496 77.315 ;
     RECT  27.12 76.885 27.144 77.461 ;
     RECT  67.2 74.723 67.512 77.509 ;
     RECT  26.736 77.461 27.144 77.555 ;
     RECT  48.864 76.981 49.128 77.555 ;
     RECT  98.112 76.645 98.136 77.555 ;
     RECT  119.28 76.885 119.304 77.555 ;
     RECT  126.6 77.173 128.52 77.555 ;
     RECT  131.376 76.403 132.312 77.555 ;
     RECT  44.544 77.413 44.568 77.557 ;
     RECT  45.6 75.587 45.912 77.557 ;
     RECT  105 74.771 105.312 77.557 ;
     RECT  70.56 77.173 72.912 77.603 ;
     RECT  112.8 76.933 112.824 77.603 ;
     RECT  99.6 76.979 99.912 77.605 ;
     RECT  110.4 74.483 110.712 77.605 ;
     RECT  114.864 76.309 116.112 77.605 ;
     RECT  0.144 76.837 0.36 77.651 ;
     RECT  38.304 74.771 38.328 77.653 ;
     RECT  43.248 76.885 43.272 77.653 ;
     RECT  48.864 77.555 49.032 77.699 ;
     RECT  71.952 77.603 72.912 77.699 ;
     RECT  94.2 74.771 94.512 77.797 ;
     RECT  23.088 77.267 25.032 77.843 ;
     RECT  99.6 77.605 100.92 77.843 ;
     RECT  106.464 76.357 106.488 77.845 ;
     RECT  43.248 77.653 43.32 77.891 ;
     RECT  44.544 77.557 45.912 77.891 ;
     RECT  106.464 77.845 106.584 77.891 ;
     RECT  2.304 76.261 8.112 77.893 ;
     RECT  45.6 77.891 45.912 77.893 ;
     RECT  51 76.499 62.112 77.893 ;
     RECT  79.728 77.845 79.752 77.893 ;
     RECT  38.304 77.653 38.808 77.939 ;
     RECT  70.56 77.603 70.92 77.939 ;
     RECT  96.912 77.701 96.936 77.939 ;
     RECT  112.848 77.605 112.968 77.939 ;
     RECT  48.96 77.699 49.032 77.987 ;
     RECT  79.584 77.893 79.752 77.987 ;
     RECT  79.584 77.987 79.608 78.035 ;
     RECT  114.864 77.605 116.904 78.035 ;
     RECT  70.56 77.939 70.824 78.083 ;
     RECT  86.112 77.461 86.136 78.083 ;
     RECT  126.6 77.555 128.472 78.083 ;
     RECT  106.56 77.891 106.584 78.085 ;
     RECT  107.712 76.885 107.736 78.085 ;
     RECT  66.768 77.509 67.512 78.131 ;
     RECT  70.704 78.083 70.824 78.131 ;
     RECT  72.288 77.699 72.912 78.131 ;
     RECT  34.8 75.059 35.112 78.133 ;
     RECT  76.944 77.941 76.968 78.179 ;
     RECT  84.96 76.693 85.08 78.179 ;
     RECT  104.88 77.557 105.312 78.275 ;
     RECT  106.56 78.085 107.736 78.323 ;
     RECT  40.2 76.403 40.512 78.325 ;
     RECT  81.744 76.931 81.768 78.373 ;
     RECT  88.8 76.595 89.112 78.469 ;
     RECT  80.928 78.373 81.768 78.515 ;
     RECT  107.52 78.323 107.736 78.515 ;
     RECT  120.336 75.781 122.472 78.515 ;
     RECT  50.496 77.893 62.112 78.565 ;
     RECT  207.024 73.811 207.912 78.611 ;
     RECT  94.2 77.797 94.632 78.613 ;
     RECT  105 78.275 105.312 78.613 ;
     RECT  110.4 77.605 111.048 78.613 ;
     RECT  0.192 77.651 0.36 78.649 ;
     RECT  38.304 77.939 38.472 78.659 ;
     RECT  16.368 77.749 16.392 78.707 ;
     RECT  43.296 77.891 43.32 78.707 ;
     RECT  48.96 77.987 48.984 78.707 ;
     RECT  39.84 78.325 40.512 78.755 ;
     RECT  102.144 78.085 102.168 78.853 ;
     RECT  97.104 78.037 97.128 78.899 ;
     RECT  102.144 78.853 103.032 78.899 ;
     RECT  110.4 78.613 111.912 78.901 ;
     RECT  114.864 78.035 116.568 78.947 ;
     RECT  121.2 78.515 122.472 78.947 ;
     RECT  47.856 78.613 47.88 78.949 ;
     RECT  29.136 77.269 29.712 79.045 ;
     RECT  0.24 78.649 0.36 79.141 ;
     RECT  23.088 77.843 24.408 79.189 ;
     RECT  81.312 78.515 81.768 79.235 ;
     RECT  83.4 77.075 83.712 79.237 ;
     RECT  11.616 78.325 11.64 79.283 ;
     RECT  75.408 78.469 75.432 79.283 ;
     RECT  99.6 77.843 100.296 79.285 ;
     RECT  115.8 78.947 116.568 79.427 ;
     RECT  118.272 77.509 118.296 79.427 ;
     RECT  83.4 79.237 83.928 79.475 ;
     RECT  125.52 77.989 125.544 79.475 ;
     RECT  23.088 79.189 25.128 79.523 ;
     RECT  63.696 77.941 63.72 79.667 ;
     RECT  110.256 78.901 111.912 79.667 ;
     RECT  26.736 77.555 27.048 79.717 ;
     RECT  23.088 79.523 24.648 79.763 ;
     RECT  44.544 77.891 44.568 79.763 ;
     RECT  88.8 78.469 89.928 79.763 ;
     RECT  91.44 78.613 91.464 79.763 ;
     RECT  96.336 79.189 96.36 79.763 ;
     RECT  72.48 78.131 72.912 79.765 ;
     RECT  50.256 78.565 62.112 79.811 ;
     RECT  0.24 79.141 0.456 79.859 ;
     RECT  26.4 79.717 27.048 79.859 ;
     RECT  85.488 79.189 85.512 79.859 ;
     RECT  40.2 78.755 40.512 79.957 ;
     RECT  70.704 78.131 70.728 79.957 ;
     RECT  23.616 79.763 24.648 80.003 ;
     RECT  70.704 79.957 71.256 80.003 ;
     RECT  107.712 78.515 107.736 80.003 ;
     RECT  0.24 79.859 0.36 80.005 ;
     RECT  87.216 79.717 87.24 80.053 ;
     RECT  99.6 79.285 100.824 80.101 ;
     RECT  99.6 80.101 101.64 80.147 ;
     RECT  105 78.613 105.48 80.149 ;
     RECT  81.744 79.235 81.768 80.291 ;
     RECT  105 80.149 106.008 80.293 ;
     RECT  0.192 80.005 0.36 80.341 ;
     RECT  45.6 77.893 46.728 80.341 ;
     RECT  47.856 78.949 47.976 80.341 ;
     RECT  67.2 78.131 67.512 80.341 ;
     RECT  91.248 80.245 91.272 80.387 ;
     RECT  45.6 80.341 47.976 80.435 ;
     RECT  110.256 79.667 111.48 80.435 ;
     RECT  103.008 78.899 103.032 80.483 ;
     RECT  0.144 80.341 0.36 80.531 ;
     RECT  50.736 79.811 62.112 80.531 ;
     RECT  94.2 78.613 95.16 80.531 ;
     RECT  69.072 79.189 69.096 80.533 ;
     RECT  69.072 80.533 69.96 80.579 ;
     RECT  108.672 80.389 108.696 80.581 ;
     RECT  100.896 80.147 101.64 80.627 ;
     RECT  108.672 80.581 108.888 80.627 ;
     RECT  97.824 78.901 97.848 80.629 ;
     RECT  108.864 80.627 108.888 80.819 ;
     RECT  40.2 79.957 41.016 80.821 ;
     RECT  45.6 80.435 46.968 80.821 ;
     RECT  84.912 80.725 84.936 80.821 ;
     RECT  84.912 80.821 85.08 80.867 ;
     RECT  104.88 80.293 106.008 80.915 ;
     RECT  37.008 80.821 37.032 80.963 ;
     RECT  40.2 80.821 41.064 80.963 ;
     RECT  45.024 80.821 46.968 80.963 ;
     RECT  85.056 80.867 85.08 80.963 ;
     RECT  92.88 80.821 92.904 80.963 ;
     RECT  11.952 79.861 11.976 81.011 ;
     RECT  101.616 80.627 101.64 81.011 ;
     RECT  50.784 80.531 62.112 81.059 ;
     RECT  67.2 80.341 67.8 81.299 ;
     RECT  45.6 80.963 46.968 81.347 ;
     RECT  49.344 80.485 49.368 81.347 ;
     RECT  86.304 80.053 87.24 81.491 ;
     RECT  104.88 80.915 105.312 81.491 ;
     RECT  42.72 81.061 42.744 81.539 ;
     RECT  142.8 72.901 143.208 81.539 ;
     RECT  2.304 77.893 8.76 81.587 ;
     RECT  71.232 80.003 71.256 81.587 ;
     RECT  76.128 80.773 76.152 81.587 ;
     RECT  97.632 80.629 97.848 81.587 ;
     RECT  2.304 81.587 2.856 81.635 ;
     RECT  47.952 80.435 47.976 81.637 ;
     RECT  86.304 81.491 86.952 81.683 ;
     RECT  91.488 81.061 91.512 81.923 ;
     RECT  149.952 79.765 149.976 81.973 ;
     RECT  151.296 79.765 151.32 81.973 ;
     RECT  97.824 81.587 97.848 82.021 ;
     RECT  105 81.491 105.312 82.021 ;
     RECT  115.8 79.427 116.112 82.021 ;
     RECT  40.2 80.963 41.016 82.115 ;
     RECT  85.152 80.965 85.176 82.115 ;
     RECT  86.304 81.683 86.328 82.115 ;
     RECT  149.952 81.973 151.32 82.115 ;
     RECT  149.952 82.115 150.456 82.163 ;
     RECT  34.8 78.133 35.208 82.211 ;
     RECT  38.448 78.659 38.472 82.211 ;
     RECT  51 81.059 62.112 82.213 ;
     RECT  110.256 80.435 110.712 82.309 ;
     RECT  112.656 82.021 112.68 82.355 ;
     RECT  46.944 81.347 46.968 82.357 ;
     RECT  47.952 81.637 48.456 82.357 ;
     RECT  51 82.213 62.712 82.451 ;
     RECT  115.8 82.021 116.472 82.451 ;
     RECT  99.6 80.147 99.912 82.549 ;
     RECT  91.536 81.973 91.704 82.643 ;
     RECT  21.168 78.325 21.192 82.691 ;
     RECT  97.824 82.021 97.944 82.691 ;
     RECT  110.256 82.309 111.624 82.691 ;
     RECT  122.544 79.621 122.568 82.691 ;
     RECT  150.432 82.163 150.456 82.691 ;
     RECT  0.144 80.531 0.312 82.739 ;
     RECT  91.68 82.643 91.704 82.789 ;
     RECT  97.92 82.691 97.944 82.837 ;
     RECT  97.92 82.837 98.04 82.883 ;
     RECT  153.6 2.151 153.912 82.981 ;
     RECT  154.992 73.909 159.864 82.981 ;
     RECT  2.4 81.635 2.856 83.125 ;
     RECT  3.888 81.587 8.76 83.125 ;
     RECT  43.92 81.973 43.944 83.173 ;
     RECT  69.936 80.579 69.96 83.219 ;
     RECT  72.384 79.765 72.912 83.267 ;
     RECT  153.6 82.981 159.864 83.267 ;
     RECT  23.904 80.003 24.648 83.507 ;
     RECT  108.288 82.021 108.312 83.507 ;
     RECT  91.68 82.789 91.752 83.651 ;
     RECT  43.92 83.173 44.472 83.699 ;
     RECT  51 82.451 62.112 83.701 ;
     RECT  0.144 82.739 0.264 83.749 ;
     RECT  18.6 2.151 18.912 83.749 ;
     RECT  91.728 83.651 91.752 83.795 ;
     RECT  99.12 82.549 99.912 83.795 ;
     RECT  105 82.021 106.44 83.795 ;
     RECT  50.736 83.701 62.112 83.843 ;
     RECT  98.016 82.883 98.04 83.843 ;
     RECT  155.328 83.267 159.864 83.891 ;
     RECT  106.416 83.795 106.44 83.987 ;
     RECT  14.784 83.749 14.808 84.083 ;
     RECT  0.144 83.749 0.312 84.181 ;
     RECT  40.2 82.115 40.512 84.229 ;
     RECT  46.944 82.357 48.456 84.325 ;
     RECT  46.896 84.325 48.456 84.419 ;
     RECT  17.712 83.749 18.912 84.611 ;
     RECT  28.464 79.045 29.712 84.707 ;
     RECT  24 83.507 24.648 84.755 ;
     RECT  0.144 84.181 0.408 85.187 ;
     RECT  39.648 84.229 40.512 85.381 ;
     RECT  2.4 83.125 8.76 85.477 ;
     RECT  39.648 85.381 41.064 85.523 ;
     RECT  26.4 79.859 26.424 85.571 ;
     RECT  16.032 85.141 16.056 85.859 ;
     RECT  46.896 84.419 47.832 85.909 ;
     RECT  2.4 85.477 9.72 85.955 ;
     RECT  37.584 84.325 37.608 85.955 ;
     RECT  46.896 85.909 47.976 85.955 ;
     RECT  2.4 85.955 8.52 86.005 ;
     RECT  14.688 85.621 14.712 86.051 ;
     RECT  51 83.843 62.112 86.051 ;
     RECT  18.48 84.611 18.912 86.099 ;
     RECT  51 86.051 60.792 86.291 ;
     RECT  45.6 81.347 45.912 86.485 ;
     RECT  44.88 86.485 45.912 86.627 ;
     RECT  2.304 86.005 8.52 86.675 ;
     RECT  9.696 85.955 9.72 86.675 ;
     RECT  15.984 85.957 16.008 86.675 ;
     RECT  40.2 85.523 41.064 86.675 ;
     RECT  51 86.291 60.408 87.109 ;
     RECT  2.304 86.675 6.744 87.299 ;
     RECT  7.8 86.675 8.52 87.299 ;
     RECT  47.808 85.955 47.976 87.827 ;
     RECT  2.304 87.299 6.408 87.923 ;
     RECT  0.144 85.187 0.312 88.163 ;
     RECT  2.4 87.923 6.408 88.403 ;
     RECT  0.144 88.163 0.168 88.451 ;
     RECT  2.4 88.403 5.928 88.499 ;
     RECT  2.4 88.499 5.688 88.547 ;
     RECT  2.4 88.547 3.912 88.979 ;
     RECT  5.136 88.547 5.688 88.979 ;
     RECT  41.568 87.541 41.592 88.979 ;
     RECT  2.4 88.979 3.816 89.027 ;
     RECT  5.136 88.979 5.64 89.075 ;
     RECT  2.4 89.027 3.624 89.171 ;
     RECT  2.4 89.171 3.336 89.555 ;
     RECT  5.136 89.075 5.16 89.555 ;
     RECT  33.072 87.157 33.096 90.563 ;
     RECT  155.376 83.891 159.864 91.619 ;
     RECT  155.376 91.619 159.312 92.483 ;
     RECT  50.88 87.109 60.408 94.115 ;
     RECT  155.376 92.483 157.656 95.651 ;
     RECT  155.376 95.651 157.56 96.515 ;
     RECT  155.376 96.515 156.888 96.611 ;
     RECT  155.376 96.611 156.84 96.707 ;
     RECT  155.376 96.707 155.784 96.995 ;
     RECT  155.376 96.995 155.688 97.283 ;
     RECT  156.816 96.707 156.84 97.667 ;
     RECT  155.424 97.283 155.688 107.747 ;
     RECT  155.616 107.747 155.688 107.843 ;
     RECT  155.616 107.843 155.64 113.987 ;
     RECT  45.6 86.627 45.912 116.437 ;
     RECT  51 94.115 60.408 118.643 ;
     RECT  52.944 118.643 60.408 118.739 ;
     RECT  51 118.643 51.864 121.715 ;
     RECT  53.28 118.739 60.408 122.339 ;
     RECT  59.568 122.339 60.408 122.435 ;
     RECT  53.28 122.339 58.104 123.107 ;
     RECT  53.28 123.107 58.008 124.835 ;
     RECT  53.28 124.835 57.864 125.123 ;
     RECT  55.152 125.123 57.864 125.171 ;
     RECT  59.616 122.435 60.408 125.219 ;
     RECT  59.616 125.219 59.832 125.507 ;
     RECT  59.712 125.507 59.832 125.603 ;
     RECT  55.344 125.171 57.864 125.699 ;
     RECT  56.4 125.699 57.864 125.795 ;
     RECT  53.28 125.123 53.976 125.891 ;
     RECT  57.84 125.795 57.864 125.987 ;
     RECT  53.952 125.891 53.976 126.035 ;
     RECT  57.888 126.037 57.912 126.179 ;
     RECT  59.712 125.603 59.784 126.275 ;
     RECT  55.344 125.699 55.368 126.467 ;
     RECT  59.76 126.275 59.784 126.515 ;
     RECT  49.344 113.317 49.368 131.699 ;
     RECT  44.64 116.437 45.912 148.259 ;
     RECT  2.4 89.555 2.712 149.049 ;
     RECT  7.8 87.299 8.112 149.049 ;
     RECT  13.2 76.115 13.512 149.049 ;
     RECT  18.6 86.099 18.912 149.049 ;
     RECT  24 84.755 24.312 149.049 ;
     RECT  29.4 84.707 29.712 149.049 ;
     RECT  34.8 82.211 35.112 149.049 ;
     RECT  40.2 86.675 40.512 149.049 ;
     RECT  44.976 148.259 45.912 149.049 ;
     RECT  51 121.715 51.312 149.049 ;
     RECT  56.4 125.795 56.712 149.049 ;
     RECT  61.8 86.051 62.112 149.049 ;
     RECT  67.2 81.299 67.512 149.049 ;
     RECT  72.6 83.267 72.912 149.049 ;
     RECT  78 2.151 78.312 149.049 ;
     RECT  83.4 79.475 83.712 149.049 ;
     RECT  88.8 79.763 89.112 149.049 ;
     RECT  94.2 80.531 94.512 149.049 ;
     RECT  99.6 83.795 99.912 149.049 ;
     RECT  105 83.795 105.312 149.049 ;
     RECT  110.4 82.691 110.712 149.049 ;
     RECT  115.8 82.451 116.112 149.049 ;
     RECT  121.2 78.947 121.512 149.049 ;
     RECT  126.6 78.083 126.912 149.049 ;
     RECT  132 77.555 132.312 149.049 ;
     RECT  137.4 2.151 137.712 149.049 ;
     RECT  142.8 81.539 143.112 149.049 ;
     RECT  148.2 2.151 148.512 149.049 ;
     RECT  153.6 83.267 153.912 149.049 ;
     RECT  159 92.483 159.312 149.049 ;
     RECT  164.4 2.151 164.712 149.049 ;
     RECT  169.8 2.151 170.112 149.049 ;
     RECT  175.2 2.151 175.512 149.049 ;
     RECT  180.6 2.151 180.912 149.049 ;
     RECT  186 2.151 186.312 149.049 ;
     RECT  191.4 73.523 191.712 149.049 ;
     RECT  196.8 74.675 197.112 149.049 ;
     RECT  202.2 69.731 202.512 149.049 ;
     RECT  207.6 78.611 207.912 149.049 ;
     RECT  213 70.643 213.312 149.049 ;
     RECT  2.4 149.049 2.52 149.063 ;
     RECT  7.8 149.049 7.92 149.063 ;
     RECT  13.2 149.049 13.32 149.063 ;
     RECT  18.6 149.049 18.72 149.063 ;
     RECT  24 149.049 24.12 149.063 ;
     RECT  29.4 149.049 29.52 149.063 ;
     RECT  34.8 149.049 34.92 149.063 ;
     RECT  40.2 149.049 40.32 149.063 ;
     RECT  44.976 149.049 45.72 149.063 ;
     RECT  51 149.049 51.12 149.063 ;
     RECT  56.4 149.049 56.52 149.063 ;
     RECT  61.8 149.049 61.92 149.063 ;
     RECT  67.2 149.049 67.32 149.063 ;
     RECT  72.6 149.049 72.72 149.063 ;
     RECT  78 149.049 78.12 149.063 ;
     RECT  83.4 149.049 83.52 149.063 ;
     RECT  88.8 149.049 88.92 149.063 ;
     RECT  94.2 149.049 94.32 149.063 ;
     RECT  99.6 149.049 99.72 149.063 ;
     RECT  105 149.049 105.12 149.063 ;
     RECT  110.4 149.049 110.52 149.063 ;
     RECT  115.8 149.049 115.92 149.063 ;
     RECT  121.2 149.049 121.32 149.063 ;
     RECT  126.6 149.049 126.72 149.063 ;
     RECT  132 149.049 132.12 149.063 ;
     RECT  137.4 149.049 137.52 149.063 ;
     RECT  142.8 149.049 142.92 149.063 ;
     RECT  148.2 149.049 148.32 149.063 ;
     RECT  153.6 149.049 153.72 149.063 ;
     RECT  159 149.049 159.12 149.063 ;
     RECT  164.4 149.049 164.52 149.063 ;
     RECT  169.8 149.049 169.92 149.063 ;
     RECT  175.2 149.049 175.32 149.063 ;
     RECT  180.6 149.049 180.72 149.063 ;
     RECT  186 149.049 186.12 149.063 ;
     RECT  191.4 149.049 191.52 149.063 ;
     RECT  196.8 149.049 196.92 149.063 ;
     RECT  202.2 149.049 202.32 149.063 ;
     RECT  207.6 149.049 207.72 149.063 ;
     RECT  213 149.049 213.12 149.063 ;
     RECT  44.976 149.063 45 150.515 ;
     RECT  47.808 87.827 47.832 151.139 ;
     RECT  56.712 24.805 57.696 27.925 ;
     RECT  153.912 25.477 155.376 69.109 ;
     RECT  58.344 27.541 59.808 27.731 ;
     RECT  157.08 27.781 158.592 29.221 ;
     RECT  157.08 29.221 158.496 30.373 ;
     RECT  56.712 30.323 57.696 32.773 ;
     RECT  60.408 32.197 61.8 32.387 ;
     RECT  51.312 41.509 52.368 43.669 ;
     RECT  53.112 47.221 54.576 48.707 ;
     RECT  51.312 47.267 52.464 67.957 ;
     RECT  53.016 48.707 54.576 50.005 ;
     RECT  56.712 49.091 57.696 50.053 ;
     RECT  58.344 49.957 59.52 51.301 ;
     RECT  6.504 50.005 7.632 75.541 ;
     RECT  53.064 50.005 54.576 50.771 ;
     RECT  5.208 50.581 6.48 75.013 ;
     RECT  53.016 50.771 54.576 51.109 ;
     RECT  53.016 51.109 54.384 53.941 ;
     RECT  53.112 53.941 54.384 54.853 ;
     RECT  60.408 54.277 61.8 65.029 ;
     RECT  53.112 54.853 54.096 56.245 ;
     RECT  27.192 65.701 28.416 65.747 ;
     RECT  27.096 65.747 28.416 67.331 ;
     RECT  29.28 67.331 29.4 68.341 ;
     RECT  83.712 68.339 83.832 69.589 ;
     RECT  62.112 68.341 63.216 69.011 ;
     RECT  72.912 68.389 74.112 70.307 ;
     RECT  81.768 69.059 83.28 69.539 ;
     RECT  153.912 69.109 155.28 70.451 ;
     RECT  30.6 69.301 31.632 69.347 ;
     RECT  83.712 69.589 85.104 69.731 ;
     RECT  67.512 69.829 69.024 70.691 ;
     RECT  202.512 70.069 203.76 70.981 ;
     RECT  89.112 70.117 90.288 71.173 ;
     RECT  153.912 70.451 155.376 73.909 ;
     RECT  121.512 70.837 122.496 72.851 ;
     RECT  80.472 70.885 81.744 71.557 ;
     RECT  202.512 70.981 203.616 72.947 ;
     RECT  90.312 71.173 91.776 71.987 ;
     RECT  80.616 71.557 81.744 71.699 ;
     RECT  116.112 71.653 117.552 71.749 ;
     RECT  80.928 71.699 81.744 72.517 ;
     RECT  116.112 71.749 117.408 72.563 ;
     RECT  71.4 71.797 72.6 72.901 ;
     RECT  102.696 71.797 104.016 72.805 ;
     RECT  36.984 72.133 38.304 74.533 ;
     RECT  121.512 72.851 122.472 73.765 ;
     RECT  71.496 72.901 72.6 76.309 ;
     RECT  168.696 72.901 169.8 74.627 ;
     RECT  197.112 72.901 198.384 73.571 ;
     RECT  117.864 72.949 119.136 73.235 ;
     RECT  78.312 73.045 79.824 73.523 ;
     RECT  81.768 73.333 83.04 76.405 ;
     RECT  107.928 73.333 109.248 73.523 ;
     RECT  109.272 73.333 110.4 74.341 ;
     RECT  32.952 73.573 34.272 73.715 ;
     RECT  110.712 73.811 110.808 74.005 ;
     RECT  153.912 73.909 154.992 82.981 ;
     RECT  110.712 74.005 112.08 74.819 ;
     RECT  112.104 74.005 113.568 74.819 ;
     RECT  94.512 74.053 95.664 74.533 ;
     RECT  106.152 74.053 107.472 74.771 ;
     RECT  128.52 74.053 129.936 74.771 ;
     RECT  18.912 74.341 20.4 75.395 ;
     RECT  109.272 74.341 110.304 74.483 ;
     RECT  109.272 74.483 110.4 74.579 ;
     RECT  36.984 74.533 38.208 74.579 ;
     RECT  94.632 74.533 95.664 74.771 ;
     RECT  94.512 74.771 95.664 75.107 ;
     RECT  128.52 74.771 129 75.205 ;
     RECT  95.688 74.965 96.912 75.107 ;
     RECT  5.496 75.013 6.48 75.157 ;
     RECT  76.968 75.013 78 75.827 ;
     RECT  2.712 75.109 3.84 75.205 ;
     RECT  2.712 75.205 3.696 75.541 ;
     RECT  99.912 75.251 100.296 76.453 ;
     RECT  45.024 75.587 45.6 76.501 ;
     RECT  24.408 75.637 25.632 76.261 ;
     RECT  17.352 75.781 18.6 76.547 ;
     RECT  45.912 75.781 47.136 76.979 ;
     RECT  11.496 76.069 12.864 76.115 ;
     RECT  24.456 76.261 25.632 76.741 ;
     RECT  105.312 76.357 106.464 77.891 ;
     RECT  81.768 76.405 82.8 77.075 ;
     RECT  83.712 76.405 84.96 78.179 ;
     RECT  87.528 76.405 88.8 76.643 ;
     RECT  78.312 76.453 79.296 76.931 ;
     RECT  44.52 76.501 45.6 76.979 ;
     RECT  99.912 76.595 100.296 77.605 ;
     RECT  98.136 76.645 99.12 76.979 ;
     RECT  25.752 76.885 27.12 76.931 ;
     RECT  43.272 76.885 44.496 76.979 ;
     RECT  106.488 76.885 107.712 77.845 ;
     RECT  119.304 76.885 120.336 77.555 ;
     RECT  26.736 76.931 27.12 77.461 ;
     RECT  78.312 76.931 79.32 77.845 ;
     RECT  80.976 76.931 81.744 77.845 ;
     RECT  43.272 76.979 45.6 77.413 ;
     RECT  45.912 76.979 46.728 77.893 ;
     RECT  98.136 76.979 99.6 77.555 ;
     RECT  43.272 77.413 44.544 77.653 ;
     RECT  44.568 77.413 45.6 77.557 ;
     RECT  85.08 77.461 86.112 78.083 ;
     RECT  118.296 77.509 119.28 77.555 ;
     RECT  27.048 77.555 27.144 79.045 ;
     RECT  49.032 77.555 49.128 77.893 ;
     RECT  70.92 77.603 71.952 77.699 ;
     RECT  116.904 77.605 118.272 78.035 ;
     RECT  38.808 77.653 40.2 77.939 ;
     RECT  43.32 77.653 44.544 78.707 ;
     RECT  48.864 77.699 48.96 78.613 ;
     RECT  70.92 77.699 72.288 77.939 ;
     RECT  24.408 77.843 25.032 79.189 ;
     RECT  100.296 77.843 100.92 78.085 ;
     RECT  78.312 77.845 79.728 77.893 ;
     RECT  79.752 77.845 81.744 77.987 ;
     RECT  106.584 77.845 107.712 78.085 ;
     RECT  44.568 77.891 45.6 79.763 ;
     RECT  105.312 77.891 106.56 78.323 ;
     RECT  49.032 77.893 50.496 77.987 ;
     RECT  78.312 77.893 79.584 78.035 ;
     RECT  38.472 77.939 40.2 78.325 ;
     RECT  70.824 77.939 72.288 78.131 ;
     RECT  96.912 77.939 96.936 78.037 ;
     RECT  76.968 77.941 78 78.179 ;
     RECT  48.984 77.987 50.496 78.565 ;
     RECT  79.608 77.987 81.744 78.035 ;
     RECT  125.544 77.989 126.6 79.475 ;
     RECT  80.928 78.035 81.744 78.373 ;
     RECT  96.912 78.037 97.104 78.899 ;
     RECT  85.08 78.083 85.512 78.179 ;
     RECT  100.296 78.085 102.144 78.899 ;
     RECT  83.712 78.179 83.928 79.237 ;
     RECT  85.488 78.179 85.512 79.189 ;
     RECT  105.312 78.323 105.48 78.613 ;
     RECT  38.472 78.325 39.84 78.755 ;
     RECT  48.984 78.565 50.256 78.707 ;
     RECT  46.728 78.613 47.856 80.341 ;
     RECT  47.88 78.613 48.96 78.707 ;
     RECT  89.928 78.613 91.44 79.763 ;
     RECT  0.192 78.649 0.24 80.005 ;
     RECT  47.88 78.707 47.976 78.949 ;
     RECT  96.912 78.899 97.128 78.901 ;
     RECT  100.296 78.899 103.008 79.285 ;
     RECT  96.912 78.901 97.824 79.189 ;
     RECT  121.512 78.947 122.472 79.621 ;
     RECT  27.048 79.045 28.464 79.859 ;
     RECT  95.16 79.189 96.336 79.763 ;
     RECT  96.36 79.189 97.824 79.763 ;
     RECT  100.824 79.285 103.008 80.101 ;
     RECT  83.712 79.475 83.928 80.725 ;
     RECT  121.512 79.621 122.544 82.691 ;
     RECT  45.024 79.763 45.6 80.821 ;
     RECT  91.248 79.763 91.272 80.245 ;
     RECT  97.632 79.763 97.824 80.629 ;
     RECT  148.512 79.765 149.952 82.163 ;
     RECT  149.976 79.765 151.296 81.973 ;
     RECT  50.256 79.811 50.736 80.485 ;
     RECT  85.488 79.859 85.512 80.053 ;
     RECT  11.976 79.861 13.2 81.011 ;
     RECT  71.256 79.957 72.384 81.587 ;
     RECT  70.704 80.003 71.232 80.533 ;
     RECT  85.488 80.053 86.304 80.725 ;
     RECT  101.64 80.101 103.008 80.483 ;
     RECT  99.912 80.147 100.896 80.627 ;
     RECT  67.8 80.341 69.072 80.579 ;
     RECT  46.968 80.435 47.952 82.357 ;
     RECT  47.976 80.485 49.344 81.347 ;
     RECT  49.368 80.485 50.736 80.531 ;
     RECT  49.368 80.531 50.784 81.059 ;
     RECT  69.96 80.533 71.232 81.587 ;
     RECT  108.888 80.581 110.256 80.819 ;
     RECT  83.712 80.725 84.912 80.867 ;
     RECT  84.936 80.725 86.304 80.821 ;
     RECT  37.032 80.821 38.448 80.963 ;
     RECT  85.08 80.821 86.304 80.963 ;
     RECT  92.904 80.821 94.2 80.963 ;
     RECT  83.712 80.867 85.056 80.963 ;
     RECT  105.312 80.915 106.008 82.021 ;
     RECT  83.712 80.963 86.304 80.965 ;
     RECT  83.712 80.965 85.152 82.115 ;
     RECT  85.176 80.965 86.304 82.115 ;
     RECT  45.912 81.347 46.944 84.325 ;
     RECT  47.976 81.347 48.456 81.637 ;
     RECT  2.856 81.587 3.888 83.125 ;
     RECT  111.624 82.309 112.656 82.355 ;
     RECT  97.944 82.549 99.12 82.837 ;
     RECT  0.264 82.739 0.312 83.749 ;
     RECT  98.04 82.837 99.12 83.795 ;
     RECT  44.472 83.173 45.6 83.699 ;
     RECT  153.912 83.267 155.328 83.891 ;
     RECT  13.512 83.749 14.784 84.083 ;
     RECT  105.312 83.795 106.416 83.987 ;
     RECT  153.912 83.891 155.376 97.283 ;
     RECT  45.912 84.325 46.896 85.955 ;
     RECT  47.832 84.419 47.976 85.909 ;
     RECT  13.512 85.621 14.688 86.051 ;
     RECT  14.712 85.621 16.032 85.859 ;
     RECT  14.712 85.859 16.008 85.957 ;
     RECT  8.52 85.955 9.696 86.675 ;
     RECT  14.712 85.957 15.984 86.051 ;
     RECT  60.792 86.051 61.8 86.291 ;
     RECT  60.408 86.291 61.8 125.219 ;
     RECT  6.744 86.675 7.8 87.299 ;
     RECT  40.512 86.675 41.064 87.541 ;
     RECT  6.408 87.299 7.8 88.403 ;
     RECT  40.512 87.541 41.568 88.979 ;
     RECT  3.912 88.547 5.136 88.979 ;
     RECT  3.816 88.979 5.136 89.027 ;
     RECT  3.624 89.027 5.136 89.171 ;
     RECT  157.656 92.483 159 95.651 ;
     RECT  157.56 95.651 159 96.515 ;
     RECT  155.784 96.707 156.816 96.995 ;
     RECT  155.688 96.995 156.816 97.667 ;
     RECT  153.912 97.283 155.424 107.747 ;
     RECT  47.832 113.317 49.344 131.699 ;
     RECT  51.864 118.643 52.944 118.739 ;
     RECT  51.864 118.739 53.28 121.715 ;
     RECT  58.104 122.339 59.568 122.435 ;
     RECT  58.104 122.435 59.616 123.107 ;
     RECT  57.864 124.835 57.912 125.987 ;
     RECT  53.976 125.123 55.152 125.171 ;
     RECT  53.976 125.171 55.344 126.035 ;
     RECT  55.368 125.699 56.4 126.467 ;
     RECT  56.712 125.795 57.84 125.987 ;
     RECT  56.712 125.987 57.912 126.037 ;
     RECT  56.712 126.037 57.888 126.179 ;
  END
END ot_hbm_su_reduce_static
END LIBRARY
